VERSION 5.8 ;
BUSBITCHARS "[]" ;
DIVIDERCHAR "/" ;
UNITS
    DATABASE MICRONS 1000 ;
END UNITS

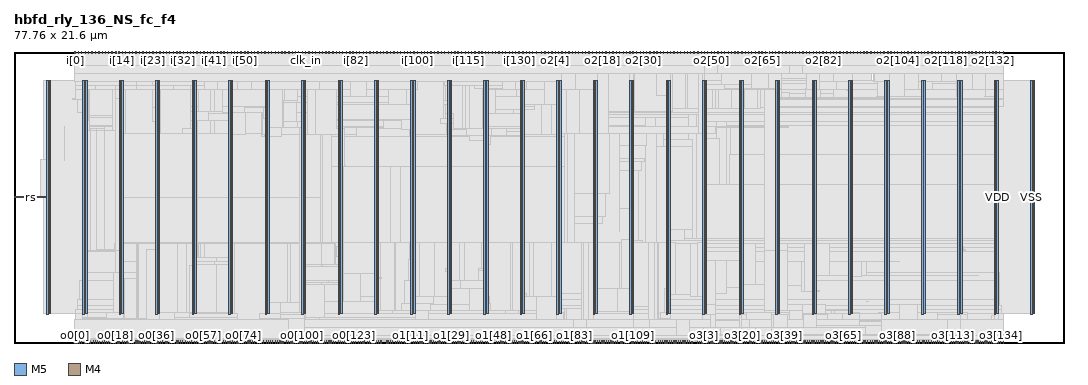
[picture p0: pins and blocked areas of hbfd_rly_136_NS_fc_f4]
MACRO hbfd_rly_136_NS_fc_f4
  FOREIGN hbfd_rly_136_NS_fc_f4 0 0 ;
  CLASS BLOCK ;
  SIZE 77.76 BY 21.6 ;
  PIN clk_in
    DIRECTION INPUT ;
    USE SIGNAL ;
    PORT
      LAYER M5 ;
        RECT  21.6 21.408 21.624 21.6 ;
    END
  END clk_in
  PIN clk_out0
    DIRECTION OUTPUT ;
    USE SIGNAL ;
    PORT
      LAYER M5 ;
        RECT  15.84 0 15.864 0.192 ;
    END
  END clk_out0
  PIN clk_out1
    DIRECTION OUTPUT ;
    USE SIGNAL ;
    PORT
      LAYER M5 ;
        RECT  38.88 0 38.904 0.192 ;
    END
  END clk_out1
  PIN clk_out2
    DIRECTION OUTPUT ;
    USE SIGNAL ;
    PORT
      LAYER M5 ;
        RECT  56.16 21.408 56.184 21.6 ;
    END
  END clk_out2
  PIN clk_out3
    DIRECTION OUTPUT ;
    USE SIGNAL ;
    PORT
      LAYER M5 ;
        RECT  61.92 0 61.944 0.192 ;
    END
  END clk_out3
  PIN i[0]
    DIRECTION INPUT ;
    USE SIGNAL ;
    PORT
      LAYER M5 ;
        RECT  4.512 21.408 4.536 21.6 ;
    END
  END i[0]
  PIN i[100]
    DIRECTION INPUT ;
    USE SIGNAL ;
    PORT
      LAYER M5 ;
        RECT  29.856 21.408 29.88 21.6 ;
    END
  END i[100]
  PIN i[101]
    DIRECTION INPUT ;
    USE SIGNAL ;
    PORT
      LAYER M5 ;
        RECT  30.144 21.408 30.168 21.6 ;
    END
  END i[101]
  PIN i[102]
    DIRECTION INPUT ;
    USE SIGNAL ;
    PORT
      LAYER M5 ;
        RECT  30.384 21.408 30.408 21.6 ;
    END
  END i[102]
  PIN i[103]
    DIRECTION INPUT ;
    USE SIGNAL ;
    PORT
      LAYER M5 ;
        RECT  30.624 21.408 30.648 21.6 ;
    END
  END i[103]
  PIN i[104]
    DIRECTION INPUT ;
    USE SIGNAL ;
    PORT
      LAYER M5 ;
        RECT  30.864 21.408 30.888 21.6 ;
    END
  END i[104]
  PIN i[105]
    DIRECTION INPUT ;
    USE SIGNAL ;
    PORT
      LAYER M5 ;
        RECT  31.152 21.408 31.176 21.6 ;
    END
  END i[105]
  PIN i[106]
    DIRECTION INPUT ;
    USE SIGNAL ;
    PORT
      LAYER M5 ;
        RECT  31.392 21.408 31.416 21.6 ;
    END
  END i[106]
  PIN i[107]
    DIRECTION INPUT ;
    USE SIGNAL ;
    PORT
      LAYER M5 ;
        RECT  31.632 21.408 31.656 21.6 ;
    END
  END i[107]
  PIN i[108]
    DIRECTION INPUT ;
    USE SIGNAL ;
    PORT
      LAYER M5 ;
        RECT  31.872 21.408 31.896 21.6 ;
    END
  END i[108]
  PIN i[109]
    DIRECTION INPUT ;
    USE SIGNAL ;
    PORT
      LAYER M5 ;
        RECT  32.16 21.408 32.184 21.6 ;
    END
  END i[109]
  PIN i[10]
    DIRECTION INPUT ;
    USE SIGNAL ;
    PORT
      LAYER M5 ;
        RECT  7.008 21.408 7.032 21.6 ;
    END
  END i[10]
  PIN i[110]
    DIRECTION INPUT ;
    USE SIGNAL ;
    PORT
      LAYER M5 ;
        RECT  32.4 21.408 32.424 21.6 ;
    END
  END i[110]
  PIN i[111]
    DIRECTION INPUT ;
    USE SIGNAL ;
    PORT
      LAYER M5 ;
        RECT  32.64 21.408 32.664 21.6 ;
    END
  END i[111]
  PIN i[112]
    DIRECTION INPUT ;
    USE SIGNAL ;
    PORT
      LAYER M5 ;
        RECT  32.88 21.408 32.904 21.6 ;
    END
  END i[112]
  PIN i[113]
    DIRECTION INPUT ;
    USE SIGNAL ;
    PORT
      LAYER M5 ;
        RECT  33.12 21.408 33.144 21.6 ;
    END
  END i[113]
  PIN i[114]
    DIRECTION INPUT ;
    USE SIGNAL ;
    PORT
      LAYER M5 ;
        RECT  33.408 21.408 33.432 21.6 ;
    END
  END i[114]
  PIN i[115]
    DIRECTION INPUT ;
    USE SIGNAL ;
    PORT
      LAYER M5 ;
        RECT  33.648 21.408 33.672 21.6 ;
    END
  END i[115]
  PIN i[116]
    DIRECTION INPUT ;
    USE SIGNAL ;
    PORT
      LAYER M5 ;
        RECT  33.888 21.408 33.912 21.6 ;
    END
  END i[116]
  PIN i[117]
    DIRECTION INPUT ;
    USE SIGNAL ;
    PORT
      LAYER M5 ;
        RECT  34.128 21.408 34.152 21.6 ;
    END
  END i[117]
  PIN i[118]
    DIRECTION INPUT ;
    USE SIGNAL ;
    PORT
      LAYER M5 ;
        RECT  34.416 21.408 34.44 21.6 ;
    END
  END i[118]
  PIN i[119]
    DIRECTION INPUT ;
    USE SIGNAL ;
    PORT
      LAYER M5 ;
        RECT  34.656 21.408 34.68 21.6 ;
    END
  END i[119]
  PIN i[11]
    DIRECTION INPUT ;
    USE SIGNAL ;
    PORT
      LAYER M5 ;
        RECT  7.248 21.408 7.272 21.6 ;
    END
  END i[11]
  PIN i[120]
    DIRECTION INPUT ;
    USE SIGNAL ;
    PORT
      LAYER M5 ;
        RECT  34.896 21.408 34.92 21.6 ;
    END
  END i[120]
  PIN i[121]
    DIRECTION INPUT ;
    USE SIGNAL ;
    PORT
      LAYER M5 ;
        RECT  35.136 21.408 35.16 21.6 ;
    END
  END i[121]
  PIN i[122]
    DIRECTION INPUT ;
    USE SIGNAL ;
    PORT
      LAYER M5 ;
        RECT  35.424 21.408 35.448 21.6 ;
    END
  END i[122]
  PIN i[123]
    DIRECTION INPUT ;
    USE SIGNAL ;
    PORT
      LAYER M5 ;
        RECT  35.664 21.408 35.688 21.6 ;
    END
  END i[123]
  PIN i[124]
    DIRECTION INPUT ;
    USE SIGNAL ;
    PORT
      LAYER M5 ;
        RECT  35.904 21.408 35.928 21.6 ;
    END
  END i[124]
  PIN i[125]
    DIRECTION INPUT ;
    USE SIGNAL ;
    PORT
      LAYER M5 ;
        RECT  36.144 21.408 36.168 21.6 ;
    END
  END i[125]
  PIN i[126]
    DIRECTION INPUT ;
    USE SIGNAL ;
    PORT
      LAYER M5 ;
        RECT  36.384 21.408 36.408 21.6 ;
    END
  END i[126]
  PIN i[127]
    DIRECTION INPUT ;
    USE SIGNAL ;
    PORT
      LAYER M5 ;
        RECT  36.672 21.408 36.696 21.6 ;
    END
  END i[127]
  PIN i[128]
    DIRECTION INPUT ;
    USE SIGNAL ;
    PORT
      LAYER M5 ;
        RECT  36.912 21.408 36.936 21.6 ;
    END
  END i[128]
  PIN i[129]
    DIRECTION INPUT ;
    USE SIGNAL ;
    PORT
      LAYER M5 ;
        RECT  37.152 21.408 37.176 21.6 ;
    END
  END i[129]
  PIN i[12]
    DIRECTION INPUT ;
    USE SIGNAL ;
    PORT
      LAYER M5 ;
        RECT  7.536 21.408 7.56 21.6 ;
    END
  END i[12]
  PIN i[130]
    DIRECTION INPUT ;
    USE SIGNAL ;
    PORT
      LAYER M5 ;
        RECT  37.392 21.408 37.416 21.6 ;
    END
  END i[130]
  PIN i[131]
    DIRECTION INPUT ;
    USE SIGNAL ;
    PORT
      LAYER M5 ;
        RECT  37.68 21.408 37.704 21.6 ;
    END
  END i[131]
  PIN i[132]
    DIRECTION INPUT ;
    USE SIGNAL ;
    PORT
      LAYER M5 ;
        RECT  37.92 21.408 37.944 21.6 ;
    END
  END i[132]
  PIN i[133]
    DIRECTION INPUT ;
    USE SIGNAL ;
    PORT
      LAYER M5 ;
        RECT  38.16 21.408 38.184 21.6 ;
    END
  END i[133]
  PIN i[134]
    DIRECTION INPUT ;
    USE SIGNAL ;
    PORT
      LAYER M5 ;
        RECT  38.4 21.408 38.424 21.6 ;
    END
  END i[134]
  PIN i[135]
    DIRECTION INPUT ;
    USE SIGNAL ;
    PORT
      LAYER M5 ;
        RECT  38.688 21.408 38.712 21.6 ;
    END
  END i[135]
  PIN i[13]
    DIRECTION INPUT ;
    USE SIGNAL ;
    PORT
      LAYER M5 ;
        RECT  7.776 21.408 7.8 21.6 ;
    END
  END i[13]
  PIN i[14]
    DIRECTION INPUT ;
    USE SIGNAL ;
    PORT
      LAYER M5 ;
        RECT  8.016 21.408 8.04 21.6 ;
    END
  END i[14]
  PIN i[15]
    DIRECTION INPUT ;
    USE SIGNAL ;
    PORT
      LAYER M5 ;
        RECT  8.256 21.408 8.28 21.6 ;
    END
  END i[15]
  PIN i[16]
    DIRECTION INPUT ;
    USE SIGNAL ;
    PORT
      LAYER M5 ;
        RECT  8.544 21.408 8.568 21.6 ;
    END
  END i[16]
  PIN i[17]
    DIRECTION INPUT ;
    USE SIGNAL ;
    PORT
      LAYER M5 ;
        RECT  8.784 21.408 8.808 21.6 ;
    END
  END i[17]
  PIN i[18]
    DIRECTION INPUT ;
    USE SIGNAL ;
    PORT
      LAYER M5 ;
        RECT  9.024 21.408 9.048 21.6 ;
    END
  END i[18]
  PIN i[19]
    DIRECTION INPUT ;
    USE SIGNAL ;
    PORT
      LAYER M5 ;
        RECT  9.264 21.408 9.288 21.6 ;
    END
  END i[19]
  PIN i[1]
    DIRECTION INPUT ;
    USE SIGNAL ;
    PORT
      LAYER M5 ;
        RECT  4.752 21.408 4.776 21.6 ;
    END
  END i[1]
  PIN i[20]
    DIRECTION INPUT ;
    USE SIGNAL ;
    PORT
      LAYER M5 ;
        RECT  9.552 21.408 9.576 21.6 ;
    END
  END i[20]
  PIN i[21]
    DIRECTION INPUT ;
    USE SIGNAL ;
    PORT
      LAYER M5 ;
        RECT  9.792 21.408 9.816 21.6 ;
    END
  END i[21]
  PIN i[22]
    DIRECTION INPUT ;
    USE SIGNAL ;
    PORT
      LAYER M5 ;
        RECT  10.032 21.408 10.056 21.6 ;
    END
  END i[22]
  PIN i[23]
    DIRECTION INPUT ;
    USE SIGNAL ;
    PORT
      LAYER M5 ;
        RECT  10.272 21.408 10.296 21.6 ;
    END
  END i[23]
  PIN i[24]
    DIRECTION INPUT ;
    USE SIGNAL ;
    PORT
      LAYER M5 ;
        RECT  10.56 21.408 10.584 21.6 ;
    END
  END i[24]
  PIN i[25]
    DIRECTION INPUT ;
    USE SIGNAL ;
    PORT
      LAYER M5 ;
        RECT  10.8 21.408 10.824 21.6 ;
    END
  END i[25]
  PIN i[26]
    DIRECTION INPUT ;
    USE SIGNAL ;
    PORT
      LAYER M5 ;
        RECT  11.04 21.408 11.064 21.6 ;
    END
  END i[26]
  PIN i[27]
    DIRECTION INPUT ;
    USE SIGNAL ;
    PORT
      LAYER M5 ;
        RECT  11.28 21.408 11.304 21.6 ;
    END
  END i[27]
  PIN i[28]
    DIRECTION INPUT ;
    USE SIGNAL ;
    PORT
      LAYER M5 ;
        RECT  11.52 21.408 11.544 21.6 ;
    END
  END i[28]
  PIN i[29]
    DIRECTION INPUT ;
    USE SIGNAL ;
    PORT
      LAYER M5 ;
        RECT  11.808 21.408 11.832 21.6 ;
    END
  END i[29]
  PIN i[2]
    DIRECTION INPUT ;
    USE SIGNAL ;
    PORT
      LAYER M5 ;
        RECT  4.992 21.408 5.016 21.6 ;
    END
  END i[2]
  PIN i[30]
    DIRECTION INPUT ;
    USE SIGNAL ;
    PORT
      LAYER M5 ;
        RECT  12.048 21.408 12.072 21.6 ;
    END
  END i[30]
  PIN i[31]
    DIRECTION INPUT ;
    USE SIGNAL ;
    PORT
      LAYER M5 ;
        RECT  12.288 21.408 12.312 21.6 ;
    END
  END i[31]
  PIN i[32]
    DIRECTION INPUT ;
    USE SIGNAL ;
    PORT
      LAYER M5 ;
        RECT  12.528 21.408 12.552 21.6 ;
    END
  END i[32]
  PIN i[33]
    DIRECTION INPUT ;
    USE SIGNAL ;
    PORT
      LAYER M5 ;
        RECT  12.816 21.408 12.84 21.6 ;
    END
  END i[33]
  PIN i[34]
    DIRECTION INPUT ;
    USE SIGNAL ;
    PORT
      LAYER M5 ;
        RECT  13.056 21.408 13.08 21.6 ;
    END
  END i[34]
  PIN i[35]
    DIRECTION INPUT ;
    USE SIGNAL ;
    PORT
      LAYER M5 ;
        RECT  13.296 21.408 13.32 21.6 ;
    END
  END i[35]
  PIN i[36]
    DIRECTION INPUT ;
    USE SIGNAL ;
    PORT
      LAYER M5 ;
        RECT  13.536 21.408 13.56 21.6 ;
    END
  END i[36]
  PIN i[37]
    DIRECTION INPUT ;
    USE SIGNAL ;
    PORT
      LAYER M5 ;
        RECT  13.824 21.408 13.848 21.6 ;
    END
  END i[37]
  PIN i[38]
    DIRECTION INPUT ;
    USE SIGNAL ;
    PORT
      LAYER M5 ;
        RECT  14.064 21.408 14.088 21.6 ;
    END
  END i[38]
  PIN i[39]
    DIRECTION INPUT ;
    USE SIGNAL ;
    PORT
      LAYER M5 ;
        RECT  14.304 21.408 14.328 21.6 ;
    END
  END i[39]
  PIN i[3]
    DIRECTION INPUT ;
    USE SIGNAL ;
    PORT
      LAYER M5 ;
        RECT  5.28 21.408 5.304 21.6 ;
    END
  END i[3]
  PIN i[40]
    DIRECTION INPUT ;
    USE SIGNAL ;
    PORT
      LAYER M5 ;
        RECT  14.544 21.408 14.568 21.6 ;
    END
  END i[40]
  PIN i[41]
    DIRECTION INPUT ;
    USE SIGNAL ;
    PORT
      LAYER M5 ;
        RECT  14.784 21.408 14.808 21.6 ;
    END
  END i[41]
  PIN i[42]
    DIRECTION INPUT ;
    USE SIGNAL ;
    PORT
      LAYER M5 ;
        RECT  15.072 21.408 15.096 21.6 ;
    END
  END i[42]
  PIN i[43]
    DIRECTION INPUT ;
    USE SIGNAL ;
    PORT
      LAYER M5 ;
        RECT  15.312 21.408 15.336 21.6 ;
    END
  END i[43]
  PIN i[44]
    DIRECTION INPUT ;
    USE SIGNAL ;
    PORT
      LAYER M5 ;
        RECT  15.552 21.408 15.576 21.6 ;
    END
  END i[44]
  PIN i[45]
    DIRECTION INPUT ;
    USE SIGNAL ;
    PORT
      LAYER M5 ;
        RECT  15.792 21.408 15.816 21.6 ;
    END
  END i[45]
  PIN i[46]
    DIRECTION INPUT ;
    USE SIGNAL ;
    PORT
      LAYER M5 ;
        RECT  16.08 21.408 16.104 21.6 ;
    END
  END i[46]
  PIN i[47]
    DIRECTION INPUT ;
    USE SIGNAL ;
    PORT
      LAYER M5 ;
        RECT  16.32 21.408 16.344 21.6 ;
    END
  END i[47]
  PIN i[48]
    DIRECTION INPUT ;
    USE SIGNAL ;
    PORT
      LAYER M5 ;
        RECT  16.56 21.408 16.584 21.6 ;
    END
  END i[48]
  PIN i[49]
    DIRECTION INPUT ;
    USE SIGNAL ;
    PORT
      LAYER M5 ;
        RECT  16.8 21.408 16.824 21.6 ;
    END
  END i[49]
  PIN i[4]
    DIRECTION INPUT ;
    USE SIGNAL ;
    PORT
      LAYER M5 ;
        RECT  5.52 21.408 5.544 21.6 ;
    END
  END i[4]
  PIN i[50]
    DIRECTION INPUT ;
    USE SIGNAL ;
    PORT
      LAYER M5 ;
        RECT  17.088 21.408 17.112 21.6 ;
    END
  END i[50]
  PIN i[51]
    DIRECTION INPUT ;
    USE SIGNAL ;
    PORT
      LAYER M5 ;
        RECT  17.328 21.408 17.352 21.6 ;
    END
  END i[51]
  PIN i[52]
    DIRECTION INPUT ;
    USE SIGNAL ;
    PORT
      LAYER M5 ;
        RECT  17.568 21.408 17.592 21.6 ;
    END
  END i[52]
  PIN i[53]
    DIRECTION INPUT ;
    USE SIGNAL ;
    PORT
      LAYER M5 ;
        RECT  17.808 21.408 17.832 21.6 ;
    END
  END i[53]
  PIN i[54]
    DIRECTION INPUT ;
    USE SIGNAL ;
    PORT
      LAYER M5 ;
        RECT  18.048 21.408 18.072 21.6 ;
    END
  END i[54]
  PIN i[55]
    DIRECTION INPUT ;
    USE SIGNAL ;
    PORT
      LAYER M5 ;
        RECT  18.336 21.408 18.36 21.6 ;
    END
  END i[55]
  PIN i[56]
    DIRECTION INPUT ;
    USE SIGNAL ;
    PORT
      LAYER M5 ;
        RECT  18.576 21.408 18.6 21.6 ;
    END
  END i[56]
  PIN i[57]
    DIRECTION INPUT ;
    USE SIGNAL ;
    PORT
      LAYER M5 ;
        RECT  18.816 21.408 18.84 21.6 ;
    END
  END i[57]
  PIN i[58]
    DIRECTION INPUT ;
    USE SIGNAL ;
    PORT
      LAYER M5 ;
        RECT  19.056 21.408 19.08 21.6 ;
    END
  END i[58]
  PIN i[59]
    DIRECTION INPUT ;
    USE SIGNAL ;
    PORT
      LAYER M5 ;
        RECT  19.344 21.408 19.368 21.6 ;
    END
  END i[59]
  PIN i[5]
    DIRECTION INPUT ;
    USE SIGNAL ;
    PORT
      LAYER M5 ;
        RECT  5.76 21.408 5.784 21.6 ;
    END
  END i[5]
  PIN i[60]
    DIRECTION INPUT ;
    USE SIGNAL ;
    PORT
      LAYER M5 ;
        RECT  19.584 21.408 19.608 21.6 ;
    END
  END i[60]
  PIN i[61]
    DIRECTION INPUT ;
    USE SIGNAL ;
    PORT
      LAYER M5 ;
        RECT  19.824 21.408 19.848 21.6 ;
    END
  END i[61]
  PIN i[62]
    DIRECTION INPUT ;
    USE SIGNAL ;
    PORT
      LAYER M5 ;
        RECT  20.064 21.408 20.088 21.6 ;
    END
  END i[62]
  PIN i[63]
    DIRECTION INPUT ;
    USE SIGNAL ;
    PORT
      LAYER M5 ;
        RECT  20.352 21.408 20.376 21.6 ;
    END
  END i[63]
  PIN i[64]
    DIRECTION INPUT ;
    USE SIGNAL ;
    PORT
      LAYER M5 ;
        RECT  20.592 21.408 20.616 21.6 ;
    END
  END i[64]
  PIN i[65]
    DIRECTION INPUT ;
    USE SIGNAL ;
    PORT
      LAYER M5 ;
        RECT  20.832 21.408 20.856 21.6 ;
    END
  END i[65]
  PIN i[66]
    DIRECTION INPUT ;
    USE SIGNAL ;
    PORT
      LAYER M5 ;
        RECT  21.072 21.408 21.096 21.6 ;
    END
  END i[66]
  PIN i[67]
    DIRECTION INPUT ;
    USE SIGNAL ;
    PORT
      LAYER M5 ;
        RECT  21.36 21.408 21.384 21.6 ;
    END
  END i[67]
  PIN i[68]
    DIRECTION INPUT ;
    USE SIGNAL ;
    PORT
      LAYER M5 ;
        RECT  21.84 21.408 21.864 21.6 ;
    END
  END i[68]
  PIN i[69]
    DIRECTION INPUT ;
    USE SIGNAL ;
    PORT
      LAYER M5 ;
        RECT  22.08 21.408 22.104 21.6 ;
    END
  END i[69]
  PIN i[6]
    DIRECTION INPUT ;
    USE SIGNAL ;
    PORT
      LAYER M5 ;
        RECT  6 21.408 6.024 21.6 ;
    END
  END i[6]
  PIN i[70]
    DIRECTION INPUT ;
    USE SIGNAL ;
    PORT
      LAYER M5 ;
        RECT  22.32 21.408 22.344 21.6 ;
    END
  END i[70]
  PIN i[71]
    DIRECTION INPUT ;
    USE SIGNAL ;
    PORT
      LAYER M5 ;
        RECT  22.608 21.408 22.632 21.6 ;
    END
  END i[71]
  PIN i[72]
    DIRECTION INPUT ;
    USE SIGNAL ;
    PORT
      LAYER M5 ;
        RECT  22.848 21.408 22.872 21.6 ;
    END
  END i[72]
  PIN i[73]
    DIRECTION INPUT ;
    USE SIGNAL ;
    PORT
      LAYER M5 ;
        RECT  23.088 21.408 23.112 21.6 ;
    END
  END i[73]
  PIN i[74]
    DIRECTION INPUT ;
    USE SIGNAL ;
    PORT
      LAYER M5 ;
        RECT  23.328 21.408 23.352 21.6 ;
    END
  END i[74]
  PIN i[75]
    DIRECTION INPUT ;
    USE SIGNAL ;
    PORT
      LAYER M5 ;
        RECT  23.616 21.408 23.64 21.6 ;
    END
  END i[75]
  PIN i[76]
    DIRECTION INPUT ;
    USE SIGNAL ;
    PORT
      LAYER M5 ;
        RECT  23.856 21.408 23.88 21.6 ;
    END
  END i[76]
  PIN i[77]
    DIRECTION INPUT ;
    USE SIGNAL ;
    PORT
      LAYER M5 ;
        RECT  24.096 21.408 24.12 21.6 ;
    END
  END i[77]
  PIN i[78]
    DIRECTION INPUT ;
    USE SIGNAL ;
    PORT
      LAYER M5 ;
        RECT  24.336 21.408 24.36 21.6 ;
    END
  END i[78]
  PIN i[79]
    DIRECTION INPUT ;
    USE SIGNAL ;
    PORT
      LAYER M5 ;
        RECT  24.624 21.408 24.648 21.6 ;
    END
  END i[79]
  PIN i[7]
    DIRECTION INPUT ;
    USE SIGNAL ;
    PORT
      LAYER M5 ;
        RECT  6.288 21.408 6.312 21.6 ;
    END
  END i[7]
  PIN i[80]
    DIRECTION INPUT ;
    USE SIGNAL ;
    PORT
      LAYER M5 ;
        RECT  24.864 21.408 24.888 21.6 ;
    END
  END i[80]
  PIN i[81]
    DIRECTION INPUT ;
    USE SIGNAL ;
    PORT
      LAYER M5 ;
        RECT  25.104 21.408 25.128 21.6 ;
    END
  END i[81]
  PIN i[82]
    DIRECTION INPUT ;
    USE SIGNAL ;
    PORT
      LAYER M5 ;
        RECT  25.344 21.408 25.368 21.6 ;
    END
  END i[82]
  PIN i[83]
    DIRECTION INPUT ;
    USE SIGNAL ;
    PORT
      LAYER M5 ;
        RECT  25.584 21.408 25.608 21.6 ;
    END
  END i[83]
  PIN i[84]
    DIRECTION INPUT ;
    USE SIGNAL ;
    PORT
      LAYER M5 ;
        RECT  25.872 21.408 25.896 21.6 ;
    END
  END i[84]
  PIN i[85]
    DIRECTION INPUT ;
    USE SIGNAL ;
    PORT
      LAYER M5 ;
        RECT  26.112 21.408 26.136 21.6 ;
    END
  END i[85]
  PIN i[86]
    DIRECTION INPUT ;
    USE SIGNAL ;
    PORT
      LAYER M5 ;
        RECT  26.352 21.408 26.376 21.6 ;
    END
  END i[86]
  PIN i[87]
    DIRECTION INPUT ;
    USE SIGNAL ;
    PORT
      LAYER M5 ;
        RECT  26.592 21.408 26.616 21.6 ;
    END
  END i[87]
  PIN i[88]
    DIRECTION INPUT ;
    USE SIGNAL ;
    PORT
      LAYER M5 ;
        RECT  26.88 21.408 26.904 21.6 ;
    END
  END i[88]
  PIN i[89]
    DIRECTION INPUT ;
    USE SIGNAL ;
    PORT
      LAYER M5 ;
        RECT  27.12 21.408 27.144 21.6 ;
    END
  END i[89]
  PIN i[8]
    DIRECTION INPUT ;
    USE SIGNAL ;
    PORT
      LAYER M5 ;
        RECT  6.528 21.408 6.552 21.6 ;
    END
  END i[8]
  PIN i[90]
    DIRECTION INPUT ;
    USE SIGNAL ;
    PORT
      LAYER M5 ;
        RECT  27.36 21.408 27.384 21.6 ;
    END
  END i[90]
  PIN i[91]
    DIRECTION INPUT ;
    USE SIGNAL ;
    PORT
      LAYER M5 ;
        RECT  27.6 21.408 27.624 21.6 ;
    END
  END i[91]
  PIN i[92]
    DIRECTION INPUT ;
    USE SIGNAL ;
    PORT
      LAYER M5 ;
        RECT  27.888 21.408 27.912 21.6 ;
    END
  END i[92]
  PIN i[93]
    DIRECTION INPUT ;
    USE SIGNAL ;
    PORT
      LAYER M5 ;
        RECT  28.128 21.408 28.152 21.6 ;
    END
  END i[93]
  PIN i[94]
    DIRECTION INPUT ;
    USE SIGNAL ;
    PORT
      LAYER M5 ;
        RECT  28.368 21.408 28.392 21.6 ;
    END
  END i[94]
  PIN i[95]
    DIRECTION INPUT ;
    USE SIGNAL ;
    PORT
      LAYER M5 ;
        RECT  28.608 21.408 28.632 21.6 ;
    END
  END i[95]
  PIN i[96]
    DIRECTION INPUT ;
    USE SIGNAL ;
    PORT
      LAYER M5 ;
        RECT  28.896 21.408 28.92 21.6 ;
    END
  END i[96]
  PIN i[97]
    DIRECTION INPUT ;
    USE SIGNAL ;
    PORT
      LAYER M5 ;
        RECT  29.136 21.408 29.16 21.6 ;
    END
  END i[97]
  PIN i[98]
    DIRECTION INPUT ;
    USE SIGNAL ;
    PORT
      LAYER M5 ;
        RECT  29.376 21.408 29.4 21.6 ;
    END
  END i[98]
  PIN i[99]
    DIRECTION INPUT ;
    USE SIGNAL ;
    PORT
      LAYER M5 ;
        RECT  29.616 21.408 29.64 21.6 ;
    END
  END i[99]
  PIN i[9]
    DIRECTION INPUT ;
    USE SIGNAL ;
    PORT
      LAYER M5 ;
        RECT  6.768 21.408 6.792 21.6 ;
    END
  END i[9]
  PIN o0[0]
    DIRECTION OUTPUT ;
    USE SIGNAL ;
    PORT
      LAYER M5 ;
        RECT  4.512 0 4.536 0.192 ;
    END
  END o0[0]
  PIN o0[100]
    DIRECTION OUTPUT ;
    USE SIGNAL ;
    PORT
      LAYER M5 ;
        RECT  21.312 0 21.336 0.192 ;
    END
  END o0[100]
  PIN o0[101]
    DIRECTION OUTPUT ;
    USE SIGNAL ;
    PORT
      LAYER M5 ;
        RECT  21.504 0 21.528 0.192 ;
    END
  END o0[101]
  PIN o0[102]
    DIRECTION OUTPUT ;
    USE SIGNAL ;
    PORT
      LAYER M5 ;
        RECT  21.648 0 21.672 0.192 ;
    END
  END o0[102]
  PIN o0[103]
    DIRECTION OUTPUT ;
    USE SIGNAL ;
    PORT
      LAYER M5 ;
        RECT  21.84 0 21.864 0.192 ;
    END
  END o0[103]
  PIN o0[104]
    DIRECTION OUTPUT ;
    USE SIGNAL ;
    PORT
      LAYER M5 ;
        RECT  21.984 0 22.008 0.192 ;
    END
  END o0[104]
  PIN o0[105]
    DIRECTION OUTPUT ;
    USE SIGNAL ;
    PORT
      LAYER M5 ;
        RECT  22.176 0 22.2 0.192 ;
    END
  END o0[105]
  PIN o0[106]
    DIRECTION OUTPUT ;
    USE SIGNAL ;
    PORT
      LAYER M5 ;
        RECT  22.32 0 22.344 0.192 ;
    END
  END o0[106]
  PIN o0[107]
    DIRECTION OUTPUT ;
    USE SIGNAL ;
    PORT
      LAYER M5 ;
        RECT  22.464 0 22.488 0.192 ;
    END
  END o0[107]
  PIN o0[108]
    DIRECTION OUTPUT ;
    USE SIGNAL ;
    PORT
      LAYER M5 ;
        RECT  22.656 0 22.68 0.192 ;
    END
  END o0[108]
  PIN o0[109]
    DIRECTION OUTPUT ;
    USE SIGNAL ;
    PORT
      LAYER M5 ;
        RECT  22.8 0 22.824 0.192 ;
    END
  END o0[109]
  PIN o0[10]
    DIRECTION OUTPUT ;
    USE SIGNAL ;
    PORT
      LAYER M5 ;
        RECT  6.192 0 6.216 0.192 ;
    END
  END o0[10]
  PIN o0[110]
    DIRECTION OUTPUT ;
    USE SIGNAL ;
    PORT
      LAYER M5 ;
        RECT  22.992 0 23.016 0.192 ;
    END
  END o0[110]
  PIN o0[111]
    DIRECTION OUTPUT ;
    USE SIGNAL ;
    PORT
      LAYER M5 ;
        RECT  23.136 0 23.16 0.192 ;
    END
  END o0[111]
  PIN o0[112]
    DIRECTION OUTPUT ;
    USE SIGNAL ;
    PORT
      LAYER M5 ;
        RECT  23.328 0 23.352 0.192 ;
    END
  END o0[112]
  PIN o0[113]
    DIRECTION OUTPUT ;
    USE SIGNAL ;
    PORT
      LAYER M5 ;
        RECT  23.472 0 23.496 0.192 ;
    END
  END o0[113]
  PIN o0[114]
    DIRECTION OUTPUT ;
    USE SIGNAL ;
    PORT
      LAYER M5 ;
        RECT  23.664 0 23.688 0.192 ;
    END
  END o0[114]
  PIN o0[115]
    DIRECTION OUTPUT ;
    USE SIGNAL ;
    PORT
      LAYER M5 ;
        RECT  23.808 0 23.832 0.192 ;
    END
  END o0[115]
  PIN o0[116]
    DIRECTION OUTPUT ;
    USE SIGNAL ;
    PORT
      LAYER M5 ;
        RECT  24 0 24.024 0.192 ;
    END
  END o0[116]
  PIN o0[117]
    DIRECTION OUTPUT ;
    USE SIGNAL ;
    PORT
      LAYER M5 ;
        RECT  24.144 0 24.168 0.192 ;
    END
  END o0[117]
  PIN o0[118]
    DIRECTION OUTPUT ;
    USE SIGNAL ;
    PORT
      LAYER M5 ;
        RECT  24.336 0 24.36 0.192 ;
    END
  END o0[118]
  PIN o0[119]
    DIRECTION OUTPUT ;
    USE SIGNAL ;
    PORT
      LAYER M5 ;
        RECT  24.48 0 24.504 0.192 ;
    END
  END o0[119]
  PIN o0[11]
    DIRECTION OUTPUT ;
    USE SIGNAL ;
    PORT
      LAYER M5 ;
        RECT  6.336 0 6.36 0.192 ;
    END
  END o0[11]
  PIN o0[120]
    DIRECTION OUTPUT ;
    USE SIGNAL ;
    PORT
      LAYER M5 ;
        RECT  24.672 0 24.696 0.192 ;
    END
  END o0[120]
  PIN o0[121]
    DIRECTION OUTPUT ;
    USE SIGNAL ;
    PORT
      LAYER M5 ;
        RECT  24.816 0 24.84 0.192 ;
    END
  END o0[121]
  PIN o0[122]
    DIRECTION OUTPUT ;
    USE SIGNAL ;
    PORT
      LAYER M5 ;
        RECT  24.96 0 24.984 0.192 ;
    END
  END o0[122]
  PIN o0[123]
    DIRECTION OUTPUT ;
    USE SIGNAL ;
    PORT
      LAYER M5 ;
        RECT  25.152 0 25.176 0.192 ;
    END
  END o0[123]
  PIN o0[124]
    DIRECTION OUTPUT ;
    USE SIGNAL ;
    PORT
      LAYER M5 ;
        RECT  25.296 0 25.32 0.192 ;
    END
  END o0[124]
  PIN o0[125]
    DIRECTION OUTPUT ;
    USE SIGNAL ;
    PORT
      LAYER M5 ;
        RECT  25.488 0 25.512 0.192 ;
    END
  END o0[125]
  PIN o0[126]
    DIRECTION OUTPUT ;
    USE SIGNAL ;
    PORT
      LAYER M5 ;
        RECT  25.632 0 25.656 0.192 ;
    END
  END o0[126]
  PIN o0[127]
    DIRECTION OUTPUT ;
    USE SIGNAL ;
    PORT
      LAYER M5 ;
        RECT  25.824 0 25.848 0.192 ;
    END
  END o0[127]
  PIN o0[128]
    DIRECTION OUTPUT ;
    USE SIGNAL ;
    PORT
      LAYER M5 ;
        RECT  25.968 0 25.992 0.192 ;
    END
  END o0[128]
  PIN o0[129]
    DIRECTION OUTPUT ;
    USE SIGNAL ;
    PORT
      LAYER M5 ;
        RECT  26.16 0 26.184 0.192 ;
    END
  END o0[129]
  PIN o0[12]
    DIRECTION OUTPUT ;
    USE SIGNAL ;
    PORT
      LAYER M5 ;
        RECT  6.528 0 6.552 0.192 ;
    END
  END o0[12]
  PIN o0[130]
    DIRECTION OUTPUT ;
    USE SIGNAL ;
    PORT
      LAYER M5 ;
        RECT  26.304 0 26.328 0.192 ;
    END
  END o0[130]
  PIN o0[131]
    DIRECTION OUTPUT ;
    USE SIGNAL ;
    PORT
      LAYER M5 ;
        RECT  26.496 0 26.52 0.192 ;
    END
  END o0[131]
  PIN o0[132]
    DIRECTION OUTPUT ;
    USE SIGNAL ;
    PORT
      LAYER M5 ;
        RECT  26.64 0 26.664 0.192 ;
    END
  END o0[132]
  PIN o0[133]
    DIRECTION OUTPUT ;
    USE SIGNAL ;
    PORT
      LAYER M5 ;
        RECT  26.832 0 26.856 0.192 ;
    END
  END o0[133]
  PIN o0[134]
    DIRECTION OUTPUT ;
    USE SIGNAL ;
    PORT
      LAYER M5 ;
        RECT  26.976 0 27 0.192 ;
    END
  END o0[134]
  PIN o0[135]
    DIRECTION OUTPUT ;
    USE SIGNAL ;
    PORT
      LAYER M5 ;
        RECT  27.168 0 27.192 0.192 ;
    END
  END o0[135]
  PIN o0[13]
    DIRECTION OUTPUT ;
    USE SIGNAL ;
    PORT
      LAYER M5 ;
        RECT  6.672 0 6.696 0.192 ;
    END
  END o0[13]
  PIN o0[14]
    DIRECTION OUTPUT ;
    USE SIGNAL ;
    PORT
      LAYER M5 ;
        RECT  6.816 0 6.84 0.192 ;
    END
  END o0[14]
  PIN o0[15]
    DIRECTION OUTPUT ;
    USE SIGNAL ;
    PORT
      LAYER M5 ;
        RECT  7.008 0 7.032 0.192 ;
    END
  END o0[15]
  PIN o0[16]
    DIRECTION OUTPUT ;
    USE SIGNAL ;
    PORT
      LAYER M5 ;
        RECT  7.152 0 7.176 0.192 ;
    END
  END o0[16]
  PIN o0[17]
    DIRECTION OUTPUT ;
    USE SIGNAL ;
    PORT
      LAYER M5 ;
        RECT  7.344 0 7.368 0.192 ;
    END
  END o0[17]
  PIN o0[18]
    DIRECTION OUTPUT ;
    USE SIGNAL ;
    PORT
      LAYER M5 ;
        RECT  7.488 0 7.512 0.192 ;
    END
  END o0[18]
  PIN o0[19]
    DIRECTION OUTPUT ;
    USE SIGNAL ;
    PORT
      LAYER M5 ;
        RECT  7.68 0 7.704 0.192 ;
    END
  END o0[19]
  PIN o0[1]
    DIRECTION OUTPUT ;
    USE SIGNAL ;
    PORT
      LAYER M5 ;
        RECT  4.656 0 4.68 0.192 ;
    END
  END o0[1]
  PIN o0[20]
    DIRECTION OUTPUT ;
    USE SIGNAL ;
    PORT
      LAYER M5 ;
        RECT  7.824 0 7.848 0.192 ;
    END
  END o0[20]
  PIN o0[21]
    DIRECTION OUTPUT ;
    USE SIGNAL ;
    PORT
      LAYER M5 ;
        RECT  8.016 0 8.04 0.192 ;
    END
  END o0[21]
  PIN o0[22]
    DIRECTION OUTPUT ;
    USE SIGNAL ;
    PORT
      LAYER M5 ;
        RECT  8.16 0 8.184 0.192 ;
    END
  END o0[22]
  PIN o0[23]
    DIRECTION OUTPUT ;
    USE SIGNAL ;
    PORT
      LAYER M5 ;
        RECT  8.352 0 8.376 0.192 ;
    END
  END o0[23]
  PIN o0[24]
    DIRECTION OUTPUT ;
    USE SIGNAL ;
    PORT
      LAYER M5 ;
        RECT  8.496 0 8.52 0.192 ;
    END
  END o0[24]
  PIN o0[25]
    DIRECTION OUTPUT ;
    USE SIGNAL ;
    PORT
      LAYER M5 ;
        RECT  8.688 0 8.712 0.192 ;
    END
  END o0[25]
  PIN o0[26]
    DIRECTION OUTPUT ;
    USE SIGNAL ;
    PORT
      LAYER M5 ;
        RECT  8.832 0 8.856 0.192 ;
    END
  END o0[26]
  PIN o0[27]
    DIRECTION OUTPUT ;
    USE SIGNAL ;
    PORT
      LAYER M5 ;
        RECT  9.024 0 9.048 0.192 ;
    END
  END o0[27]
  PIN o0[28]
    DIRECTION OUTPUT ;
    USE SIGNAL ;
    PORT
      LAYER M5 ;
        RECT  9.168 0 9.192 0.192 ;
    END
  END o0[28]
  PIN o0[29]
    DIRECTION OUTPUT ;
    USE SIGNAL ;
    PORT
      LAYER M5 ;
        RECT  9.312 0 9.336 0.192 ;
    END
  END o0[29]
  PIN o0[2]
    DIRECTION OUTPUT ;
    USE SIGNAL ;
    PORT
      LAYER M5 ;
        RECT  4.848 0 4.872 0.192 ;
    END
  END o0[2]
  PIN o0[30]
    DIRECTION OUTPUT ;
    USE SIGNAL ;
    PORT
      LAYER M5 ;
        RECT  9.504 0 9.528 0.192 ;
    END
  END o0[30]
  PIN o0[31]
    DIRECTION OUTPUT ;
    USE SIGNAL ;
    PORT
      LAYER M5 ;
        RECT  9.648 0 9.672 0.192 ;
    END
  END o0[31]
  PIN o0[32]
    DIRECTION OUTPUT ;
    USE SIGNAL ;
    PORT
      LAYER M5 ;
        RECT  9.84 0 9.864 0.192 ;
    END
  END o0[32]
  PIN o0[33]
    DIRECTION OUTPUT ;
    USE SIGNAL ;
    PORT
      LAYER M5 ;
        RECT  9.984 0 10.008 0.192 ;
    END
  END o0[33]
  PIN o0[34]
    DIRECTION OUTPUT ;
    USE SIGNAL ;
    PORT
      LAYER M5 ;
        RECT  10.176 0 10.2 0.192 ;
    END
  END o0[34]
  PIN o0[35]
    DIRECTION OUTPUT ;
    USE SIGNAL ;
    PORT
      LAYER M5 ;
        RECT  10.32 0 10.344 0.192 ;
    END
  END o0[35]
  PIN o0[36]
    DIRECTION OUTPUT ;
    USE SIGNAL ;
    PORT
      LAYER M5 ;
        RECT  10.512 0 10.536 0.192 ;
    END
  END o0[36]
  PIN o0[37]
    DIRECTION OUTPUT ;
    USE SIGNAL ;
    PORT
      LAYER M5 ;
        RECT  10.656 0 10.68 0.192 ;
    END
  END o0[37]
  PIN o0[38]
    DIRECTION OUTPUT ;
    USE SIGNAL ;
    PORT
      LAYER M5 ;
        RECT  10.848 0 10.872 0.192 ;
    END
  END o0[38]
  PIN o0[39]
    DIRECTION OUTPUT ;
    USE SIGNAL ;
    PORT
      LAYER M5 ;
        RECT  10.992 0 11.016 0.192 ;
    END
  END o0[39]
  PIN o0[3]
    DIRECTION OUTPUT ;
    USE SIGNAL ;
    PORT
      LAYER M5 ;
        RECT  4.992 0 5.016 0.192 ;
    END
  END o0[3]
  PIN o0[40]
    DIRECTION OUTPUT ;
    USE SIGNAL ;
    PORT
      LAYER M5 ;
        RECT  11.184 0 11.208 0.192 ;
    END
  END o0[40]
  PIN o0[41]
    DIRECTION OUTPUT ;
    USE SIGNAL ;
    PORT
      LAYER M5 ;
        RECT  11.328 0 11.352 0.192 ;
    END
  END o0[41]
  PIN o0[42]
    DIRECTION OUTPUT ;
    USE SIGNAL ;
    PORT
      LAYER M5 ;
        RECT  11.52 0 11.544 0.192 ;
    END
  END o0[42]
  PIN o0[43]
    DIRECTION OUTPUT ;
    USE SIGNAL ;
    PORT
      LAYER M5 ;
        RECT  11.664 0 11.688 0.192 ;
    END
  END o0[43]
  PIN o0[44]
    DIRECTION OUTPUT ;
    USE SIGNAL ;
    PORT
      LAYER M5 ;
        RECT  11.856 0 11.88 0.192 ;
    END
  END o0[44]
  PIN o0[45]
    DIRECTION OUTPUT ;
    USE SIGNAL ;
    PORT
      LAYER M5 ;
        RECT  12 0 12.024 0.192 ;
    END
  END o0[45]
  PIN o0[46]
    DIRECTION OUTPUT ;
    USE SIGNAL ;
    PORT
      LAYER M5 ;
        RECT  12.144 0 12.168 0.192 ;
    END
  END o0[46]
  PIN o0[47]
    DIRECTION OUTPUT ;
    USE SIGNAL ;
    PORT
      LAYER M5 ;
        RECT  12.336 0 12.36 0.192 ;
    END
  END o0[47]
  PIN o0[48]
    DIRECTION OUTPUT ;
    USE SIGNAL ;
    PORT
      LAYER M5 ;
        RECT  12.48 0 12.504 0.192 ;
    END
  END o0[48]
  PIN o0[49]
    DIRECTION OUTPUT ;
    USE SIGNAL ;
    PORT
      LAYER M5 ;
        RECT  12.672 0 12.696 0.192 ;
    END
  END o0[49]
  PIN o0[4]
    DIRECTION OUTPUT ;
    USE SIGNAL ;
    PORT
      LAYER M5 ;
        RECT  5.184 0 5.208 0.192 ;
    END
  END o0[4]
  PIN o0[50]
    DIRECTION OUTPUT ;
    USE SIGNAL ;
    PORT
      LAYER M5 ;
        RECT  12.816 0 12.84 0.192 ;
    END
  END o0[50]
  PIN o0[51]
    DIRECTION OUTPUT ;
    USE SIGNAL ;
    PORT
      LAYER M5 ;
        RECT  13.008 0 13.032 0.192 ;
    END
  END o0[51]
  PIN o0[52]
    DIRECTION OUTPUT ;
    USE SIGNAL ;
    PORT
      LAYER M5 ;
        RECT  13.152 0 13.176 0.192 ;
    END
  END o0[52]
  PIN o0[53]
    DIRECTION OUTPUT ;
    USE SIGNAL ;
    PORT
      LAYER M5 ;
        RECT  13.344 0 13.368 0.192 ;
    END
  END o0[53]
  PIN o0[54]
    DIRECTION OUTPUT ;
    USE SIGNAL ;
    PORT
      LAYER M5 ;
        RECT  13.488 0 13.512 0.192 ;
    END
  END o0[54]
  PIN o0[55]
    DIRECTION OUTPUT ;
    USE SIGNAL ;
    PORT
      LAYER M5 ;
        RECT  13.68 0 13.704 0.192 ;
    END
  END o0[55]
  PIN o0[56]
    DIRECTION OUTPUT ;
    USE SIGNAL ;
    PORT
      LAYER M5 ;
        RECT  13.824 0 13.848 0.192 ;
    END
  END o0[56]
  PIN o0[57]
    DIRECTION OUTPUT ;
    USE SIGNAL ;
    PORT
      LAYER M5 ;
        RECT  14.016 0 14.04 0.192 ;
    END
  END o0[57]
  PIN o0[58]
    DIRECTION OUTPUT ;
    USE SIGNAL ;
    PORT
      LAYER M5 ;
        RECT  14.16 0 14.184 0.192 ;
    END
  END o0[58]
  PIN o0[59]
    DIRECTION OUTPUT ;
    USE SIGNAL ;
    PORT
      LAYER M5 ;
        RECT  14.352 0 14.376 0.192 ;
    END
  END o0[59]
  PIN o0[5]
    DIRECTION OUTPUT ;
    USE SIGNAL ;
    PORT
      LAYER M5 ;
        RECT  5.328 0 5.352 0.192 ;
    END
  END o0[5]
  PIN o0[60]
    DIRECTION OUTPUT ;
    USE SIGNAL ;
    PORT
      LAYER M5 ;
        RECT  14.496 0 14.52 0.192 ;
    END
  END o0[60]
  PIN o0[61]
    DIRECTION OUTPUT ;
    USE SIGNAL ;
    PORT
      LAYER M5 ;
        RECT  14.64 0 14.664 0.192 ;
    END
  END o0[61]
  PIN o0[62]
    DIRECTION OUTPUT ;
    USE SIGNAL ;
    PORT
      LAYER M5 ;
        RECT  14.832 0 14.856 0.192 ;
    END
  END o0[62]
  PIN o0[63]
    DIRECTION OUTPUT ;
    USE SIGNAL ;
    PORT
      LAYER M5 ;
        RECT  14.976 0 15 0.192 ;
    END
  END o0[63]
  PIN o0[64]
    DIRECTION OUTPUT ;
    USE SIGNAL ;
    PORT
      LAYER M5 ;
        RECT  15.168 0 15.192 0.192 ;
    END
  END o0[64]
  PIN o0[65]
    DIRECTION OUTPUT ;
    USE SIGNAL ;
    PORT
      LAYER M5 ;
        RECT  15.312 0 15.336 0.192 ;
    END
  END o0[65]
  PIN o0[66]
    DIRECTION OUTPUT ;
    USE SIGNAL ;
    PORT
      LAYER M5 ;
        RECT  15.504 0 15.528 0.192 ;
    END
  END o0[66]
  PIN o0[67]
    DIRECTION OUTPUT ;
    USE SIGNAL ;
    PORT
      LAYER M5 ;
        RECT  15.648 0 15.672 0.192 ;
    END
  END o0[67]
  PIN o0[68]
    DIRECTION OUTPUT ;
    USE SIGNAL ;
    PORT
      LAYER M5 ;
        RECT  15.984 0 16.008 0.192 ;
    END
  END o0[68]
  PIN o0[69]
    DIRECTION OUTPUT ;
    USE SIGNAL ;
    PORT
      LAYER M5 ;
        RECT  16.176 0 16.2 0.192 ;
    END
  END o0[69]
  PIN o0[6]
    DIRECTION OUTPUT ;
    USE SIGNAL ;
    PORT
      LAYER M5 ;
        RECT  5.52 0 5.544 0.192 ;
    END
  END o0[6]
  PIN o0[70]
    DIRECTION OUTPUT ;
    USE SIGNAL ;
    PORT
      LAYER M5 ;
        RECT  16.32 0 16.344 0.192 ;
    END
  END o0[70]
  PIN o0[71]
    DIRECTION OUTPUT ;
    USE SIGNAL ;
    PORT
      LAYER M5 ;
        RECT  16.512 0 16.536 0.192 ;
    END
  END o0[71]
  PIN o0[72]
    DIRECTION OUTPUT ;
    USE SIGNAL ;
    PORT
      LAYER M5 ;
        RECT  16.656 0 16.68 0.192 ;
    END
  END o0[72]
  PIN o0[73]
    DIRECTION OUTPUT ;
    USE SIGNAL ;
    PORT
      LAYER M5 ;
        RECT  16.848 0 16.872 0.192 ;
    END
  END o0[73]
  PIN o0[74]
    DIRECTION OUTPUT ;
    USE SIGNAL ;
    PORT
      LAYER M5 ;
        RECT  16.992 0 17.016 0.192 ;
    END
  END o0[74]
  PIN o0[75]
    DIRECTION OUTPUT ;
    USE SIGNAL ;
    PORT
      LAYER M5 ;
        RECT  17.136 0 17.16 0.192 ;
    END
  END o0[75]
  PIN o0[76]
    DIRECTION OUTPUT ;
    USE SIGNAL ;
    PORT
      LAYER M5 ;
        RECT  17.328 0 17.352 0.192 ;
    END
  END o0[76]
  PIN o0[77]
    DIRECTION OUTPUT ;
    USE SIGNAL ;
    PORT
      LAYER M5 ;
        RECT  17.472 0 17.496 0.192 ;
    END
  END o0[77]
  PIN o0[78]
    DIRECTION OUTPUT ;
    USE SIGNAL ;
    PORT
      LAYER M5 ;
        RECT  17.664 0 17.688 0.192 ;
    END
  END o0[78]
  PIN o0[79]
    DIRECTION OUTPUT ;
    USE SIGNAL ;
    PORT
      LAYER M5 ;
        RECT  17.808 0 17.832 0.192 ;
    END
  END o0[79]
  PIN o0[7]
    DIRECTION OUTPUT ;
    USE SIGNAL ;
    PORT
      LAYER M5 ;
        RECT  5.664 0 5.688 0.192 ;
    END
  END o0[7]
  PIN o0[80]
    DIRECTION OUTPUT ;
    USE SIGNAL ;
    PORT
      LAYER M5 ;
        RECT  18 0 18.024 0.192 ;
    END
  END o0[80]
  PIN o0[81]
    DIRECTION OUTPUT ;
    USE SIGNAL ;
    PORT
      LAYER M5 ;
        RECT  18.144 0 18.168 0.192 ;
    END
  END o0[81]
  PIN o0[82]
    DIRECTION OUTPUT ;
    USE SIGNAL ;
    PORT
      LAYER M5 ;
        RECT  18.336 0 18.36 0.192 ;
    END
  END o0[82]
  PIN o0[83]
    DIRECTION OUTPUT ;
    USE SIGNAL ;
    PORT
      LAYER M5 ;
        RECT  18.48 0 18.504 0.192 ;
    END
  END o0[83]
  PIN o0[84]
    DIRECTION OUTPUT ;
    USE SIGNAL ;
    PORT
      LAYER M5 ;
        RECT  18.672 0 18.696 0.192 ;
    END
  END o0[84]
  PIN o0[85]
    DIRECTION OUTPUT ;
    USE SIGNAL ;
    PORT
      LAYER M5 ;
        RECT  18.816 0 18.84 0.192 ;
    END
  END o0[85]
  PIN o0[86]
    DIRECTION OUTPUT ;
    USE SIGNAL ;
    PORT
      LAYER M5 ;
        RECT  19.008 0 19.032 0.192 ;
    END
  END o0[86]
  PIN o0[87]
    DIRECTION OUTPUT ;
    USE SIGNAL ;
    PORT
      LAYER M5 ;
        RECT  19.152 0 19.176 0.192 ;
    END
  END o0[87]
  PIN o0[88]
    DIRECTION OUTPUT ;
    USE SIGNAL ;
    PORT
      LAYER M5 ;
        RECT  19.344 0 19.368 0.192 ;
    END
  END o0[88]
  PIN o0[89]
    DIRECTION OUTPUT ;
    USE SIGNAL ;
    PORT
      LAYER M5 ;
        RECT  19.488 0 19.512 0.192 ;
    END
  END o0[89]
  PIN o0[8]
    DIRECTION OUTPUT ;
    USE SIGNAL ;
    PORT
      LAYER M5 ;
        RECT  5.856 0 5.88 0.192 ;
    END
  END o0[8]
  PIN o0[90]
    DIRECTION OUTPUT ;
    USE SIGNAL ;
    PORT
      LAYER M5 ;
        RECT  19.68 0 19.704 0.192 ;
    END
  END o0[90]
  PIN o0[91]
    DIRECTION OUTPUT ;
    USE SIGNAL ;
    PORT
      LAYER M5 ;
        RECT  19.824 0 19.848 0.192 ;
    END
  END o0[91]
  PIN o0[92]
    DIRECTION OUTPUT ;
    USE SIGNAL ;
    PORT
      LAYER M5 ;
        RECT  19.968 0 19.992 0.192 ;
    END
  END o0[92]
  PIN o0[93]
    DIRECTION OUTPUT ;
    USE SIGNAL ;
    PORT
      LAYER M5 ;
        RECT  20.16 0 20.184 0.192 ;
    END
  END o0[93]
  PIN o0[94]
    DIRECTION OUTPUT ;
    USE SIGNAL ;
    PORT
      LAYER M5 ;
        RECT  20.304 0 20.328 0.192 ;
    END
  END o0[94]
  PIN o0[95]
    DIRECTION OUTPUT ;
    USE SIGNAL ;
    PORT
      LAYER M5 ;
        RECT  20.496 0 20.52 0.192 ;
    END
  END o0[95]
  PIN o0[96]
    DIRECTION OUTPUT ;
    USE SIGNAL ;
    PORT
      LAYER M5 ;
        RECT  20.64 0 20.664 0.192 ;
    END
  END o0[96]
  PIN o0[97]
    DIRECTION OUTPUT ;
    USE SIGNAL ;
    PORT
      LAYER M5 ;
        RECT  20.832 0 20.856 0.192 ;
    END
  END o0[97]
  PIN o0[98]
    DIRECTION OUTPUT ;
    USE SIGNAL ;
    PORT
      LAYER M5 ;
        RECT  20.976 0 21 0.192 ;
    END
  END o0[98]
  PIN o0[99]
    DIRECTION OUTPUT ;
    USE SIGNAL ;
    PORT
      LAYER M5 ;
        RECT  21.168 0 21.192 0.192 ;
    END
  END o0[99]
  PIN o0[9]
    DIRECTION OUTPUT ;
    USE SIGNAL ;
    PORT
      LAYER M5 ;
        RECT  6 0 6.024 0.192 ;
    END
  END o0[9]
  PIN o1[0]
    DIRECTION OUTPUT ;
    USE SIGNAL ;
    PORT
      LAYER M5 ;
        RECT  27.552 0 27.576 0.192 ;
    END
  END o1[0]
  PIN o1[100]
    DIRECTION OUTPUT ;
    USE SIGNAL ;
    PORT
      LAYER M5 ;
        RECT  44.352 0 44.376 0.192 ;
    END
  END o1[100]
  PIN o1[101]
    DIRECTION OUTPUT ;
    USE SIGNAL ;
    PORT
      LAYER M5 ;
        RECT  44.544 0 44.568 0.192 ;
    END
  END o1[101]
  PIN o1[102]
    DIRECTION OUTPUT ;
    USE SIGNAL ;
    PORT
      LAYER M5 ;
        RECT  44.688 0 44.712 0.192 ;
    END
  END o1[102]
  PIN o1[103]
    DIRECTION OUTPUT ;
    USE SIGNAL ;
    PORT
      LAYER M5 ;
        RECT  44.88 0 44.904 0.192 ;
    END
  END o1[103]
  PIN o1[104]
    DIRECTION OUTPUT ;
    USE SIGNAL ;
    PORT
      LAYER M5 ;
        RECT  45.024 0 45.048 0.192 ;
    END
  END o1[104]
  PIN o1[105]
    DIRECTION OUTPUT ;
    USE SIGNAL ;
    PORT
      LAYER M5 ;
        RECT  45.216 0 45.24 0.192 ;
    END
  END o1[105]
  PIN o1[106]
    DIRECTION OUTPUT ;
    USE SIGNAL ;
    PORT
      LAYER M5 ;
        RECT  45.36 0 45.384 0.192 ;
    END
  END o1[106]
  PIN o1[107]
    DIRECTION OUTPUT ;
    USE SIGNAL ;
    PORT
      LAYER M5 ;
        RECT  45.504 0 45.528 0.192 ;
    END
  END o1[107]
  PIN o1[108]
    DIRECTION OUTPUT ;
    USE SIGNAL ;
    PORT
      LAYER M5 ;
        RECT  45.696 0 45.72 0.192 ;
    END
  END o1[108]
  PIN o1[109]
    DIRECTION OUTPUT ;
    USE SIGNAL ;
    PORT
      LAYER M5 ;
        RECT  45.84 0 45.864 0.192 ;
    END
  END o1[109]
  PIN o1[10]
    DIRECTION OUTPUT ;
    USE SIGNAL ;
    PORT
      LAYER M5 ;
        RECT  29.232 0 29.256 0.192 ;
    END
  END o1[10]
  PIN o1[110]
    DIRECTION OUTPUT ;
    USE SIGNAL ;
    PORT
      LAYER M5 ;
        RECT  46.032 0 46.056 0.192 ;
    END
  END o1[110]
  PIN o1[111]
    DIRECTION OUTPUT ;
    USE SIGNAL ;
    PORT
      LAYER M5 ;
        RECT  46.176 0 46.2 0.192 ;
    END
  END o1[111]
  PIN o1[112]
    DIRECTION OUTPUT ;
    USE SIGNAL ;
    PORT
      LAYER M5 ;
        RECT  46.368 0 46.392 0.192 ;
    END
  END o1[112]
  PIN o1[113]
    DIRECTION OUTPUT ;
    USE SIGNAL ;
    PORT
      LAYER M5 ;
        RECT  46.512 0 46.536 0.192 ;
    END
  END o1[113]
  PIN o1[114]
    DIRECTION OUTPUT ;
    USE SIGNAL ;
    PORT
      LAYER M5 ;
        RECT  46.704 0 46.728 0.192 ;
    END
  END o1[114]
  PIN o1[115]
    DIRECTION OUTPUT ;
    USE SIGNAL ;
    PORT
      LAYER M5 ;
        RECT  46.848 0 46.872 0.192 ;
    END
  END o1[115]
  PIN o1[116]
    DIRECTION OUTPUT ;
    USE SIGNAL ;
    PORT
      LAYER M5 ;
        RECT  47.04 0 47.064 0.192 ;
    END
  END o1[116]
  PIN o1[117]
    DIRECTION OUTPUT ;
    USE SIGNAL ;
    PORT
      LAYER M5 ;
        RECT  47.184 0 47.208 0.192 ;
    END
  END o1[117]
  PIN o1[118]
    DIRECTION OUTPUT ;
    USE SIGNAL ;
    PORT
      LAYER M5 ;
        RECT  47.376 0 47.4 0.192 ;
    END
  END o1[118]
  PIN o1[119]
    DIRECTION OUTPUT ;
    USE SIGNAL ;
    PORT
      LAYER M5 ;
        RECT  47.52 0 47.544 0.192 ;
    END
  END o1[119]
  PIN o1[11]
    DIRECTION OUTPUT ;
    USE SIGNAL ;
    PORT
      LAYER M5 ;
        RECT  29.376 0 29.4 0.192 ;
    END
  END o1[11]
  PIN o1[120]
    DIRECTION OUTPUT ;
    USE SIGNAL ;
    PORT
      LAYER M5 ;
        RECT  47.712 0 47.736 0.192 ;
    END
  END o1[120]
  PIN o1[121]
    DIRECTION OUTPUT ;
    USE SIGNAL ;
    PORT
      LAYER M5 ;
        RECT  47.856 0 47.88 0.192 ;
    END
  END o1[121]
  PIN o1[122]
    DIRECTION OUTPUT ;
    USE SIGNAL ;
    PORT
      LAYER M5 ;
        RECT  48 0 48.024 0.192 ;
    END
  END o1[122]
  PIN o1[123]
    DIRECTION OUTPUT ;
    USE SIGNAL ;
    PORT
      LAYER M5 ;
        RECT  48.192 0 48.216 0.192 ;
    END
  END o1[123]
  PIN o1[124]
    DIRECTION OUTPUT ;
    USE SIGNAL ;
    PORT
      LAYER M5 ;
        RECT  48.336 0 48.36 0.192 ;
    END
  END o1[124]
  PIN o1[125]
    DIRECTION OUTPUT ;
    USE SIGNAL ;
    PORT
      LAYER M5 ;
        RECT  48.528 0 48.552 0.192 ;
    END
  END o1[125]
  PIN o1[126]
    DIRECTION OUTPUT ;
    USE SIGNAL ;
    PORT
      LAYER M5 ;
        RECT  48.672 0 48.696 0.192 ;
    END
  END o1[126]
  PIN o1[127]
    DIRECTION OUTPUT ;
    USE SIGNAL ;
    PORT
      LAYER M5 ;
        RECT  48.864 0 48.888 0.192 ;
    END
  END o1[127]
  PIN o1[128]
    DIRECTION OUTPUT ;
    USE SIGNAL ;
    PORT
      LAYER M5 ;
        RECT  49.008 0 49.032 0.192 ;
    END
  END o1[128]
  PIN o1[129]
    DIRECTION OUTPUT ;
    USE SIGNAL ;
    PORT
      LAYER M5 ;
        RECT  49.2 0 49.224 0.192 ;
    END
  END o1[129]
  PIN o1[12]
    DIRECTION OUTPUT ;
    USE SIGNAL ;
    PORT
      LAYER M5 ;
        RECT  29.568 0 29.592 0.192 ;
    END
  END o1[12]
  PIN o1[130]
    DIRECTION OUTPUT ;
    USE SIGNAL ;
    PORT
      LAYER M5 ;
        RECT  49.344 0 49.368 0.192 ;
    END
  END o1[130]
  PIN o1[131]
    DIRECTION OUTPUT ;
    USE SIGNAL ;
    PORT
      LAYER M5 ;
        RECT  49.536 0 49.56 0.192 ;
    END
  END o1[131]
  PIN o1[132]
    DIRECTION OUTPUT ;
    USE SIGNAL ;
    PORT
      LAYER M5 ;
        RECT  49.68 0 49.704 0.192 ;
    END
  END o1[132]
  PIN o1[133]
    DIRECTION OUTPUT ;
    USE SIGNAL ;
    PORT
      LAYER M5 ;
        RECT  49.872 0 49.896 0.192 ;
    END
  END o1[133]
  PIN o1[134]
    DIRECTION OUTPUT ;
    USE SIGNAL ;
    PORT
      LAYER M5 ;
        RECT  50.016 0 50.04 0.192 ;
    END
  END o1[134]
  PIN o1[135]
    DIRECTION OUTPUT ;
    USE SIGNAL ;
    PORT
      LAYER M5 ;
        RECT  50.208 0 50.232 0.192 ;
    END
  END o1[135]
  PIN o1[13]
    DIRECTION OUTPUT ;
    USE SIGNAL ;
    PORT
      LAYER M5 ;
        RECT  29.712 0 29.736 0.192 ;
    END
  END o1[13]
  PIN o1[14]
    DIRECTION OUTPUT ;
    USE SIGNAL ;
    PORT
      LAYER M5 ;
        RECT  29.856 0 29.88 0.192 ;
    END
  END o1[14]
  PIN o1[15]
    DIRECTION OUTPUT ;
    USE SIGNAL ;
    PORT
      LAYER M5 ;
        RECT  30.048 0 30.072 0.192 ;
    END
  END o1[15]
  PIN o1[16]
    DIRECTION OUTPUT ;
    USE SIGNAL ;
    PORT
      LAYER M5 ;
        RECT  30.192 0 30.216 0.192 ;
    END
  END o1[16]
  PIN o1[17]
    DIRECTION OUTPUT ;
    USE SIGNAL ;
    PORT
      LAYER M5 ;
        RECT  30.384 0 30.408 0.192 ;
    END
  END o1[17]
  PIN o1[18]
    DIRECTION OUTPUT ;
    USE SIGNAL ;
    PORT
      LAYER M5 ;
        RECT  30.528 0 30.552 0.192 ;
    END
  END o1[18]
  PIN o1[19]
    DIRECTION OUTPUT ;
    USE SIGNAL ;
    PORT
      LAYER M5 ;
        RECT  30.72 0 30.744 0.192 ;
    END
  END o1[19]
  PIN o1[1]
    DIRECTION OUTPUT ;
    USE SIGNAL ;
    PORT
      LAYER M5 ;
        RECT  27.696 0 27.72 0.192 ;
    END
  END o1[1]
  PIN o1[20]
    DIRECTION OUTPUT ;
    USE SIGNAL ;
    PORT
      LAYER M5 ;
        RECT  30.864 0 30.888 0.192 ;
    END
  END o1[20]
  PIN o1[21]
    DIRECTION OUTPUT ;
    USE SIGNAL ;
    PORT
      LAYER M5 ;
        RECT  31.056 0 31.08 0.192 ;
    END
  END o1[21]
  PIN o1[22]
    DIRECTION OUTPUT ;
    USE SIGNAL ;
    PORT
      LAYER M5 ;
        RECT  31.2 0 31.224 0.192 ;
    END
  END o1[22]
  PIN o1[23]
    DIRECTION OUTPUT ;
    USE SIGNAL ;
    PORT
      LAYER M5 ;
        RECT  31.392 0 31.416 0.192 ;
    END
  END o1[23]
  PIN o1[24]
    DIRECTION OUTPUT ;
    USE SIGNAL ;
    PORT
      LAYER M5 ;
        RECT  31.536 0 31.56 0.192 ;
    END
  END o1[24]
  PIN o1[25]
    DIRECTION OUTPUT ;
    USE SIGNAL ;
    PORT
      LAYER M5 ;
        RECT  31.728 0 31.752 0.192 ;
    END
  END o1[25]
  PIN o1[26]
    DIRECTION OUTPUT ;
    USE SIGNAL ;
    PORT
      LAYER M5 ;
        RECT  31.872 0 31.896 0.192 ;
    END
  END o1[26]
  PIN o1[27]
    DIRECTION OUTPUT ;
    USE SIGNAL ;
    PORT
      LAYER M5 ;
        RECT  32.064 0 32.088 0.192 ;
    END
  END o1[27]
  PIN o1[28]
    DIRECTION OUTPUT ;
    USE SIGNAL ;
    PORT
      LAYER M5 ;
        RECT  32.208 0 32.232 0.192 ;
    END
  END o1[28]
  PIN o1[29]
    DIRECTION OUTPUT ;
    USE SIGNAL ;
    PORT
      LAYER M5 ;
        RECT  32.352 0 32.376 0.192 ;
    END
  END o1[29]
  PIN o1[2]
    DIRECTION OUTPUT ;
    USE SIGNAL ;
    PORT
      LAYER M5 ;
        RECT  27.888 0 27.912 0.192 ;
    END
  END o1[2]
  PIN o1[30]
    DIRECTION OUTPUT ;
    USE SIGNAL ;
    PORT
      LAYER M5 ;
        RECT  32.544 0 32.568 0.192 ;
    END
  END o1[30]
  PIN o1[31]
    DIRECTION OUTPUT ;
    USE SIGNAL ;
    PORT
      LAYER M5 ;
        RECT  32.688 0 32.712 0.192 ;
    END
  END o1[31]
  PIN o1[32]
    DIRECTION OUTPUT ;
    USE SIGNAL ;
    PORT
      LAYER M5 ;
        RECT  32.88 0 32.904 0.192 ;
    END
  END o1[32]
  PIN o1[33]
    DIRECTION OUTPUT ;
    USE SIGNAL ;
    PORT
      LAYER M5 ;
        RECT  33.024 0 33.048 0.192 ;
    END
  END o1[33]
  PIN o1[34]
    DIRECTION OUTPUT ;
    USE SIGNAL ;
    PORT
      LAYER M5 ;
        RECT  33.216 0 33.24 0.192 ;
    END
  END o1[34]
  PIN o1[35]
    DIRECTION OUTPUT ;
    USE SIGNAL ;
    PORT
      LAYER M5 ;
        RECT  33.36 0 33.384 0.192 ;
    END
  END o1[35]
  PIN o1[36]
    DIRECTION OUTPUT ;
    USE SIGNAL ;
    PORT
      LAYER M5 ;
        RECT  33.552 0 33.576 0.192 ;
    END
  END o1[36]
  PIN o1[37]
    DIRECTION OUTPUT ;
    USE SIGNAL ;
    PORT
      LAYER M5 ;
        RECT  33.696 0 33.72 0.192 ;
    END
  END o1[37]
  PIN o1[38]
    DIRECTION OUTPUT ;
    USE SIGNAL ;
    PORT
      LAYER M5 ;
        RECT  33.888 0 33.912 0.192 ;
    END
  END o1[38]
  PIN o1[39]
    DIRECTION OUTPUT ;
    USE SIGNAL ;
    PORT
      LAYER M5 ;
        RECT  34.032 0 34.056 0.192 ;
    END
  END o1[39]
  PIN o1[3]
    DIRECTION OUTPUT ;
    USE SIGNAL ;
    PORT
      LAYER M5 ;
        RECT  28.032 0 28.056 0.192 ;
    END
  END o1[3]
  PIN o1[40]
    DIRECTION OUTPUT ;
    USE SIGNAL ;
    PORT
      LAYER M5 ;
        RECT  34.224 0 34.248 0.192 ;
    END
  END o1[40]
  PIN o1[41]
    DIRECTION OUTPUT ;
    USE SIGNAL ;
    PORT
      LAYER M5 ;
        RECT  34.368 0 34.392 0.192 ;
    END
  END o1[41]
  PIN o1[42]
    DIRECTION OUTPUT ;
    USE SIGNAL ;
    PORT
      LAYER M5 ;
        RECT  34.56 0 34.584 0.192 ;
    END
  END o1[42]
  PIN o1[43]
    DIRECTION OUTPUT ;
    USE SIGNAL ;
    PORT
      LAYER M5 ;
        RECT  34.704 0 34.728 0.192 ;
    END
  END o1[43]
  PIN o1[44]
    DIRECTION OUTPUT ;
    USE SIGNAL ;
    PORT
      LAYER M5 ;
        RECT  34.896 0 34.92 0.192 ;
    END
  END o1[44]
  PIN o1[45]
    DIRECTION OUTPUT ;
    USE SIGNAL ;
    PORT
      LAYER M5 ;
        RECT  35.04 0 35.064 0.192 ;
    END
  END o1[45]
  PIN o1[46]
    DIRECTION OUTPUT ;
    USE SIGNAL ;
    PORT
      LAYER M5 ;
        RECT  35.184 0 35.208 0.192 ;
    END
  END o1[46]
  PIN o1[47]
    DIRECTION OUTPUT ;
    USE SIGNAL ;
    PORT
      LAYER M5 ;
        RECT  35.376 0 35.4 0.192 ;
    END
  END o1[47]
  PIN o1[48]
    DIRECTION OUTPUT ;
    USE SIGNAL ;
    PORT
      LAYER M5 ;
        RECT  35.52 0 35.544 0.192 ;
    END
  END o1[48]
  PIN o1[49]
    DIRECTION OUTPUT ;
    USE SIGNAL ;
    PORT
      LAYER M5 ;
        RECT  35.712 0 35.736 0.192 ;
    END
  END o1[49]
  PIN o1[4]
    DIRECTION OUTPUT ;
    USE SIGNAL ;
    PORT
      LAYER M5 ;
        RECT  28.224 0 28.248 0.192 ;
    END
  END o1[4]
  PIN o1[50]
    DIRECTION OUTPUT ;
    USE SIGNAL ;
    PORT
      LAYER M5 ;
        RECT  35.856 0 35.88 0.192 ;
    END
  END o1[50]
  PIN o1[51]
    DIRECTION OUTPUT ;
    USE SIGNAL ;
    PORT
      LAYER M5 ;
        RECT  36.048 0 36.072 0.192 ;
    END
  END o1[51]
  PIN o1[52]
    DIRECTION OUTPUT ;
    USE SIGNAL ;
    PORT
      LAYER M5 ;
        RECT  36.192 0 36.216 0.192 ;
    END
  END o1[52]
  PIN o1[53]
    DIRECTION OUTPUT ;
    USE SIGNAL ;
    PORT
      LAYER M5 ;
        RECT  36.384 0 36.408 0.192 ;
    END
  END o1[53]
  PIN o1[54]
    DIRECTION OUTPUT ;
    USE SIGNAL ;
    PORT
      LAYER M5 ;
        RECT  36.528 0 36.552 0.192 ;
    END
  END o1[54]
  PIN o1[55]
    DIRECTION OUTPUT ;
    USE SIGNAL ;
    PORT
      LAYER M5 ;
        RECT  36.72 0 36.744 0.192 ;
    END
  END o1[55]
  PIN o1[56]
    DIRECTION OUTPUT ;
    USE SIGNAL ;
    PORT
      LAYER M5 ;
        RECT  36.864 0 36.888 0.192 ;
    END
  END o1[56]
  PIN o1[57]
    DIRECTION OUTPUT ;
    USE SIGNAL ;
    PORT
      LAYER M5 ;
        RECT  37.056 0 37.08 0.192 ;
    END
  END o1[57]
  PIN o1[58]
    DIRECTION OUTPUT ;
    USE SIGNAL ;
    PORT
      LAYER M5 ;
        RECT  37.2 0 37.224 0.192 ;
    END
  END o1[58]
  PIN o1[59]
    DIRECTION OUTPUT ;
    USE SIGNAL ;
    PORT
      LAYER M5 ;
        RECT  37.392 0 37.416 0.192 ;
    END
  END o1[59]
  PIN o1[5]
    DIRECTION OUTPUT ;
    USE SIGNAL ;
    PORT
      LAYER M5 ;
        RECT  28.368 0 28.392 0.192 ;
    END
  END o1[5]
  PIN o1[60]
    DIRECTION OUTPUT ;
    USE SIGNAL ;
    PORT
      LAYER M5 ;
        RECT  37.536 0 37.56 0.192 ;
    END
  END o1[60]
  PIN o1[61]
    DIRECTION OUTPUT ;
    USE SIGNAL ;
    PORT
      LAYER M5 ;
        RECT  37.68 0 37.704 0.192 ;
    END
  END o1[61]
  PIN o1[62]
    DIRECTION OUTPUT ;
    USE SIGNAL ;
    PORT
      LAYER M5 ;
        RECT  37.872 0 37.896 0.192 ;
    END
  END o1[62]
  PIN o1[63]
    DIRECTION OUTPUT ;
    USE SIGNAL ;
    PORT
      LAYER M5 ;
        RECT  38.016 0 38.04 0.192 ;
    END
  END o1[63]
  PIN o1[64]
    DIRECTION OUTPUT ;
    USE SIGNAL ;
    PORT
      LAYER M5 ;
        RECT  38.208 0 38.232 0.192 ;
    END
  END o1[64]
  PIN o1[65]
    DIRECTION OUTPUT ;
    USE SIGNAL ;
    PORT
      LAYER M5 ;
        RECT  38.352 0 38.376 0.192 ;
    END
  END o1[65]
  PIN o1[66]
    DIRECTION OUTPUT ;
    USE SIGNAL ;
    PORT
      LAYER M5 ;
        RECT  38.544 0 38.568 0.192 ;
    END
  END o1[66]
  PIN o1[67]
    DIRECTION OUTPUT ;
    USE SIGNAL ;
    PORT
      LAYER M5 ;
        RECT  38.688 0 38.712 0.192 ;
    END
  END o1[67]
  PIN o1[68]
    DIRECTION OUTPUT ;
    USE SIGNAL ;
    PORT
      LAYER M5 ;
        RECT  39.024 0 39.048 0.192 ;
    END
  END o1[68]
  PIN o1[69]
    DIRECTION OUTPUT ;
    USE SIGNAL ;
    PORT
      LAYER M5 ;
        RECT  39.216 0 39.24 0.192 ;
    END
  END o1[69]
  PIN o1[6]
    DIRECTION OUTPUT ;
    USE SIGNAL ;
    PORT
      LAYER M5 ;
        RECT  28.56 0 28.584 0.192 ;
    END
  END o1[6]
  PIN o1[70]
    DIRECTION OUTPUT ;
    USE SIGNAL ;
    PORT
      LAYER M5 ;
        RECT  39.36 0 39.384 0.192 ;
    END
  END o1[70]
  PIN o1[71]
    DIRECTION OUTPUT ;
    USE SIGNAL ;
    PORT
      LAYER M5 ;
        RECT  39.552 0 39.576 0.192 ;
    END
  END o1[71]
  PIN o1[72]
    DIRECTION OUTPUT ;
    USE SIGNAL ;
    PORT
      LAYER M5 ;
        RECT  39.696 0 39.72 0.192 ;
    END
  END o1[72]
  PIN o1[73]
    DIRECTION OUTPUT ;
    USE SIGNAL ;
    PORT
      LAYER M5 ;
        RECT  39.888 0 39.912 0.192 ;
    END
  END o1[73]
  PIN o1[74]
    DIRECTION OUTPUT ;
    USE SIGNAL ;
    PORT
      LAYER M5 ;
        RECT  40.032 0 40.056 0.192 ;
    END
  END o1[74]
  PIN o1[75]
    DIRECTION OUTPUT ;
    USE SIGNAL ;
    PORT
      LAYER M5 ;
        RECT  40.176 0 40.2 0.192 ;
    END
  END o1[75]
  PIN o1[76]
    DIRECTION OUTPUT ;
    USE SIGNAL ;
    PORT
      LAYER M5 ;
        RECT  40.368 0 40.392 0.192 ;
    END
  END o1[76]
  PIN o1[77]
    DIRECTION OUTPUT ;
    USE SIGNAL ;
    PORT
      LAYER M5 ;
        RECT  40.512 0 40.536 0.192 ;
    END
  END o1[77]
  PIN o1[78]
    DIRECTION OUTPUT ;
    USE SIGNAL ;
    PORT
      LAYER M5 ;
        RECT  40.704 0 40.728 0.192 ;
    END
  END o1[78]
  PIN o1[79]
    DIRECTION OUTPUT ;
    USE SIGNAL ;
    PORT
      LAYER M5 ;
        RECT  40.848 0 40.872 0.192 ;
    END
  END o1[79]
  PIN o1[7]
    DIRECTION OUTPUT ;
    USE SIGNAL ;
    PORT
      LAYER M5 ;
        RECT  28.704 0 28.728 0.192 ;
    END
  END o1[7]
  PIN o1[80]
    DIRECTION OUTPUT ;
    USE SIGNAL ;
    PORT
      LAYER M5 ;
        RECT  41.04 0 41.064 0.192 ;
    END
  END o1[80]
  PIN o1[81]
    DIRECTION OUTPUT ;
    USE SIGNAL ;
    PORT
      LAYER M5 ;
        RECT  41.184 0 41.208 0.192 ;
    END
  END o1[81]
  PIN o1[82]
    DIRECTION OUTPUT ;
    USE SIGNAL ;
    PORT
      LAYER M5 ;
        RECT  41.376 0 41.4 0.192 ;
    END
  END o1[82]
  PIN o1[83]
    DIRECTION OUTPUT ;
    USE SIGNAL ;
    PORT
      LAYER M5 ;
        RECT  41.52 0 41.544 0.192 ;
    END
  END o1[83]
  PIN o1[84]
    DIRECTION OUTPUT ;
    USE SIGNAL ;
    PORT
      LAYER M5 ;
        RECT  41.712 0 41.736 0.192 ;
    END
  END o1[84]
  PIN o1[85]
    DIRECTION OUTPUT ;
    USE SIGNAL ;
    PORT
      LAYER M5 ;
        RECT  41.856 0 41.88 0.192 ;
    END
  END o1[85]
  PIN o1[86]
    DIRECTION OUTPUT ;
    USE SIGNAL ;
    PORT
      LAYER M5 ;
        RECT  42.048 0 42.072 0.192 ;
    END
  END o1[86]
  PIN o1[87]
    DIRECTION OUTPUT ;
    USE SIGNAL ;
    PORT
      LAYER M5 ;
        RECT  42.192 0 42.216 0.192 ;
    END
  END o1[87]
  PIN o1[88]
    DIRECTION OUTPUT ;
    USE SIGNAL ;
    PORT
      LAYER M5 ;
        RECT  42.384 0 42.408 0.192 ;
    END
  END o1[88]
  PIN o1[89]
    DIRECTION OUTPUT ;
    USE SIGNAL ;
    PORT
      LAYER M5 ;
        RECT  42.528 0 42.552 0.192 ;
    END
  END o1[89]
  PIN o1[8]
    DIRECTION OUTPUT ;
    USE SIGNAL ;
    PORT
      LAYER M5 ;
        RECT  28.896 0 28.92 0.192 ;
    END
  END o1[8]
  PIN o1[90]
    DIRECTION OUTPUT ;
    USE SIGNAL ;
    PORT
      LAYER M5 ;
        RECT  42.72 0 42.744 0.192 ;
    END
  END o1[90]
  PIN o1[91]
    DIRECTION OUTPUT ;
    USE SIGNAL ;
    PORT
      LAYER M5 ;
        RECT  42.864 0 42.888 0.192 ;
    END
  END o1[91]
  PIN o1[92]
    DIRECTION OUTPUT ;
    USE SIGNAL ;
    PORT
      LAYER M5 ;
        RECT  43.008 0 43.032 0.192 ;
    END
  END o1[92]
  PIN o1[93]
    DIRECTION OUTPUT ;
    USE SIGNAL ;
    PORT
      LAYER M5 ;
        RECT  43.2 0 43.224 0.192 ;
    END
  END o1[93]
  PIN o1[94]
    DIRECTION OUTPUT ;
    USE SIGNAL ;
    PORT
      LAYER M5 ;
        RECT  43.344 0 43.368 0.192 ;
    END
  END o1[94]
  PIN o1[95]
    DIRECTION OUTPUT ;
    USE SIGNAL ;
    PORT
      LAYER M5 ;
        RECT  43.536 0 43.56 0.192 ;
    END
  END o1[95]
  PIN o1[96]
    DIRECTION OUTPUT ;
    USE SIGNAL ;
    PORT
      LAYER M5 ;
        RECT  43.68 0 43.704 0.192 ;
    END
  END o1[96]
  PIN o1[97]
    DIRECTION OUTPUT ;
    USE SIGNAL ;
    PORT
      LAYER M5 ;
        RECT  43.872 0 43.896 0.192 ;
    END
  END o1[97]
  PIN o1[98]
    DIRECTION OUTPUT ;
    USE SIGNAL ;
    PORT
      LAYER M5 ;
        RECT  44.016 0 44.04 0.192 ;
    END
  END o1[98]
  PIN o1[99]
    DIRECTION OUTPUT ;
    USE SIGNAL ;
    PORT
      LAYER M5 ;
        RECT  44.208 0 44.232 0.192 ;
    END
  END o1[99]
  PIN o1[9]
    DIRECTION OUTPUT ;
    USE SIGNAL ;
    PORT
      LAYER M5 ;
        RECT  29.04 0 29.064 0.192 ;
    END
  END o1[9]
  PIN o2[0]
    DIRECTION OUTPUT ;
    USE SIGNAL ;
    PORT
      LAYER M5 ;
        RECT  39.072 21.408 39.096 21.6 ;
    END
  END o2[0]
  PIN o2[100]
    DIRECTION OUTPUT ;
    USE SIGNAL ;
    PORT
      LAYER M5 ;
        RECT  64.416 21.408 64.44 21.6 ;
    END
  END o2[100]
  PIN o2[101]
    DIRECTION OUTPUT ;
    USE SIGNAL ;
    PORT
      LAYER M5 ;
        RECT  64.704 21.408 64.728 21.6 ;
    END
  END o2[101]
  PIN o2[102]
    DIRECTION OUTPUT ;
    USE SIGNAL ;
    PORT
      LAYER M5 ;
        RECT  64.944 21.408 64.968 21.6 ;
    END
  END o2[102]
  PIN o2[103]
    DIRECTION OUTPUT ;
    USE SIGNAL ;
    PORT
      LAYER M5 ;
        RECT  65.184 21.408 65.208 21.6 ;
    END
  END o2[103]
  PIN o2[104]
    DIRECTION OUTPUT ;
    USE SIGNAL ;
    PORT
      LAYER M5 ;
        RECT  65.424 21.408 65.448 21.6 ;
    END
  END o2[104]
  PIN o2[105]
    DIRECTION OUTPUT ;
    USE SIGNAL ;
    PORT
      LAYER M5 ;
        RECT  65.712 21.408 65.736 21.6 ;
    END
  END o2[105]
  PIN o2[106]
    DIRECTION OUTPUT ;
    USE SIGNAL ;
    PORT
      LAYER M5 ;
        RECT  65.952 21.408 65.976 21.6 ;
    END
  END o2[106]
  PIN o2[107]
    DIRECTION OUTPUT ;
    USE SIGNAL ;
    PORT
      LAYER M5 ;
        RECT  66.192 21.408 66.216 21.6 ;
    END
  END o2[107]
  PIN o2[108]
    DIRECTION OUTPUT ;
    USE SIGNAL ;
    PORT
      LAYER M5 ;
        RECT  66.432 21.408 66.456 21.6 ;
    END
  END o2[108]
  PIN o2[109]
    DIRECTION OUTPUT ;
    USE SIGNAL ;
    PORT
      LAYER M5 ;
        RECT  66.72 21.408 66.744 21.6 ;
    END
  END o2[109]
  PIN o2[10]
    DIRECTION OUTPUT ;
    USE SIGNAL ;
    PORT
      LAYER M5 ;
        RECT  41.568 21.408 41.592 21.6 ;
    END
  END o2[10]
  PIN o2[110]
    DIRECTION OUTPUT ;
    USE SIGNAL ;
    PORT
      LAYER M5 ;
        RECT  66.96 21.408 66.984 21.6 ;
    END
  END o2[110]
  PIN o2[111]
    DIRECTION OUTPUT ;
    USE SIGNAL ;
    PORT
      LAYER M5 ;
        RECT  67.2 21.408 67.224 21.6 ;
    END
  END o2[111]
  PIN o2[112]
    DIRECTION OUTPUT ;
    USE SIGNAL ;
    PORT
      LAYER M5 ;
        RECT  67.44 21.408 67.464 21.6 ;
    END
  END o2[112]
  PIN o2[113]
    DIRECTION OUTPUT ;
    USE SIGNAL ;
    PORT
      LAYER M5 ;
        RECT  67.68 21.408 67.704 21.6 ;
    END
  END o2[113]
  PIN o2[114]
    DIRECTION OUTPUT ;
    USE SIGNAL ;
    PORT
      LAYER M5 ;
        RECT  67.968 21.408 67.992 21.6 ;
    END
  END o2[114]
  PIN o2[115]
    DIRECTION OUTPUT ;
    USE SIGNAL ;
    PORT
      LAYER M5 ;
        RECT  68.208 21.408 68.232 21.6 ;
    END
  END o2[115]
  PIN o2[116]
    DIRECTION OUTPUT ;
    USE SIGNAL ;
    PORT
      LAYER M5 ;
        RECT  68.448 21.408 68.472 21.6 ;
    END
  END o2[116]
  PIN o2[117]
    DIRECTION OUTPUT ;
    USE SIGNAL ;
    PORT
      LAYER M5 ;
        RECT  68.688 21.408 68.712 21.6 ;
    END
  END o2[117]
  PIN o2[118]
    DIRECTION OUTPUT ;
    USE SIGNAL ;
    PORT
      LAYER M5 ;
        RECT  68.976 21.408 69 21.6 ;
    END
  END o2[118]
  PIN o2[119]
    DIRECTION OUTPUT ;
    USE SIGNAL ;
    PORT
      LAYER M5 ;
        RECT  69.216 21.408 69.24 21.6 ;
    END
  END o2[119]
  PIN o2[11]
    DIRECTION OUTPUT ;
    USE SIGNAL ;
    PORT
      LAYER M5 ;
        RECT  41.808 21.408 41.832 21.6 ;
    END
  END o2[11]
  PIN o2[120]
    DIRECTION OUTPUT ;
    USE SIGNAL ;
    PORT
      LAYER M5 ;
        RECT  69.456 21.408 69.48 21.6 ;
    END
  END o2[120]
  PIN o2[121]
    DIRECTION OUTPUT ;
    USE SIGNAL ;
    PORT
      LAYER M5 ;
        RECT  69.696 21.408 69.72 21.6 ;
    END
  END o2[121]
  PIN o2[122]
    DIRECTION OUTPUT ;
    USE SIGNAL ;
    PORT
      LAYER M5 ;
        RECT  69.984 21.408 70.008 21.6 ;
    END
  END o2[122]
  PIN o2[123]
    DIRECTION OUTPUT ;
    USE SIGNAL ;
    PORT
      LAYER M5 ;
        RECT  70.224 21.408 70.248 21.6 ;
    END
  END o2[123]
  PIN o2[124]
    DIRECTION OUTPUT ;
    USE SIGNAL ;
    PORT
      LAYER M5 ;
        RECT  70.464 21.408 70.488 21.6 ;
    END
  END o2[124]
  PIN o2[125]
    DIRECTION OUTPUT ;
    USE SIGNAL ;
    PORT
      LAYER M5 ;
        RECT  70.704 21.408 70.728 21.6 ;
    END
  END o2[125]
  PIN o2[126]
    DIRECTION OUTPUT ;
    USE SIGNAL ;
    PORT
      LAYER M5 ;
        RECT  70.944 21.408 70.968 21.6 ;
    END
  END o2[126]
  PIN o2[127]
    DIRECTION OUTPUT ;
    USE SIGNAL ;
    PORT
      LAYER M5 ;
        RECT  71.232 21.408 71.256 21.6 ;
    END
  END o2[127]
  PIN o2[128]
    DIRECTION OUTPUT ;
    USE SIGNAL ;
    PORT
      LAYER M5 ;
        RECT  71.472 21.408 71.496 21.6 ;
    END
  END o2[128]
  PIN o2[129]
    DIRECTION OUTPUT ;
    USE SIGNAL ;
    PORT
      LAYER M5 ;
        RECT  71.712 21.408 71.736 21.6 ;
    END
  END o2[129]
  PIN o2[12]
    DIRECTION OUTPUT ;
    USE SIGNAL ;
    PORT
      LAYER M5 ;
        RECT  42.096 21.408 42.12 21.6 ;
    END
  END o2[12]
  PIN o2[130]
    DIRECTION OUTPUT ;
    USE SIGNAL ;
    PORT
      LAYER M5 ;
        RECT  71.952 21.408 71.976 21.6 ;
    END
  END o2[130]
  PIN o2[131]
    DIRECTION OUTPUT ;
    USE SIGNAL ;
    PORT
      LAYER M5 ;
        RECT  72.24 21.408 72.264 21.6 ;
    END
  END o2[131]
  PIN o2[132]
    DIRECTION OUTPUT ;
    USE SIGNAL ;
    PORT
      LAYER M5 ;
        RECT  72.48 21.408 72.504 21.6 ;
    END
  END o2[132]
  PIN o2[133]
    DIRECTION OUTPUT ;
    USE SIGNAL ;
    PORT
      LAYER M5 ;
        RECT  72.72 21.408 72.744 21.6 ;
    END
  END o2[133]
  PIN o2[134]
    DIRECTION OUTPUT ;
    USE SIGNAL ;
    PORT
      LAYER M5 ;
        RECT  72.96 21.408 72.984 21.6 ;
    END
  END o2[134]
  PIN o2[135]
    DIRECTION OUTPUT ;
    USE SIGNAL ;
    PORT
      LAYER M5 ;
        RECT  73.248 21.408 73.272 21.6 ;
    END
  END o2[135]
  PIN o2[13]
    DIRECTION OUTPUT ;
    USE SIGNAL ;
    PORT
      LAYER M5 ;
        RECT  42.336 21.408 42.36 21.6 ;
    END
  END o2[13]
  PIN o2[14]
    DIRECTION OUTPUT ;
    USE SIGNAL ;
    PORT
      LAYER M5 ;
        RECT  42.576 21.408 42.6 21.6 ;
    END
  END o2[14]
  PIN o2[15]
    DIRECTION OUTPUT ;
    USE SIGNAL ;
    PORT
      LAYER M5 ;
        RECT  42.816 21.408 42.84 21.6 ;
    END
  END o2[15]
  PIN o2[16]
    DIRECTION OUTPUT ;
    USE SIGNAL ;
    PORT
      LAYER M5 ;
        RECT  43.104 21.408 43.128 21.6 ;
    END
  END o2[16]
  PIN o2[17]
    DIRECTION OUTPUT ;
    USE SIGNAL ;
    PORT
      LAYER M5 ;
        RECT  43.344 21.408 43.368 21.6 ;
    END
  END o2[17]
  PIN o2[18]
    DIRECTION OUTPUT ;
    USE SIGNAL ;
    PORT
      LAYER M5 ;
        RECT  43.584 21.408 43.608 21.6 ;
    END
  END o2[18]
  PIN o2[19]
    DIRECTION OUTPUT ;
    USE SIGNAL ;
    PORT
      LAYER M5 ;
        RECT  43.824 21.408 43.848 21.6 ;
    END
  END o2[19]
  PIN o2[1]
    DIRECTION OUTPUT ;
    USE SIGNAL ;
    PORT
      LAYER M5 ;
        RECT  39.312 21.408 39.336 21.6 ;
    END
  END o2[1]
  PIN o2[20]
    DIRECTION OUTPUT ;
    USE SIGNAL ;
    PORT
      LAYER M5 ;
        RECT  44.112 21.408 44.136 21.6 ;
    END
  END o2[20]
  PIN o2[21]
    DIRECTION OUTPUT ;
    USE SIGNAL ;
    PORT
      LAYER M5 ;
        RECT  44.352 21.408 44.376 21.6 ;
    END
  END o2[21]
  PIN o2[22]
    DIRECTION OUTPUT ;
    USE SIGNAL ;
    PORT
      LAYER M5 ;
        RECT  44.592 21.408 44.616 21.6 ;
    END
  END o2[22]
  PIN o2[23]
    DIRECTION OUTPUT ;
    USE SIGNAL ;
    PORT
      LAYER M5 ;
        RECT  44.832 21.408 44.856 21.6 ;
    END
  END o2[23]
  PIN o2[24]
    DIRECTION OUTPUT ;
    USE SIGNAL ;
    PORT
      LAYER M5 ;
        RECT  45.12 21.408 45.144 21.6 ;
    END
  END o2[24]
  PIN o2[25]
    DIRECTION OUTPUT ;
    USE SIGNAL ;
    PORT
      LAYER M5 ;
        RECT  45.36 21.408 45.384 21.6 ;
    END
  END o2[25]
  PIN o2[26]
    DIRECTION OUTPUT ;
    USE SIGNAL ;
    PORT
      LAYER M5 ;
        RECT  45.6 21.408 45.624 21.6 ;
    END
  END o2[26]
  PIN o2[27]
    DIRECTION OUTPUT ;
    USE SIGNAL ;
    PORT
      LAYER M5 ;
        RECT  45.84 21.408 45.864 21.6 ;
    END
  END o2[27]
  PIN o2[28]
    DIRECTION OUTPUT ;
    USE SIGNAL ;
    PORT
      LAYER M5 ;
        RECT  46.08 21.408 46.104 21.6 ;
    END
  END o2[28]
  PIN o2[29]
    DIRECTION OUTPUT ;
    USE SIGNAL ;
    PORT
      LAYER M5 ;
        RECT  46.368 21.408 46.392 21.6 ;
    END
  END o2[29]
  PIN o2[2]
    DIRECTION OUTPUT ;
    USE SIGNAL ;
    PORT
      LAYER M5 ;
        RECT  39.552 21.408 39.576 21.6 ;
    END
  END o2[2]
  PIN o2[30]
    DIRECTION OUTPUT ;
    USE SIGNAL ;
    PORT
      LAYER M5 ;
        RECT  46.608 21.408 46.632 21.6 ;
    END
  END o2[30]
  PIN o2[31]
    DIRECTION OUTPUT ;
    USE SIGNAL ;
    PORT
      LAYER M5 ;
        RECT  46.848 21.408 46.872 21.6 ;
    END
  END o2[31]
  PIN o2[32]
    DIRECTION OUTPUT ;
    USE SIGNAL ;
    PORT
      LAYER M5 ;
        RECT  47.088 21.408 47.112 21.6 ;
    END
  END o2[32]
  PIN o2[33]
    DIRECTION OUTPUT ;
    USE SIGNAL ;
    PORT
      LAYER M5 ;
        RECT  47.376 21.408 47.4 21.6 ;
    END
  END o2[33]
  PIN o2[34]
    DIRECTION OUTPUT ;
    USE SIGNAL ;
    PORT
      LAYER M5 ;
        RECT  47.616 21.408 47.64 21.6 ;
    END
  END o2[34]
  PIN o2[35]
    DIRECTION OUTPUT ;
    USE SIGNAL ;
    PORT
      LAYER M5 ;
        RECT  47.856 21.408 47.88 21.6 ;
    END
  END o2[35]
  PIN o2[36]
    DIRECTION OUTPUT ;
    USE SIGNAL ;
    PORT
      LAYER M5 ;
        RECT  48.096 21.408 48.12 21.6 ;
    END
  END o2[36]
  PIN o2[37]
    DIRECTION OUTPUT ;
    USE SIGNAL ;
    PORT
      LAYER M5 ;
        RECT  48.384 21.408 48.408 21.6 ;
    END
  END o2[37]
  PIN o2[38]
    DIRECTION OUTPUT ;
    USE SIGNAL ;
    PORT
      LAYER M5 ;
        RECT  48.624 21.408 48.648 21.6 ;
    END
  END o2[38]
  PIN o2[39]
    DIRECTION OUTPUT ;
    USE SIGNAL ;
    PORT
      LAYER M5 ;
        RECT  48.864 21.408 48.888 21.6 ;
    END
  END o2[39]
  PIN o2[3]
    DIRECTION OUTPUT ;
    USE SIGNAL ;
    PORT
      LAYER M5 ;
        RECT  39.84 21.408 39.864 21.6 ;
    END
  END o2[3]
  PIN o2[40]
    DIRECTION OUTPUT ;
    USE SIGNAL ;
    PORT
      LAYER M5 ;
        RECT  49.104 21.408 49.128 21.6 ;
    END
  END o2[40]
  PIN o2[41]
    DIRECTION OUTPUT ;
    USE SIGNAL ;
    PORT
      LAYER M5 ;
        RECT  49.344 21.408 49.368 21.6 ;
    END
  END o2[41]
  PIN o2[42]
    DIRECTION OUTPUT ;
    USE SIGNAL ;
    PORT
      LAYER M5 ;
        RECT  49.632 21.408 49.656 21.6 ;
    END
  END o2[42]
  PIN o2[43]
    DIRECTION OUTPUT ;
    USE SIGNAL ;
    PORT
      LAYER M5 ;
        RECT  49.872 21.408 49.896 21.6 ;
    END
  END o2[43]
  PIN o2[44]
    DIRECTION OUTPUT ;
    USE SIGNAL ;
    PORT
      LAYER M5 ;
        RECT  50.112 21.408 50.136 21.6 ;
    END
  END o2[44]
  PIN o2[45]
    DIRECTION OUTPUT ;
    USE SIGNAL ;
    PORT
      LAYER M5 ;
        RECT  50.352 21.408 50.376 21.6 ;
    END
  END o2[45]
  PIN o2[46]
    DIRECTION OUTPUT ;
    USE SIGNAL ;
    PORT
      LAYER M5 ;
        RECT  50.64 21.408 50.664 21.6 ;
    END
  END o2[46]
  PIN o2[47]
    DIRECTION OUTPUT ;
    USE SIGNAL ;
    PORT
      LAYER M5 ;
        RECT  50.88 21.408 50.904 21.6 ;
    END
  END o2[47]
  PIN o2[48]
    DIRECTION OUTPUT ;
    USE SIGNAL ;
    PORT
      LAYER M5 ;
        RECT  51.12 21.408 51.144 21.6 ;
    END
  END o2[48]
  PIN o2[49]
    DIRECTION OUTPUT ;
    USE SIGNAL ;
    PORT
      LAYER M5 ;
        RECT  51.36 21.408 51.384 21.6 ;
    END
  END o2[49]
  PIN o2[4]
    DIRECTION OUTPUT ;
    USE SIGNAL ;
    PORT
      LAYER M5 ;
        RECT  40.08 21.408 40.104 21.6 ;
    END
  END o2[4]
  PIN o2[50]
    DIRECTION OUTPUT ;
    USE SIGNAL ;
    PORT
      LAYER M5 ;
        RECT  51.648 21.408 51.672 21.6 ;
    END
  END o2[50]
  PIN o2[51]
    DIRECTION OUTPUT ;
    USE SIGNAL ;
    PORT
      LAYER M5 ;
        RECT  51.888 21.408 51.912 21.6 ;
    END
  END o2[51]
  PIN o2[52]
    DIRECTION OUTPUT ;
    USE SIGNAL ;
    PORT
      LAYER M5 ;
        RECT  52.128 21.408 52.152 21.6 ;
    END
  END o2[52]
  PIN o2[53]
    DIRECTION OUTPUT ;
    USE SIGNAL ;
    PORT
      LAYER M5 ;
        RECT  52.368 21.408 52.392 21.6 ;
    END
  END o2[53]
  PIN o2[54]
    DIRECTION OUTPUT ;
    USE SIGNAL ;
    PORT
      LAYER M5 ;
        RECT  52.608 21.408 52.632 21.6 ;
    END
  END o2[54]
  PIN o2[55]
    DIRECTION OUTPUT ;
    USE SIGNAL ;
    PORT
      LAYER M5 ;
        RECT  52.896 21.408 52.92 21.6 ;
    END
  END o2[55]
  PIN o2[56]
    DIRECTION OUTPUT ;
    USE SIGNAL ;
    PORT
      LAYER M5 ;
        RECT  53.136 21.408 53.16 21.6 ;
    END
  END o2[56]
  PIN o2[57]
    DIRECTION OUTPUT ;
    USE SIGNAL ;
    PORT
      LAYER M5 ;
        RECT  53.376 21.408 53.4 21.6 ;
    END
  END o2[57]
  PIN o2[58]
    DIRECTION OUTPUT ;
    USE SIGNAL ;
    PORT
      LAYER M5 ;
        RECT  53.616 21.408 53.64 21.6 ;
    END
  END o2[58]
  PIN o2[59]
    DIRECTION OUTPUT ;
    USE SIGNAL ;
    PORT
      LAYER M5 ;
        RECT  53.904 21.408 53.928 21.6 ;
    END
  END o2[59]
  PIN o2[5]
    DIRECTION OUTPUT ;
    USE SIGNAL ;
    PORT
      LAYER M5 ;
        RECT  40.32 21.408 40.344 21.6 ;
    END
  END o2[5]
  PIN o2[60]
    DIRECTION OUTPUT ;
    USE SIGNAL ;
    PORT
      LAYER M5 ;
        RECT  54.144 21.408 54.168 21.6 ;
    END
  END o2[60]
  PIN o2[61]
    DIRECTION OUTPUT ;
    USE SIGNAL ;
    PORT
      LAYER M5 ;
        RECT  54.384 21.408 54.408 21.6 ;
    END
  END o2[61]
  PIN o2[62]
    DIRECTION OUTPUT ;
    USE SIGNAL ;
    PORT
      LAYER M5 ;
        RECT  54.624 21.408 54.648 21.6 ;
    END
  END o2[62]
  PIN o2[63]
    DIRECTION OUTPUT ;
    USE SIGNAL ;
    PORT
      LAYER M5 ;
        RECT  54.912 21.408 54.936 21.6 ;
    END
  END o2[63]
  PIN o2[64]
    DIRECTION OUTPUT ;
    USE SIGNAL ;
    PORT
      LAYER M5 ;
        RECT  55.152 21.408 55.176 21.6 ;
    END
  END o2[64]
  PIN o2[65]
    DIRECTION OUTPUT ;
    USE SIGNAL ;
    PORT
      LAYER M5 ;
        RECT  55.392 21.408 55.416 21.6 ;
    END
  END o2[65]
  PIN o2[66]
    DIRECTION OUTPUT ;
    USE SIGNAL ;
    PORT
      LAYER M5 ;
        RECT  55.632 21.408 55.656 21.6 ;
    END
  END o2[66]
  PIN o2[67]
    DIRECTION OUTPUT ;
    USE SIGNAL ;
    PORT
      LAYER M5 ;
        RECT  55.92 21.408 55.944 21.6 ;
    END
  END o2[67]
  PIN o2[68]
    DIRECTION OUTPUT ;
    USE SIGNAL ;
    PORT
      LAYER M5 ;
        RECT  56.4 21.408 56.424 21.6 ;
    END
  END o2[68]
  PIN o2[69]
    DIRECTION OUTPUT ;
    USE SIGNAL ;
    PORT
      LAYER M5 ;
        RECT  56.64 21.408 56.664 21.6 ;
    END
  END o2[69]
  PIN o2[6]
    DIRECTION OUTPUT ;
    USE SIGNAL ;
    PORT
      LAYER M5 ;
        RECT  40.56 21.408 40.584 21.6 ;
    END
  END o2[6]
  PIN o2[70]
    DIRECTION OUTPUT ;
    USE SIGNAL ;
    PORT
      LAYER M5 ;
        RECT  56.88 21.408 56.904 21.6 ;
    END
  END o2[70]
  PIN o2[71]
    DIRECTION OUTPUT ;
    USE SIGNAL ;
    PORT
      LAYER M5 ;
        RECT  57.168 21.408 57.192 21.6 ;
    END
  END o2[71]
  PIN o2[72]
    DIRECTION OUTPUT ;
    USE SIGNAL ;
    PORT
      LAYER M5 ;
        RECT  57.408 21.408 57.432 21.6 ;
    END
  END o2[72]
  PIN o2[73]
    DIRECTION OUTPUT ;
    USE SIGNAL ;
    PORT
      LAYER M5 ;
        RECT  57.648 21.408 57.672 21.6 ;
    END
  END o2[73]
  PIN o2[74]
    DIRECTION OUTPUT ;
    USE SIGNAL ;
    PORT
      LAYER M5 ;
        RECT  57.888 21.408 57.912 21.6 ;
    END
  END o2[74]
  PIN o2[75]
    DIRECTION OUTPUT ;
    USE SIGNAL ;
    PORT
      LAYER M5 ;
        RECT  58.176 21.408 58.2 21.6 ;
    END
  END o2[75]
  PIN o2[76]
    DIRECTION OUTPUT ;
    USE SIGNAL ;
    PORT
      LAYER M5 ;
        RECT  58.416 21.408 58.44 21.6 ;
    END
  END o2[76]
  PIN o2[77]
    DIRECTION OUTPUT ;
    USE SIGNAL ;
    PORT
      LAYER M5 ;
        RECT  58.656 21.408 58.68 21.6 ;
    END
  END o2[77]
  PIN o2[78]
    DIRECTION OUTPUT ;
    USE SIGNAL ;
    PORT
      LAYER M5 ;
        RECT  58.896 21.408 58.92 21.6 ;
    END
  END o2[78]
  PIN o2[79]
    DIRECTION OUTPUT ;
    USE SIGNAL ;
    PORT
      LAYER M5 ;
        RECT  59.184 21.408 59.208 21.6 ;
    END
  END o2[79]
  PIN o2[7]
    DIRECTION OUTPUT ;
    USE SIGNAL ;
    PORT
      LAYER M5 ;
        RECT  40.848 21.408 40.872 21.6 ;
    END
  END o2[7]
  PIN o2[80]
    DIRECTION OUTPUT ;
    USE SIGNAL ;
    PORT
      LAYER M5 ;
        RECT  59.424 21.408 59.448 21.6 ;
    END
  END o2[80]
  PIN o2[81]
    DIRECTION OUTPUT ;
    USE SIGNAL ;
    PORT
      LAYER M5 ;
        RECT  59.664 21.408 59.688 21.6 ;
    END
  END o2[81]
  PIN o2[82]
    DIRECTION OUTPUT ;
    USE SIGNAL ;
    PORT
      LAYER M5 ;
        RECT  59.904 21.408 59.928 21.6 ;
    END
  END o2[82]
  PIN o2[83]
    DIRECTION OUTPUT ;
    USE SIGNAL ;
    PORT
      LAYER M5 ;
        RECT  60.144 21.408 60.168 21.6 ;
    END
  END o2[83]
  PIN o2[84]
    DIRECTION OUTPUT ;
    USE SIGNAL ;
    PORT
      LAYER M5 ;
        RECT  60.432 21.408 60.456 21.6 ;
    END
  END o2[84]
  PIN o2[85]
    DIRECTION OUTPUT ;
    USE SIGNAL ;
    PORT
      LAYER M5 ;
        RECT  60.672 21.408 60.696 21.6 ;
    END
  END o2[85]
  PIN o2[86]
    DIRECTION OUTPUT ;
    USE SIGNAL ;
    PORT
      LAYER M5 ;
        RECT  60.912 21.408 60.936 21.6 ;
    END
  END o2[86]
  PIN o2[87]
    DIRECTION OUTPUT ;
    USE SIGNAL ;
    PORT
      LAYER M5 ;
        RECT  61.152 21.408 61.176 21.6 ;
    END
  END o2[87]
  PIN o2[88]
    DIRECTION OUTPUT ;
    USE SIGNAL ;
    PORT
      LAYER M5 ;
        RECT  61.44 21.408 61.464 21.6 ;
    END
  END o2[88]
  PIN o2[89]
    DIRECTION OUTPUT ;
    USE SIGNAL ;
    PORT
      LAYER M5 ;
        RECT  61.68 21.408 61.704 21.6 ;
    END
  END o2[89]
  PIN o2[8]
    DIRECTION OUTPUT ;
    USE SIGNAL ;
    PORT
      LAYER M5 ;
        RECT  41.088 21.408 41.112 21.6 ;
    END
  END o2[8]
  PIN o2[90]
    DIRECTION OUTPUT ;
    USE SIGNAL ;
    PORT
      LAYER M5 ;
        RECT  61.92 21.408 61.944 21.6 ;
    END
  END o2[90]
  PIN o2[91]
    DIRECTION OUTPUT ;
    USE SIGNAL ;
    PORT
      LAYER M5 ;
        RECT  62.16 21.408 62.184 21.6 ;
    END
  END o2[91]
  PIN o2[92]
    DIRECTION OUTPUT ;
    USE SIGNAL ;
    PORT
      LAYER M5 ;
        RECT  62.448 21.408 62.472 21.6 ;
    END
  END o2[92]
  PIN o2[93]
    DIRECTION OUTPUT ;
    USE SIGNAL ;
    PORT
      LAYER M5 ;
        RECT  62.688 21.408 62.712 21.6 ;
    END
  END o2[93]
  PIN o2[94]
    DIRECTION OUTPUT ;
    USE SIGNAL ;
    PORT
      LAYER M5 ;
        RECT  62.928 21.408 62.952 21.6 ;
    END
  END o2[94]
  PIN o2[95]
    DIRECTION OUTPUT ;
    USE SIGNAL ;
    PORT
      LAYER M5 ;
        RECT  63.168 21.408 63.192 21.6 ;
    END
  END o2[95]
  PIN o2[96]
    DIRECTION OUTPUT ;
    USE SIGNAL ;
    PORT
      LAYER M5 ;
        RECT  63.456 21.408 63.48 21.6 ;
    END
  END o2[96]
  PIN o2[97]
    DIRECTION OUTPUT ;
    USE SIGNAL ;
    PORT
      LAYER M5 ;
        RECT  63.696 21.408 63.72 21.6 ;
    END
  END o2[97]
  PIN o2[98]
    DIRECTION OUTPUT ;
    USE SIGNAL ;
    PORT
      LAYER M5 ;
        RECT  63.936 21.408 63.96 21.6 ;
    END
  END o2[98]
  PIN o2[99]
    DIRECTION OUTPUT ;
    USE SIGNAL ;
    PORT
      LAYER M5 ;
        RECT  64.176 21.408 64.2 21.6 ;
    END
  END o2[99]
  PIN o2[9]
    DIRECTION OUTPUT ;
    USE SIGNAL ;
    PORT
      LAYER M5 ;
        RECT  41.328 21.408 41.352 21.6 ;
    END
  END o2[9]
  PIN o3[0]
    DIRECTION OUTPUT ;
    USE SIGNAL ;
    PORT
      LAYER M5 ;
        RECT  50.592 0 50.616 0.192 ;
    END
  END o3[0]
  PIN o3[100]
    DIRECTION OUTPUT ;
    USE SIGNAL ;
    PORT
      LAYER M5 ;
        RECT  67.392 0 67.416 0.192 ;
    END
  END o3[100]
  PIN o3[101]
    DIRECTION OUTPUT ;
    USE SIGNAL ;
    PORT
      LAYER M5 ;
        RECT  67.584 0 67.608 0.192 ;
    END
  END o3[101]
  PIN o3[102]
    DIRECTION OUTPUT ;
    USE SIGNAL ;
    PORT
      LAYER M5 ;
        RECT  67.728 0 67.752 0.192 ;
    END
  END o3[102]
  PIN o3[103]
    DIRECTION OUTPUT ;
    USE SIGNAL ;
    PORT
      LAYER M5 ;
        RECT  67.92 0 67.944 0.192 ;
    END
  END o3[103]
  PIN o3[104]
    DIRECTION OUTPUT ;
    USE SIGNAL ;
    PORT
      LAYER M5 ;
        RECT  68.064 0 68.088 0.192 ;
    END
  END o3[104]
  PIN o3[105]
    DIRECTION OUTPUT ;
    USE SIGNAL ;
    PORT
      LAYER M5 ;
        RECT  68.256 0 68.28 0.192 ;
    END
  END o3[105]
  PIN o3[106]
    DIRECTION OUTPUT ;
    USE SIGNAL ;
    PORT
      LAYER M5 ;
        RECT  68.4 0 68.424 0.192 ;
    END
  END o3[106]
  PIN o3[107]
    DIRECTION OUTPUT ;
    USE SIGNAL ;
    PORT
      LAYER M5 ;
        RECT  68.544 0 68.568 0.192 ;
    END
  END o3[107]
  PIN o3[108]
    DIRECTION OUTPUT ;
    USE SIGNAL ;
    PORT
      LAYER M5 ;
        RECT  68.736 0 68.76 0.192 ;
    END
  END o3[108]
  PIN o3[109]
    DIRECTION OUTPUT ;
    USE SIGNAL ;
    PORT
      LAYER M5 ;
        RECT  68.88 0 68.904 0.192 ;
    END
  END o3[109]
  PIN o3[10]
    DIRECTION OUTPUT ;
    USE SIGNAL ;
    PORT
      LAYER M5 ;
        RECT  52.272 0 52.296 0.192 ;
    END
  END o3[10]
  PIN o3[110]
    DIRECTION OUTPUT ;
    USE SIGNAL ;
    PORT
      LAYER M5 ;
        RECT  69.072 0 69.096 0.192 ;
    END
  END o3[110]
  PIN o3[111]
    DIRECTION OUTPUT ;
    USE SIGNAL ;
    PORT
      LAYER M5 ;
        RECT  69.216 0 69.24 0.192 ;
    END
  END o3[111]
  PIN o3[112]
    DIRECTION OUTPUT ;
    USE SIGNAL ;
    PORT
      LAYER M5 ;
        RECT  69.408 0 69.432 0.192 ;
    END
  END o3[112]
  PIN o3[113]
    DIRECTION OUTPUT ;
    USE SIGNAL ;
    PORT
      LAYER M5 ;
        RECT  69.552 0 69.576 0.192 ;
    END
  END o3[113]
  PIN o3[114]
    DIRECTION OUTPUT ;
    USE SIGNAL ;
    PORT
      LAYER M5 ;
        RECT  69.744 0 69.768 0.192 ;
    END
  END o3[114]
  PIN o3[115]
    DIRECTION OUTPUT ;
    USE SIGNAL ;
    PORT
      LAYER M5 ;
        RECT  69.888 0 69.912 0.192 ;
    END
  END o3[115]
  PIN o3[116]
    DIRECTION OUTPUT ;
    USE SIGNAL ;
    PORT
      LAYER M5 ;
        RECT  70.08 0 70.104 0.192 ;
    END
  END o3[116]
  PIN o3[117]
    DIRECTION OUTPUT ;
    USE SIGNAL ;
    PORT
      LAYER M5 ;
        RECT  70.224 0 70.248 0.192 ;
    END
  END o3[117]
  PIN o3[118]
    DIRECTION OUTPUT ;
    USE SIGNAL ;
    PORT
      LAYER M5 ;
        RECT  70.416 0 70.44 0.192 ;
    END
  END o3[118]
  PIN o3[119]
    DIRECTION OUTPUT ;
    USE SIGNAL ;
    PORT
      LAYER M5 ;
        RECT  70.56 0 70.584 0.192 ;
    END
  END o3[119]
  PIN o3[11]
    DIRECTION OUTPUT ;
    USE SIGNAL ;
    PORT
      LAYER M5 ;
        RECT  52.416 0 52.44 0.192 ;
    END
  END o3[11]
  PIN o3[120]
    DIRECTION OUTPUT ;
    USE SIGNAL ;
    PORT
      LAYER M5 ;
        RECT  70.752 0 70.776 0.192 ;
    END
  END o3[120]
  PIN o3[121]
    DIRECTION OUTPUT ;
    USE SIGNAL ;
    PORT
      LAYER M5 ;
        RECT  70.896 0 70.92 0.192 ;
    END
  END o3[121]
  PIN o3[122]
    DIRECTION OUTPUT ;
    USE SIGNAL ;
    PORT
      LAYER M5 ;
        RECT  71.04 0 71.064 0.192 ;
    END
  END o3[122]
  PIN o3[123]
    DIRECTION OUTPUT ;
    USE SIGNAL ;
    PORT
      LAYER M5 ;
        RECT  71.232 0 71.256 0.192 ;
    END
  END o3[123]
  PIN o3[124]
    DIRECTION OUTPUT ;
    USE SIGNAL ;
    PORT
      LAYER M5 ;
        RECT  71.376 0 71.4 0.192 ;
    END
  END o3[124]
  PIN o3[125]
    DIRECTION OUTPUT ;
    USE SIGNAL ;
    PORT
      LAYER M5 ;
        RECT  71.568 0 71.592 0.192 ;
    END
  END o3[125]
  PIN o3[126]
    DIRECTION OUTPUT ;
    USE SIGNAL ;
    PORT
      LAYER M5 ;
        RECT  71.712 0 71.736 0.192 ;
    END
  END o3[126]
  PIN o3[127]
    DIRECTION OUTPUT ;
    USE SIGNAL ;
    PORT
      LAYER M5 ;
        RECT  71.904 0 71.928 0.192 ;
    END
  END o3[127]
  PIN o3[128]
    DIRECTION OUTPUT ;
    USE SIGNAL ;
    PORT
      LAYER M5 ;
        RECT  72.048 0 72.072 0.192 ;
    END
  END o3[128]
  PIN o3[129]
    DIRECTION OUTPUT ;
    USE SIGNAL ;
    PORT
      LAYER M5 ;
        RECT  72.24 0 72.264 0.192 ;
    END
  END o3[129]
  PIN o3[12]
    DIRECTION OUTPUT ;
    USE SIGNAL ;
    PORT
      LAYER M5 ;
        RECT  52.608 0 52.632 0.192 ;
    END
  END o3[12]
  PIN o3[130]
    DIRECTION OUTPUT ;
    USE SIGNAL ;
    PORT
      LAYER M5 ;
        RECT  72.384 0 72.408 0.192 ;
    END
  END o3[130]
  PIN o3[131]
    DIRECTION OUTPUT ;
    USE SIGNAL ;
    PORT
      LAYER M5 ;
        RECT  72.576 0 72.6 0.192 ;
    END
  END o3[131]
  PIN o3[132]
    DIRECTION OUTPUT ;
    USE SIGNAL ;
    PORT
      LAYER M5 ;
        RECT  72.72 0 72.744 0.192 ;
    END
  END o3[132]
  PIN o3[133]
    DIRECTION OUTPUT ;
    USE SIGNAL ;
    PORT
      LAYER M5 ;
        RECT  72.912 0 72.936 0.192 ;
    END
  END o3[133]
  PIN o3[134]
    DIRECTION OUTPUT ;
    USE SIGNAL ;
    PORT
      LAYER M5 ;
        RECT  73.056 0 73.08 0.192 ;
    END
  END o3[134]
  PIN o3[135]
    DIRECTION OUTPUT ;
    USE SIGNAL ;
    PORT
      LAYER M5 ;
        RECT  73.248 0 73.272 0.192 ;
    END
  END o3[135]
  PIN o3[13]
    DIRECTION OUTPUT ;
    USE SIGNAL ;
    PORT
      LAYER M5 ;
        RECT  52.752 0 52.776 0.192 ;
    END
  END o3[13]
  PIN o3[14]
    DIRECTION OUTPUT ;
    USE SIGNAL ;
    PORT
      LAYER M5 ;
        RECT  52.896 0 52.92 0.192 ;
    END
  END o3[14]
  PIN o3[15]
    DIRECTION OUTPUT ;
    USE SIGNAL ;
    PORT
      LAYER M5 ;
        RECT  53.088 0 53.112 0.192 ;
    END
  END o3[15]
  PIN o3[16]
    DIRECTION OUTPUT ;
    USE SIGNAL ;
    PORT
      LAYER M5 ;
        RECT  53.232 0 53.256 0.192 ;
    END
  END o3[16]
  PIN o3[17]
    DIRECTION OUTPUT ;
    USE SIGNAL ;
    PORT
      LAYER M5 ;
        RECT  53.424 0 53.448 0.192 ;
    END
  END o3[17]
  PIN o3[18]
    DIRECTION OUTPUT ;
    USE SIGNAL ;
    PORT
      LAYER M5 ;
        RECT  53.568 0 53.592 0.192 ;
    END
  END o3[18]
  PIN o3[19]
    DIRECTION OUTPUT ;
    USE SIGNAL ;
    PORT
      LAYER M5 ;
        RECT  53.76 0 53.784 0.192 ;
    END
  END o3[19]
  PIN o3[1]
    DIRECTION OUTPUT ;
    USE SIGNAL ;
    PORT
      LAYER M5 ;
        RECT  50.736 0 50.76 0.192 ;
    END
  END o3[1]
  PIN o3[20]
    DIRECTION OUTPUT ;
    USE SIGNAL ;
    PORT
      LAYER M5 ;
        RECT  53.904 0 53.928 0.192 ;
    END
  END o3[20]
  PIN o3[21]
    DIRECTION OUTPUT ;
    USE SIGNAL ;
    PORT
      LAYER M5 ;
        RECT  54.096 0 54.12 0.192 ;
    END
  END o3[21]
  PIN o3[22]
    DIRECTION OUTPUT ;
    USE SIGNAL ;
    PORT
      LAYER M5 ;
        RECT  54.24 0 54.264 0.192 ;
    END
  END o3[22]
  PIN o3[23]
    DIRECTION OUTPUT ;
    USE SIGNAL ;
    PORT
      LAYER M5 ;
        RECT  54.432 0 54.456 0.192 ;
    END
  END o3[23]
  PIN o3[24]
    DIRECTION OUTPUT ;
    USE SIGNAL ;
    PORT
      LAYER M5 ;
        RECT  54.576 0 54.6 0.192 ;
    END
  END o3[24]
  PIN o3[25]
    DIRECTION OUTPUT ;
    USE SIGNAL ;
    PORT
      LAYER M5 ;
        RECT  54.768 0 54.792 0.192 ;
    END
  END o3[25]
  PIN o3[26]
    DIRECTION OUTPUT ;
    USE SIGNAL ;
    PORT
      LAYER M5 ;
        RECT  54.912 0 54.936 0.192 ;
    END
  END o3[26]
  PIN o3[27]
    DIRECTION OUTPUT ;
    USE SIGNAL ;
    PORT
      LAYER M5 ;
        RECT  55.104 0 55.128 0.192 ;
    END
  END o3[27]
  PIN o3[28]
    DIRECTION OUTPUT ;
    USE SIGNAL ;
    PORT
      LAYER M5 ;
        RECT  55.248 0 55.272 0.192 ;
    END
  END o3[28]
  PIN o3[29]
    DIRECTION OUTPUT ;
    USE SIGNAL ;
    PORT
      LAYER M5 ;
        RECT  55.392 0 55.416 0.192 ;
    END
  END o3[29]
  PIN o3[2]
    DIRECTION OUTPUT ;
    USE SIGNAL ;
    PORT
      LAYER M5 ;
        RECT  50.928 0 50.952 0.192 ;
    END
  END o3[2]
  PIN o3[30]
    DIRECTION OUTPUT ;
    USE SIGNAL ;
    PORT
      LAYER M5 ;
        RECT  55.584 0 55.608 0.192 ;
    END
  END o3[30]
  PIN o3[31]
    DIRECTION OUTPUT ;
    USE SIGNAL ;
    PORT
      LAYER M5 ;
        RECT  55.728 0 55.752 0.192 ;
    END
  END o3[31]
  PIN o3[32]
    DIRECTION OUTPUT ;
    USE SIGNAL ;
    PORT
      LAYER M5 ;
        RECT  55.92 0 55.944 0.192 ;
    END
  END o3[32]
  PIN o3[33]
    DIRECTION OUTPUT ;
    USE SIGNAL ;
    PORT
      LAYER M5 ;
        RECT  56.064 0 56.088 0.192 ;
    END
  END o3[33]
  PIN o3[34]
    DIRECTION OUTPUT ;
    USE SIGNAL ;
    PORT
      LAYER M5 ;
        RECT  56.256 0 56.28 0.192 ;
    END
  END o3[34]
  PIN o3[35]
    DIRECTION OUTPUT ;
    USE SIGNAL ;
    PORT
      LAYER M5 ;
        RECT  56.4 0 56.424 0.192 ;
    END
  END o3[35]
  PIN o3[36]
    DIRECTION OUTPUT ;
    USE SIGNAL ;
    PORT
      LAYER M5 ;
        RECT  56.592 0 56.616 0.192 ;
    END
  END o3[36]
  PIN o3[37]
    DIRECTION OUTPUT ;
    USE SIGNAL ;
    PORT
      LAYER M5 ;
        RECT  56.736 0 56.76 0.192 ;
    END
  END o3[37]
  PIN o3[38]
    DIRECTION OUTPUT ;
    USE SIGNAL ;
    PORT
      LAYER M5 ;
        RECT  56.928 0 56.952 0.192 ;
    END
  END o3[38]
  PIN o3[39]
    DIRECTION OUTPUT ;
    USE SIGNAL ;
    PORT
      LAYER M5 ;
        RECT  57.072 0 57.096 0.192 ;
    END
  END o3[39]
  PIN o3[3]
    DIRECTION OUTPUT ;
    USE SIGNAL ;
    PORT
      LAYER M5 ;
        RECT  51.072 0 51.096 0.192 ;
    END
  END o3[3]
  PIN o3[40]
    DIRECTION OUTPUT ;
    USE SIGNAL ;
    PORT
      LAYER M5 ;
        RECT  57.264 0 57.288 0.192 ;
    END
  END o3[40]
  PIN o3[41]
    DIRECTION OUTPUT ;
    USE SIGNAL ;
    PORT
      LAYER M5 ;
        RECT  57.408 0 57.432 0.192 ;
    END
  END o3[41]
  PIN o3[42]
    DIRECTION OUTPUT ;
    USE SIGNAL ;
    PORT
      LAYER M5 ;
        RECT  57.6 0 57.624 0.192 ;
    END
  END o3[42]
  PIN o3[43]
    DIRECTION OUTPUT ;
    USE SIGNAL ;
    PORT
      LAYER M5 ;
        RECT  57.744 0 57.768 0.192 ;
    END
  END o3[43]
  PIN o3[44]
    DIRECTION OUTPUT ;
    USE SIGNAL ;
    PORT
      LAYER M5 ;
        RECT  57.936 0 57.96 0.192 ;
    END
  END o3[44]
  PIN o3[45]
    DIRECTION OUTPUT ;
    USE SIGNAL ;
    PORT
      LAYER M5 ;
        RECT  58.08 0 58.104 0.192 ;
    END
  END o3[45]
  PIN o3[46]
    DIRECTION OUTPUT ;
    USE SIGNAL ;
    PORT
      LAYER M5 ;
        RECT  58.224 0 58.248 0.192 ;
    END
  END o3[46]
  PIN o3[47]
    DIRECTION OUTPUT ;
    USE SIGNAL ;
    PORT
      LAYER M5 ;
        RECT  58.416 0 58.44 0.192 ;
    END
  END o3[47]
  PIN o3[48]
    DIRECTION OUTPUT ;
    USE SIGNAL ;
    PORT
      LAYER M5 ;
        RECT  58.56 0 58.584 0.192 ;
    END
  END o3[48]
  PIN o3[49]
    DIRECTION OUTPUT ;
    USE SIGNAL ;
    PORT
      LAYER M5 ;
        RECT  58.752 0 58.776 0.192 ;
    END
  END o3[49]
  PIN o3[4]
    DIRECTION OUTPUT ;
    USE SIGNAL ;
    PORT
      LAYER M5 ;
        RECT  51.264 0 51.288 0.192 ;
    END
  END o3[4]
  PIN o3[50]
    DIRECTION OUTPUT ;
    USE SIGNAL ;
    PORT
      LAYER M5 ;
        RECT  58.896 0 58.92 0.192 ;
    END
  END o3[50]
  PIN o3[51]
    DIRECTION OUTPUT ;
    USE SIGNAL ;
    PORT
      LAYER M5 ;
        RECT  59.088 0 59.112 0.192 ;
    END
  END o3[51]
  PIN o3[52]
    DIRECTION OUTPUT ;
    USE SIGNAL ;
    PORT
      LAYER M5 ;
        RECT  59.232 0 59.256 0.192 ;
    END
  END o3[52]
  PIN o3[53]
    DIRECTION OUTPUT ;
    USE SIGNAL ;
    PORT
      LAYER M5 ;
        RECT  59.424 0 59.448 0.192 ;
    END
  END o3[53]
  PIN o3[54]
    DIRECTION OUTPUT ;
    USE SIGNAL ;
    PORT
      LAYER M5 ;
        RECT  59.568 0 59.592 0.192 ;
    END
  END o3[54]
  PIN o3[55]
    DIRECTION OUTPUT ;
    USE SIGNAL ;
    PORT
      LAYER M5 ;
        RECT  59.76 0 59.784 0.192 ;
    END
  END o3[55]
  PIN o3[56]
    DIRECTION OUTPUT ;
    USE SIGNAL ;
    PORT
      LAYER M5 ;
        RECT  59.904 0 59.928 0.192 ;
    END
  END o3[56]
  PIN o3[57]
    DIRECTION OUTPUT ;
    USE SIGNAL ;
    PORT
      LAYER M5 ;
        RECT  60.096 0 60.12 0.192 ;
    END
  END o3[57]
  PIN o3[58]
    DIRECTION OUTPUT ;
    USE SIGNAL ;
    PORT
      LAYER M5 ;
        RECT  60.24 0 60.264 0.192 ;
    END
  END o3[58]
  PIN o3[59]
    DIRECTION OUTPUT ;
    USE SIGNAL ;
    PORT
      LAYER M5 ;
        RECT  60.432 0 60.456 0.192 ;
    END
  END o3[59]
  PIN o3[5]
    DIRECTION OUTPUT ;
    USE SIGNAL ;
    PORT
      LAYER M5 ;
        RECT  51.408 0 51.432 0.192 ;
    END
  END o3[5]
  PIN o3[60]
    DIRECTION OUTPUT ;
    USE SIGNAL ;
    PORT
      LAYER M5 ;
        RECT  60.576 0 60.6 0.192 ;
    END
  END o3[60]
  PIN o3[61]
    DIRECTION OUTPUT ;
    USE SIGNAL ;
    PORT
      LAYER M5 ;
        RECT  60.72 0 60.744 0.192 ;
    END
  END o3[61]
  PIN o3[62]
    DIRECTION OUTPUT ;
    USE SIGNAL ;
    PORT
      LAYER M5 ;
        RECT  60.912 0 60.936 0.192 ;
    END
  END o3[62]
  PIN o3[63]
    DIRECTION OUTPUT ;
    USE SIGNAL ;
    PORT
      LAYER M5 ;
        RECT  61.056 0 61.08 0.192 ;
    END
  END o3[63]
  PIN o3[64]
    DIRECTION OUTPUT ;
    USE SIGNAL ;
    PORT
      LAYER M5 ;
        RECT  61.248 0 61.272 0.192 ;
    END
  END o3[64]
  PIN o3[65]
    DIRECTION OUTPUT ;
    USE SIGNAL ;
    PORT
      LAYER M5 ;
        RECT  61.392 0 61.416 0.192 ;
    END
  END o3[65]
  PIN o3[66]
    DIRECTION OUTPUT ;
    USE SIGNAL ;
    PORT
      LAYER M5 ;
        RECT  61.584 0 61.608 0.192 ;
    END
  END o3[66]
  PIN o3[67]
    DIRECTION OUTPUT ;
    USE SIGNAL ;
    PORT
      LAYER M5 ;
        RECT  61.728 0 61.752 0.192 ;
    END
  END o3[67]
  PIN o3[68]
    DIRECTION OUTPUT ;
    USE SIGNAL ;
    PORT
      LAYER M5 ;
        RECT  62.064 0 62.088 0.192 ;
    END
  END o3[68]
  PIN o3[69]
    DIRECTION OUTPUT ;
    USE SIGNAL ;
    PORT
      LAYER M5 ;
        RECT  62.256 0 62.28 0.192 ;
    END
  END o3[69]
  PIN o3[6]
    DIRECTION OUTPUT ;
    USE SIGNAL ;
    PORT
      LAYER M5 ;
        RECT  51.6 0 51.624 0.192 ;
    END
  END o3[6]
  PIN o3[70]
    DIRECTION OUTPUT ;
    USE SIGNAL ;
    PORT
      LAYER M5 ;
        RECT  62.4 0 62.424 0.192 ;
    END
  END o3[70]
  PIN o3[71]
    DIRECTION OUTPUT ;
    USE SIGNAL ;
    PORT
      LAYER M5 ;
        RECT  62.592 0 62.616 0.192 ;
    END
  END o3[71]
  PIN o3[72]
    DIRECTION OUTPUT ;
    USE SIGNAL ;
    PORT
      LAYER M5 ;
        RECT  62.736 0 62.76 0.192 ;
    END
  END o3[72]
  PIN o3[73]
    DIRECTION OUTPUT ;
    USE SIGNAL ;
    PORT
      LAYER M5 ;
        RECT  62.928 0 62.952 0.192 ;
    END
  END o3[73]
  PIN o3[74]
    DIRECTION OUTPUT ;
    USE SIGNAL ;
    PORT
      LAYER M5 ;
        RECT  63.072 0 63.096 0.192 ;
    END
  END o3[74]
  PIN o3[75]
    DIRECTION OUTPUT ;
    USE SIGNAL ;
    PORT
      LAYER M5 ;
        RECT  63.216 0 63.24 0.192 ;
    END
  END o3[75]
  PIN o3[76]
    DIRECTION OUTPUT ;
    USE SIGNAL ;
    PORT
      LAYER M5 ;
        RECT  63.408 0 63.432 0.192 ;
    END
  END o3[76]
  PIN o3[77]
    DIRECTION OUTPUT ;
    USE SIGNAL ;
    PORT
      LAYER M5 ;
        RECT  63.552 0 63.576 0.192 ;
    END
  END o3[77]
  PIN o3[78]
    DIRECTION OUTPUT ;
    USE SIGNAL ;
    PORT
      LAYER M5 ;
        RECT  63.744 0 63.768 0.192 ;
    END
  END o3[78]
  PIN o3[79]
    DIRECTION OUTPUT ;
    USE SIGNAL ;
    PORT
      LAYER M5 ;
        RECT  63.888 0 63.912 0.192 ;
    END
  END o3[79]
  PIN o3[7]
    DIRECTION OUTPUT ;
    USE SIGNAL ;
    PORT
      LAYER M5 ;
        RECT  51.744 0 51.768 0.192 ;
    END
  END o3[7]
  PIN o3[80]
    DIRECTION OUTPUT ;
    USE SIGNAL ;
    PORT
      LAYER M5 ;
        RECT  64.08 0 64.104 0.192 ;
    END
  END o3[80]
  PIN o3[81]
    DIRECTION OUTPUT ;
    USE SIGNAL ;
    PORT
      LAYER M5 ;
        RECT  64.224 0 64.248 0.192 ;
    END
  END o3[81]
  PIN o3[82]
    DIRECTION OUTPUT ;
    USE SIGNAL ;
    PORT
      LAYER M5 ;
        RECT  64.416 0 64.44 0.192 ;
    END
  END o3[82]
  PIN o3[83]
    DIRECTION OUTPUT ;
    USE SIGNAL ;
    PORT
      LAYER M5 ;
        RECT  64.56 0 64.584 0.192 ;
    END
  END o3[83]
  PIN o3[84]
    DIRECTION OUTPUT ;
    USE SIGNAL ;
    PORT
      LAYER M5 ;
        RECT  64.752 0 64.776 0.192 ;
    END
  END o3[84]
  PIN o3[85]
    DIRECTION OUTPUT ;
    USE SIGNAL ;
    PORT
      LAYER M5 ;
        RECT  64.896 0 64.92 0.192 ;
    END
  END o3[85]
  PIN o3[86]
    DIRECTION OUTPUT ;
    USE SIGNAL ;
    PORT
      LAYER M5 ;
        RECT  65.088 0 65.112 0.192 ;
    END
  END o3[86]
  PIN o3[87]
    DIRECTION OUTPUT ;
    USE SIGNAL ;
    PORT
      LAYER M5 ;
        RECT  65.232 0 65.256 0.192 ;
    END
  END o3[87]
  PIN o3[88]
    DIRECTION OUTPUT ;
    USE SIGNAL ;
    PORT
      LAYER M5 ;
        RECT  65.424 0 65.448 0.192 ;
    END
  END o3[88]
  PIN o3[89]
    DIRECTION OUTPUT ;
    USE SIGNAL ;
    PORT
      LAYER M5 ;
        RECT  65.568 0 65.592 0.192 ;
    END
  END o3[89]
  PIN o3[8]
    DIRECTION OUTPUT ;
    USE SIGNAL ;
    PORT
      LAYER M5 ;
        RECT  51.936 0 51.96 0.192 ;
    END
  END o3[8]
  PIN o3[90]
    DIRECTION OUTPUT ;
    USE SIGNAL ;
    PORT
      LAYER M5 ;
        RECT  65.76 0 65.784 0.192 ;
    END
  END o3[90]
  PIN o3[91]
    DIRECTION OUTPUT ;
    USE SIGNAL ;
    PORT
      LAYER M5 ;
        RECT  65.904 0 65.928 0.192 ;
    END
  END o3[91]
  PIN o3[92]
    DIRECTION OUTPUT ;
    USE SIGNAL ;
    PORT
      LAYER M5 ;
        RECT  66.048 0 66.072 0.192 ;
    END
  END o3[92]
  PIN o3[93]
    DIRECTION OUTPUT ;
    USE SIGNAL ;
    PORT
      LAYER M5 ;
        RECT  66.24 0 66.264 0.192 ;
    END
  END o3[93]
  PIN o3[94]
    DIRECTION OUTPUT ;
    USE SIGNAL ;
    PORT
      LAYER M5 ;
        RECT  66.384 0 66.408 0.192 ;
    END
  END o3[94]
  PIN o3[95]
    DIRECTION OUTPUT ;
    USE SIGNAL ;
    PORT
      LAYER M5 ;
        RECT  66.576 0 66.6 0.192 ;
    END
  END o3[95]
  PIN o3[96]
    DIRECTION OUTPUT ;
    USE SIGNAL ;
    PORT
      LAYER M5 ;
        RECT  66.72 0 66.744 0.192 ;
    END
  END o3[96]
  PIN o3[97]
    DIRECTION OUTPUT ;
    USE SIGNAL ;
    PORT
      LAYER M5 ;
        RECT  66.912 0 66.936 0.192 ;
    END
  END o3[97]
  PIN o3[98]
    DIRECTION OUTPUT ;
    USE SIGNAL ;
    PORT
      LAYER M5 ;
        RECT  67.056 0 67.08 0.192 ;
    END
  END o3[98]
  PIN o3[99]
    DIRECTION OUTPUT ;
    USE SIGNAL ;
    PORT
      LAYER M5 ;
        RECT  67.248 0 67.272 0.192 ;
    END
  END o3[99]
  PIN o3[9]
    DIRECTION OUTPUT ;
    USE SIGNAL ;
    PORT
      LAYER M5 ;
        RECT  52.08 0 52.104 0.192 ;
    END
  END o3[9]
  PIN rs
    DIRECTION INPUT ;
    USE SIGNAL ;
    PORT
      LAYER M4 ;
        RECT  0 10.8 0.192 10.824 ;
    END
    PORT
      LAYER M4 ;
        RECT  0.156 10.8 2.408 10.824 ;
    END
  END rs
  PIN VDD
    DIRECTION INOUT ;
    USE POWER ;
    PORT
      LAYER M5 ;
        RECT  75.492 2.151 75.612 19.449 ;
        RECT  72.792 2.151 72.912 19.449 ;
        RECT  70.092 2.151 70.212 19.449 ;
        RECT  67.392 2.151 67.512 19.449 ;
        RECT  64.692 2.151 64.812 19.449 ;
        RECT  61.992 2.151 62.112 19.449 ;
        RECT  59.292 2.151 59.412 19.449 ;
        RECT  56.592 2.151 56.712 19.449 ;
        RECT  53.892 2.151 54.012 19.449 ;
        RECT  51.192 2.151 51.312 19.449 ;
        RECT  48.492 2.151 48.612 19.449 ;
        RECT  45.792 2.151 45.912 19.449 ;
        RECT  43.092 2.151 43.212 19.449 ;
        RECT  40.392 2.151 40.512 19.449 ;
        RECT  37.692 2.151 37.812 19.449 ;
        RECT  34.992 2.151 35.112 19.449 ;
        RECT  32.292 2.151 32.412 19.449 ;
        RECT  29.592 2.151 29.712 19.449 ;
        RECT  26.892 2.151 27.012 19.449 ;
        RECT  24.192 2.151 24.312 19.449 ;
        RECT  21.492 2.151 21.612 19.449 ;
        RECT  18.792 2.151 18.912 19.449 ;
        RECT  16.092 2.151 16.212 19.449 ;
        RECT  13.392 2.151 13.512 19.449 ;
        RECT  10.692 2.151 10.812 19.449 ;
        RECT  7.992 2.151 8.112 19.449 ;
        RECT  5.292 2.151 5.412 19.449 ;
        RECT  2.592 2.151 2.712 19.449 ;
    END
  END VDD
  PIN VSS
    DIRECTION INOUT ;
    USE GROUND ;
    PORT
      LAYER M5 ;
        RECT  75.3 2.137 75.42 19.463 ;
        RECT  72.6 2.137 72.72 19.463 ;
        RECT  69.9 2.137 70.02 19.463 ;
        RECT  67.2 2.137 67.32 19.463 ;
        RECT  64.5 2.137 64.62 19.463 ;
        RECT  61.8 2.137 61.92 19.463 ;
        RECT  59.1 2.137 59.22 19.463 ;
        RECT  56.4 2.137 56.52 19.463 ;
        RECT  53.7 2.137 53.82 19.463 ;
        RECT  51 2.137 51.12 19.463 ;
        RECT  48.3 2.137 48.42 19.463 ;
        RECT  45.6 2.137 45.72 19.463 ;
        RECT  42.9 2.137 43.02 19.463 ;
        RECT  40.2 2.137 40.32 19.463 ;
        RECT  37.5 2.137 37.62 19.463 ;
        RECT  34.8 2.137 34.92 19.463 ;
        RECT  32.1 2.137 32.22 19.463 ;
        RECT  29.4 2.137 29.52 19.463 ;
        RECT  26.7 2.137 26.82 19.463 ;
        RECT  24 2.137 24.12 19.463 ;
        RECT  21.3 2.137 21.42 19.463 ;
        RECT  18.6 2.137 18.72 19.463 ;
        RECT  15.9 2.137 16.02 19.463 ;
        RECT  13.2 2.137 13.32 19.463 ;
        RECT  10.5 2.137 10.62 19.463 ;
        RECT  7.8 2.137 7.92 19.463 ;
        RECT  5.1 2.137 5.22 19.463 ;
        RECT  2.4 2.137 2.52 19.463 ;
    END
  END VSS
  # OT_OBS_CLOSED layer=M5 d_um=1.536 added=129
  OBS
    LAYER RVTN ;
     RECT  2.16 2.16 75.6 2.295 ;
     RECT  2.16 2.565 75.6 2.835 ;
     RECT  2.16 3.105 75.6 3.375 ;
     RECT  2.16 3.645 75.6 3.915 ;
     RECT  2.16 4.185 75.6 4.455 ;
     RECT  2.16 4.725 75.6 4.995 ;
     RECT  2.16 5.265 75.6 5.535 ;
     RECT  2.16 5.805 75.6 6.075 ;
     RECT  2.16 6.345 75.6 6.615 ;
     RECT  2.16 6.885 75.6 7.155 ;
     RECT  2.16 7.425 75.6 7.695 ;
     RECT  2.16 7.965 75.6 8.235 ;
     RECT  2.16 8.505 75.6 8.775 ;
     RECT  2.16 9.045 75.6 9.315 ;
     RECT  2.16 9.585 75.6 9.855 ;
     RECT  2.16 10.125 75.6 10.395 ;
     RECT  2.16 10.665 75.6 10.935 ;
     RECT  2.16 11.205 75.6 11.475 ;
     RECT  2.16 11.745 75.6 12.015 ;
     RECT  2.16 12.285 75.6 12.555 ;
     RECT  2.16 12.825 75.6 13.095 ;
     RECT  2.16 13.365 75.6 13.635 ;
     RECT  2.16 13.905 75.6 14.175 ;
     RECT  2.16 14.445 75.6 14.715 ;
     RECT  2.16 14.985 75.6 15.255 ;
     RECT  2.16 15.525 75.6 15.795 ;
     RECT  2.16 16.065 75.6 16.335 ;
     RECT  2.16 16.605 75.6 16.875 ;
     RECT  2.16 17.145 75.6 17.415 ;
     RECT  2.16 17.685 75.6 17.955 ;
     RECT  2.16 18.225 75.6 18.495 ;
     RECT  2.16 18.765 75.6 19.035 ;
     RECT  2.16 19.305 75.6 19.44 ;
    LAYER RVTP ;
     RECT  2.16 2.295 75.6 2.565 ;
     RECT  2.16 2.835 75.6 3.105 ;
     RECT  2.16 3.375 75.6 3.645 ;
     RECT  2.16 3.915 75.6 4.185 ;
     RECT  2.16 4.455 75.6 4.725 ;
     RECT  2.16 4.995 75.6 5.265 ;
     RECT  2.16 5.535 75.6 5.805 ;
     RECT  2.16 6.075 75.6 6.345 ;
     RECT  2.16 6.615 75.6 6.885 ;
     RECT  2.16 7.155 75.6 7.425 ;
     RECT  2.16 7.695 75.6 7.965 ;
     RECT  2.16 8.235 75.6 8.505 ;
     RECT  2.16 8.775 75.6 9.045 ;
     RECT  2.16 9.315 75.6 9.585 ;
     RECT  2.16 9.855 75.6 10.125 ;
     RECT  2.16 10.395 75.6 10.665 ;
     RECT  2.16 10.935 75.6 11.205 ;
     RECT  2.16 11.475 75.6 11.745 ;
     RECT  2.16 12.015 75.6 12.285 ;
     RECT  2.16 12.555 75.6 12.825 ;
     RECT  2.16 13.095 75.6 13.365 ;
     RECT  2.16 13.635 75.6 13.905 ;
     RECT  2.16 14.175 75.6 14.445 ;
     RECT  2.16 14.715 75.6 14.985 ;
     RECT  2.16 15.255 75.6 15.525 ;
     RECT  2.16 15.795 75.6 16.065 ;
     RECT  2.16 16.335 75.6 16.605 ;
     RECT  2.16 16.875 75.6 17.145 ;
     RECT  2.16 17.415 75.6 17.685 ;
     RECT  2.16 17.955 75.6 18.225 ;
     RECT  2.16 18.495 75.6 18.765 ;
     RECT  2.16 19.035 75.6 19.305 ;
    LAYER M1 ;
     RECT  2.16 2.151 75.6 19.449 ;
    LAYER M2 ;
     RECT  1.975 13.572 2.16 13.59 ;
     RECT  2.16 2.151 5.647 19.449 ;
     RECT  5.647 2.106 6.215 19.449 ;
     RECT  6.215 2.151 11.731 19.449 ;
     RECT  11.731 2.034 13.783 19.449 ;
     RECT  13.783 2.034 16.591 19.494 ;
     RECT  16.591 1.998 19.399 19.494 ;
     RECT  19.399 1.998 19.615 19.53 ;
     RECT  19.615 1.998 20.371 19.674 ;
     RECT  20.371 1.962 21.119 19.674 ;
     RECT  21.119 1.962 22.819 19.638 ;
     RECT  22.819 1.836 25.087 19.638 ;
     RECT  25.087 1.764 32.783 19.719 ;
     RECT  32.783 1.962 39.623 19.719 ;
     RECT  39.623 2.07 41.027 19.719 ;
     RECT  41.027 2.07 46.247 19.638 ;
     RECT  46.247 2.07 46.795 19.53 ;
     RECT  46.795 1.998 47.551 19.53 ;
     RECT  47.551 1.962 50.531 19.53 ;
     RECT  50.531 1.962 52.763 19.449 ;
     RECT  52.763 1.998 54.563 19.449 ;
     RECT  54.563 2.106 65.075 19.449 ;
     RECT  65.075 2.151 75.6 19.449 ;
     RECT  75.6 2.421 75.612 19.179 ;
    LAYER M3 ;
     RECT  4.788 0.187 4.806 0.235 ;
     RECT  7.092 0.187 7.11 0.235 ;
     RECT  11.412 0.187 12.042 0.235 ;
     RECT  20.196 0.187 21.87 0.235 ;
     RECT  29.988 0.187 30.006 0.235 ;
     RECT  61.596 0.187 61.614 0.235 ;
     RECT  66.06 0.187 66.078 0.235 ;
     RECT  19.512 0.235 21.87 0.283 ;
     RECT  24.552 0.187 25.038 0.379 ;
     RECT  49.356 0.187 49.914 0.475 ;
     RECT  51.696 0.187 51.714 0.475 ;
     RECT  52.776 0.187 57.114 0.475 ;
     RECT  59.58 0.187 60.462 0.475 ;
     RECT  65.988 0.235 66.078 0.475 ;
     RECT  17.928 0.187 18.522 0.523 ;
     RECT  24.372 0.379 25.038 0.523 ;
     RECT  25.848 0.187 26.334 0.523 ;
     RECT  29.916 0.235 30.006 0.523 ;
     RECT  31.212 0.187 32.994 0.523 ;
     RECT  34.38 0.187 34.398 0.523 ;
     RECT  38.556 0.187 39.762 0.523 ;
     RECT  40.86 0.187 40.878 0.523 ;
     RECT  42.228 0.187 42.57 0.523 ;
     RECT  44.244 0.187 44.262 0.523 ;
     RECT  45.54 0.187 47.214 0.523 ;
     RECT  48.024 0.187 48.042 0.523 ;
     RECT  49.356 0.475 50.382 0.523 ;
     RECT  51.696 0.475 57.114 0.523 ;
     RECT  58.392 0.187 58.806 0.523 ;
     RECT  59.58 0.475 60.642 0.523 ;
     RECT  61.596 0.235 61.686 0.523 ;
     RECT  62.424 0.187 62.442 0.523 ;
     RECT  63.252 0.187 64.926 0.523 ;
     RECT  65.988 0.475 66.438 0.523 ;
     RECT  67.932 0.187 67.95 0.523 ;
     RECT  69.228 0.187 69.462 0.523 ;
     RECT  70.236 0.187 72.414 0.523 ;
     RECT  8.568 0.187 8.586 0.571 ;
     RECT  10.008 0.187 10.026 0.571 ;
     RECT  11.34 0.235 12.042 0.571 ;
     RECT  16.38 0.187 16.902 0.571 ;
     RECT  17.784 0.523 18.522 0.571 ;
     RECT  19.512 0.283 21.978 0.571 ;
     RECT  23.148 0.187 23.166 0.571 ;
     RECT  28.26 0.187 28.278 0.571 ;
     RECT  29.376 0.523 30.186 0.571 ;
     RECT  31.212 0.523 34.398 0.571 ;
     RECT  40.86 0.523 47.214 0.571 ;
     RECT  67.932 0.523 68.31 0.571 ;
     RECT  69.228 0.523 72.414 0.571 ;
     RECT  67.932 0.571 72.954 0.619 ;
     RECT  36.072 0.187 36.774 0.811 ;
     RECT  48.024 0.523 57.114 1.051 ;
     RECT  58.068 0.523 61.686 1.051 ;
     RECT  19.512 0.571 23.166 1.099 ;
     RECT  24.372 0.523 26.334 1.099 ;
     RECT  28.26 0.571 28.53 1.099 ;
     RECT  29.376 0.571 34.398 1.099 ;
     RECT  62.424 0.523 67.014 1.099 ;
     RECT  8.568 0.571 10.026 1.147 ;
     RECT  11.088 0.571 12.042 1.147 ;
     RECT  14.148 0.571 18.522 1.147 ;
     RECT  28.224 1.099 34.398 1.147 ;
     RECT  37.98 0.523 39.834 1.147 ;
     RECT  40.644 0.571 47.214 1.147 ;
     RECT  62.424 1.099 67.158 1.627 ;
     RECT  67.932 0.619 73.026 1.627 ;
     RECT  5.868 0.187 5.886 1.675 ;
     RECT  7.092 0.235 7.182 1.675 ;
     RECT  8.136 1.147 12.042 1.675 ;
     RECT  27.648 1.147 34.398 1.675 ;
     RECT  35.244 0.187 35.262 1.675 ;
     RECT  36.072 0.811 36.882 1.675 ;
     RECT  37.98 1.147 47.214 1.675 ;
     RECT  48.024 1.051 61.686 1.675 ;
     RECT  62.424 1.627 73.026 1.675 ;
     RECT  4.788 0.235 4.878 1.723 ;
     RECT  5.868 1.675 7.182 1.723 ;
     RECT  8.136 1.675 12.15 1.723 ;
     RECT  12.96 1.147 18.774 1.723 ;
     RECT  19.512 1.099 26.334 1.723 ;
     RECT  27.648 1.675 37.062 1.723 ;
     RECT  37.836 1.675 73.026 1.723 ;
     RECT  4.536 1.723 5.022 1.771 ;
     RECT  5.868 1.723 73.278 1.771 ;
     RECT  4.536 1.771 73.278 2.219 ;
     RECT  2.415 2.143 2.505 2.413 ;
     RECT  75.315 2.143 75.405 2.413 ;
     RECT  4.572 2.219 73.098 2.489 ;
     RECT  4.68 2.489 73.098 2.759 ;
     RECT  4.68 2.759 72.954 3.209 ;
     RECT  4.86 3.209 72.954 4.649 ;
     RECT  5.115 4.649 72.954 5.189 ;
     RECT  5.115 5.189 72.897 6.809 ;
     RECT  5.115 6.809 43.197 6.845 ;
     RECT  6.12 6.845 43.197 6.893 ;
     RECT  43.92 6.809 72.897 7.079 ;
     RECT  44.064 7.079 72.897 7.349 ;
     RECT  7.56 6.893 43.197 7.421 ;
     RECT  44.82 7.349 47.574 7.421 ;
     RECT  45.036 7.421 46.53 7.619 ;
     RECT  48.315 7.349 72.897 7.619 ;
     RECT  45.036 7.619 45.897 7.691 ;
     RECT  49.644 7.619 72.897 7.763 ;
     RECT  48.315 7.619 48.654 8.401 ;
     RECT  49.644 7.763 50.238 8.401 ;
     RECT  41.544 7.421 43.197 8.815 ;
     RECT  41.544 8.815 43.614 9.391 ;
     RECT  44.856 8.239 44.874 9.931 ;
     RECT  45.615 7.691 45.897 9.931 ;
     RECT  7.56 7.421 22.698 10.769 ;
     RECT  2.415 2.413 2.697 10.795 ;
     RECT  41.544 9.391 43.794 11.101 ;
     RECT  50.976 7.763 72.897 11.705 ;
     RECT  44.856 9.931 45.897 12.793 ;
     RECT  23.544 7.421 27.882 13.099 ;
     RECT  28.62 7.421 40.734 13.099 ;
     RECT  44.856 12.793 46.458 13.405 ;
     RECT  1.98 10.795 2.697 13.595 ;
     RECT  44.856 13.405 46.674 13.639 ;
     RECT  52.992 11.705 72.897 13.973 ;
     RECT  47.556 7.421 47.574 14.521 ;
     RECT  48.315 8.401 50.238 14.521 ;
     RECT  47.556 14.521 50.238 14.549 ;
     RECT  44.856 13.639 46.746 14.611 ;
     RECT  48.096 14.549 50.238 15.089 ;
     RECT  50.976 11.705 52.218 15.179 ;
     RECT  23.544 13.099 40.734 15.295 ;
     RECT  48.096 15.089 49.95 15.493 ;
     RECT  44.856 14.611 46.854 15.499 ;
     RECT  7.56 10.769 22.662 15.565 ;
     RECT  23.544 15.295 40.77 15.565 ;
     RECT  44.856 15.499 46.89 15.719 ;
     RECT  7.524 15.565 22.662 15.799 ;
     RECT  23.508 15.565 40.77 15.799 ;
     RECT  7.524 15.799 40.77 15.835 ;
     RECT  5.115 6.845 5.397 15.871 ;
     RECT  6.12 6.893 6.714 15.871 ;
     RECT  41.544 11.101 44.118 15.871 ;
     RECT  47.844 15.493 49.95 15.871 ;
     RECT  50.976 15.179 52.002 15.871 ;
     RECT  3.708 13.531 3.726 16.025 ;
     RECT  47.484 15.871 52.002 16.061 ;
     RECT  5.115 15.871 6.714 16.069 ;
     RECT  7.488 15.835 40.77 16.069 ;
     RECT  53.064 13.973 72.897 16.105 ;
     RECT  5.115 16.069 40.77 16.141 ;
     RECT  41.508 15.871 44.118 16.141 ;
     RECT  44.856 15.719 46.746 16.141 ;
     RECT  50.724 16.061 52.002 16.411 ;
     RECT  52.776 16.105 72.897 16.411 ;
     RECT  5.115 16.141 46.746 16.681 ;
     RECT  47.484 16.061 49.95 16.681 ;
     RECT  5.115 16.681 49.95 16.951 ;
     RECT  50.724 16.411 72.897 16.951 ;
     RECT  5.115 16.951 72.897 17.041 ;
     RECT  4.932 17.041 72.897 17.077 ;
     RECT  4.716 17.077 72.897 17.455 ;
     RECT  4.68 17.455 72.897 17.491 ;
     RECT  4.68 17.491 73.278 18.031 ;
     RECT  4.32 18.031 73.278 18.077 ;
     RECT  4.572 18.077 73.278 18.797 ;
     RECT  4.572 18.797 72.954 19.181 ;
     RECT  2.415 13.595 2.697 19.187 ;
     RECT  75.315 2.413 75.597 19.187 ;
     RECT  4.572 19.181 52.038 19.339 ;
     RECT  4.536 19.339 52.038 19.373 ;
     RECT  4.536 19.373 22.122 19.379 ;
     RECT  23.328 19.373 52.038 19.379 ;
     RECT  52.884 19.181 72.954 19.421 ;
     RECT  2.415 19.187 2.505 19.457 ;
     RECT  5.115 19.379 5.706 19.457 ;
     RECT  15.915 19.379 16.074 19.457 ;
     RECT  24.015 19.379 24.354 19.457 ;
     RECT  26.715 19.379 27.666 19.457 ;
     RECT  37.515 19.379 37.71 19.457 ;
     RECT  75.315 19.187 75.405 19.457 ;
     RECT  12.492 19.379 13.806 19.499 ;
     RECT  38.628 19.379 41.85 19.499 ;
     RECT  18.576 19.379 20.214 19.535 ;
     RECT  5.292 19.457 5.706 19.565 ;
     RECT  10.476 19.379 10.818 19.565 ;
     RECT  12.492 19.499 13.554 19.565 ;
     RECT  16.056 19.457 16.074 19.565 ;
     RECT  18.576 19.535 18.846 19.565 ;
     RECT  24.156 19.457 24.354 19.565 ;
     RECT  26.856 19.457 27.666 19.565 ;
     RECT  29.088 19.379 29.646 19.565 ;
     RECT  34.776 19.379 35.154 19.565 ;
     RECT  37.692 19.457 37.71 19.565 ;
     RECT  38.664 19.499 41.85 19.571 ;
     RECT  27.324 19.565 27.666 19.607 ;
     RECT  7.776 19.379 8.334 19.613 ;
     RECT  10.476 19.565 10.494 19.613 ;
     RECT  18.576 19.565 18.594 19.613 ;
     RECT  24.156 19.565 24.174 19.613 ;
     RECT  29.088 19.565 29.394 19.613 ;
     RECT  32.076 19.379 33.246 19.613 ;
     RECT  34.776 19.565 34.794 19.613 ;
     RECT  52.884 19.421 60.534 19.613 ;
     RECT  27.648 19.607 27.666 19.643 ;
     RECT  29.088 19.613 29.106 19.643 ;
     RECT  19.62 19.535 20.214 19.679 ;
     RECT  21.096 19.379 21.798 19.679 ;
     RECT  25.092 19.379 25.146 19.679 ;
     RECT  32.616 19.613 33.246 19.679 ;
     RECT  39.132 19.571 41.85 19.679 ;
     RECT  25.092 19.679 25.11 19.724 ;
     RECT  33.084 19.679 33.246 19.724 ;
     RECT  21.78 19.679 21.798 19.997 ;
     RECT  39.132 19.679 39.15 19.997 ;
     RECT  39.888 19.679 41.85 19.997 ;
     RECT  42.696 19.379 52.038 19.997 ;
     RECT  52.884 19.613 55.71 19.997 ;
     RECT  56.844 19.613 60.534 19.997 ;
     RECT  61.308 19.421 63.486 19.997 ;
     RECT  64.224 19.421 68.346 19.997 ;
     RECT  69.084 19.421 72.954 19.997 ;
     RECT  5.688 19.565 5.706 20.573 ;
     RECT  8.316 19.613 8.334 20.573 ;
     RECT  12.492 19.565 13.014 20.573 ;
     RECT  20.196 19.679 20.214 20.573 ;
     RECT  31.176 19.379 31.194 20.573 ;
     RECT  39.888 19.997 40.842 20.573 ;
     RECT  42.696 19.997 42.75 20.573 ;
     RECT  43.56 19.997 44.658 20.573 ;
     RECT  45.54 19.997 47.358 20.573 ;
     RECT  48.276 19.997 48.654 20.573 ;
     RECT  49.716 19.997 50.598 20.573 ;
     RECT  51.372 19.997 51.786 20.573 ;
     RECT  52.884 19.997 54.954 20.573 ;
     RECT  55.692 19.997 55.71 20.573 ;
     RECT  56.844 19.997 56.862 20.573 ;
     RECT  57.636 19.997 58.158 20.573 ;
     RECT  60.084 19.997 60.102 20.573 ;
     RECT  62.676 19.997 62.91 20.573 ;
     RECT  64.26 19.997 65.754 20.573 ;
     RECT  67.176 19.997 67.374 20.573 ;
     RECT  68.184 19.997 68.346 20.573 ;
     RECT  69.084 19.997 69.102 20.573 ;
     RECT  70.236 19.997 72.162 20.573 ;
     RECT  72.936 19.997 72.954 20.573 ;
     RECT  45.936 20.573 45.954 20.621 ;
     RECT  49.716 20.573 49.734 20.621 ;
     RECT  51.768 20.573 51.786 20.621 ;
     RECT  42.696 20.573 42.714 20.669 ;
     RECT  17.064 19.379 17.082 21.389 ;
     RECT  7.56 21.355 7.578 21.485 ;
     RECT  55.908 21.355 55.926 21.485 ;
    LAYER M4 ;
     RECT  2.408 2.148 2.512 19.452 ;
     RECT  2.512 2.418 2.704 19.182 ;
     RECT  4.309 18.048 4.549 18.072 ;
     RECT  4.501 19.344 4.549 19.368 ;
     RECT  4.549 18.048 4.705 19.368 ;
     RECT  4.645 0.192 4.805 0.216 ;
     RECT  4.805 0.192 4.889 0.264 ;
     RECT  4.481 1.728 5.108 1.752 ;
     RECT  4.705 17.088 5.108 19.368 ;
     RECT  5.108 1.728 5.269 19.452 ;
     RECT  5.269 1.728 5.356 19.56 ;
     RECT  5.356 1.728 5.404 19.368 ;
     RECT  5.404 15.744 5.555 19.368 ;
     RECT  5.404 1.728 5.725 1.896 ;
     RECT  5.677 20.544 5.795 20.568 ;
     RECT  5.725 1.728 6.476 1.8 ;
     RECT  6.476 1.68 6.563 1.8 ;
     RECT  6.563 1.728 6.764 1.8 ;
     RECT  4.889 0.192 7.109 0.216 ;
     RECT  7.109 0.192 7.121 0.264 ;
     RECT  7.121 0.24 7.193 0.264 ;
     RECT  5.555 15.744 7.297 15.768 ;
     RECT  5.555 16.848 7.297 19.368 ;
     RECT  6.764 1.728 7.405 2.28 ;
     RECT  7.333 5.184 7.441 5.208 ;
     RECT  7.405 6.864 7.477 6.888 ;
     RECT  7.525 21.36 7.549 21.384 ;
     RECT  7.477 6.864 7.621 7.368 ;
     RECT  7.549 21.36 7.633 21.48 ;
     RECT  7.297 15.744 7.669 19.368 ;
     RECT  7.669 15.552 7.724 19.368 ;
     RECT  7.405 1.728 7.808 3.096 ;
     RECT  7.441 4.752 7.808 5.208 ;
     RECT  7.621 6.624 7.808 7.368 ;
     RECT  7.724 15.552 7.808 19.608 ;
     RECT  7.808 1.728 7.811 19.608 ;
     RECT  7.811 1.728 8.005 19.56 ;
     RECT  8.005 1.152 8.104 19.56 ;
     RECT  8.104 1.152 8.165 4.776 ;
     RECT  8.104 15.504 8.243 19.56 ;
     RECT  8.485 0.192 8.597 0.6 ;
     RECT  8.305 20.544 8.819 20.568 ;
     RECT  8.165 1.728 9.097 4.776 ;
     RECT  8.104 6 9.097 7.368 ;
     RECT  8.597 0.576 9.157 0.6 ;
     RECT  9.097 1.728 9.157 7.368 ;
     RECT  9.157 0.576 9.245 7.368 ;
     RECT  9.245 0.576 9.953 0.6 ;
     RECT  9.953 0.192 10.037 0.6 ;
     RECT  8.243 15.504 10.465 19.368 ;
     RECT  10.037 0.576 10.501 0.6 ;
     RECT  9.245 1.68 10.501 7.368 ;
     RECT  10.501 0.576 10.508 7.368 ;
     RECT  10.465 15.504 10.508 19.608 ;
     RECT  10.508 0.576 10.595 19.608 ;
     RECT  10.595 0.576 10.685 19.56 ;
     RECT  10.685 1.728 10.804 19.56 ;
     RECT  10.804 15.504 10.835 19.56 ;
     RECT  10.685 0.576 11.117 0.6 ;
     RECT  11.173 0.192 11.369 0.264 ;
     RECT  11.369 0.192 12.053 0.216 ;
     RECT  10.804 1.728 12.092 7.368 ;
     RECT  12.092 1.68 12.805 7.368 ;
     RECT  12.805 1.152 13.208 7.368 ;
     RECT  10.835 15.504 13.208 19.368 ;
     RECT  12.476 20.544 13.331 20.568 ;
     RECT  13.208 1.152 13.484 19.452 ;
     RECT  13.484 1.152 13.504 19.56 ;
     RECT  13.504 15.552 13.571 19.56 ;
     RECT  13.504 1.152 13.673 7.416 ;
     RECT  13.673 1.152 13.813 7.368 ;
     RECT  13.813 0.576 14.141 7.368 ;
     RECT  13.571 15.552 14.569 19.368 ;
     RECT  14.569 15.504 14.861 19.368 ;
     RECT  14.141 1.728 15.908 7.368 ;
     RECT  14.861 15.552 15.908 19.368 ;
     RECT  15.908 1.728 16.028 19.452 ;
     RECT  16.028 1.728 16.115 19.56 ;
     RECT  14.141 0.576 16.165 0.6 ;
     RECT  16.115 1.728 16.165 19.368 ;
     RECT  16.165 0.576 16.204 19.368 ;
     RECT  16.204 0.576 16.309 7.368 ;
     RECT  16.309 0.192 16.337 7.368 ;
     RECT  16.204 15.408 17.129 19.368 ;
     RECT  17.036 21.36 17.157 21.384 ;
     RECT  17.129 15.552 18.349 19.368 ;
     RECT  18.349 15.312 18.524 19.368 ;
     RECT  16.337 1.728 18.608 7.368 ;
     RECT  18.524 15.312 18.608 19.608 ;
     RECT  18.608 1.728 18.611 19.608 ;
     RECT  16.337 0.192 18.661 0.6 ;
     RECT  18.611 1.728 18.661 19.56 ;
     RECT  18.661 0.192 18.785 19.56 ;
     RECT  18.785 1.728 18.892 19.56 ;
     RECT  18.892 1.728 18.904 19.368 ;
     RECT  18.785 0.192 19.043 0.312 ;
     RECT  18.904 15.312 19.793 19.368 ;
     RECT  18.904 1.728 20.261 7.368 ;
     RECT  20.261 1.776 20.477 7.368 ;
     RECT  20.185 20.544 20.627 20.568 ;
     RECT  19.043 0.192 21.157 0.264 ;
     RECT  20.477 2.148 21.308 7.368 ;
     RECT  19.793 15.408 21.308 19.368 ;
     RECT  21.308 2.148 21.349 19.452 ;
     RECT  21.349 2.148 21.481 19.608 ;
     RECT  21.481 1.728 21.604 19.608 ;
     RECT  21.157 21.36 21.635 21.384 ;
     RECT  21.604 15.456 21.769 19.608 ;
     RECT  21.157 0.192 21.881 0.312 ;
     RECT  21.881 0.288 21.989 0.312 ;
     RECT  21.769 15.456 22.355 19.992 ;
     RECT  22.453 0.576 22.637 0.6 ;
     RECT  21.604 1.728 22.781 7.368 ;
     RECT  23.093 0.192 23.756 0.216 ;
     RECT  22.781 1.776 23.756 7.368 ;
     RECT  23.756 0.192 23.797 7.368 ;
     RECT  23.797 0.192 23.843 7.416 ;
     RECT  23.843 1.728 24.008 7.416 ;
     RECT  22.355 15.456 24.008 19.368 ;
     RECT  24.008 1.728 24.085 19.452 ;
     RECT  24.085 1.728 24.185 19.608 ;
     RECT  24.185 1.728 24.304 19.56 ;
     RECT  24.304 15.456 24.371 19.56 ;
     RECT  24.304 13.104 24.515 13.128 ;
     RECT  23.843 0.192 25.244 0.408 ;
     RECT  25.244 0.192 25.331 0.552 ;
     RECT  24.371 15.456 25.369 19.368 ;
     RECT  25.331 0.192 26.345 0.216 ;
     RECT  24.304 1.728 26.708 7.416 ;
     RECT  25.369 15.312 26.708 19.368 ;
     RECT  26.708 1.728 26.821 19.452 ;
     RECT  26.821 1.392 26.828 19.452 ;
     RECT  26.828 1.392 26.915 19.56 ;
     RECT  26.915 1.392 27.004 19.368 ;
     RECT  27.004 1.392 27.157 7.416 ;
     RECT  27.157 0.816 28.205 7.416 ;
     RECT  28.205 0.192 28.289 7.416 ;
     RECT  28.289 0.576 29.324 7.416 ;
     RECT  27.004 15.312 29.324 19.368 ;
     RECT  29.324 0.528 29.408 7.416 ;
     RECT  29.324 15.312 29.408 19.608 ;
     RECT  29.408 0.528 29.411 19.608 ;
     RECT  29.411 0.528 29.692 19.56 ;
     RECT  29.692 0.528 29.701 19.368 ;
     RECT  29.701 0.192 29.704 19.368 ;
     RECT  29.704 0.192 30.017 7.416 ;
     RECT  30.017 0.528 31.157 7.416 ;
     RECT  31.165 20.544 31.427 20.568 ;
     RECT  29.704 15.456 32.065 19.368 ;
     RECT  31.157 0.192 32.108 7.416 ;
     RECT  32.065 15.456 32.108 19.608 ;
     RECT  32.108 0.192 32.195 19.608 ;
     RECT  32.195 0.192 32.404 19.56 ;
     RECT  32.404 0.192 33.005 7.416 ;
     RECT  32.404 15.408 33.221 19.56 ;
     RECT  33.005 0.528 33.395 7.416 ;
     RECT  33.221 15.408 33.461 19.368 ;
     RECT  33.461 15.36 33.721 19.368 ;
     RECT  33.395 0.528 34.325 1.128 ;
     RECT  34.325 0.192 34.585 1.128 ;
     RECT  33.395 2.256 34.585 7.416 ;
     RECT  33.721 14.976 34.765 19.368 ;
     RECT  34.585 0.192 34.808 7.416 ;
     RECT  34.765 14.976 34.808 19.608 ;
     RECT  34.808 0.192 34.931 19.608 ;
     RECT  34.931 0.192 35.104 19.56 ;
     RECT  35.104 14.736 35.171 19.56 ;
     RECT  35.171 14.736 35.315 19.368 ;
     RECT  35.315 15.36 36.533 19.368 ;
     RECT  35.104 0.192 36.785 7.416 ;
     RECT  36.785 0.288 36.893 7.416 ;
     RECT  36.893 1.68 37.508 7.416 ;
     RECT  36.533 15.408 37.508 19.368 ;
     RECT  37.508 1.68 37.669 19.452 ;
     RECT  37.669 1.68 37.756 19.56 ;
     RECT  37.756 1.68 37.804 19.368 ;
     RECT  36.893 0.288 37.964 0.312 ;
     RECT  37.964 0.288 38.197 0.552 ;
     RECT  37.804 1.68 38.197 7.416 ;
     RECT  38.197 0.288 38.501 7.416 ;
     RECT  37.804 15.456 39.061 19.368 ;
     RECT  38.501 0.192 39.773 7.416 ;
     RECT  39.061 15.456 39.829 19.992 ;
     RECT  39.773 0.528 40.208 7.416 ;
     RECT  39.829 15.456 40.208 20.568 ;
     RECT  40.208 0.528 40.504 20.568 ;
     RECT  40.504 0.528 40.805 2.568 ;
     RECT  40.504 15.504 40.883 20.568 ;
     RECT  40.805 0.192 40.889 2.568 ;
     RECT  40.883 15.504 41.884 19.992 ;
     RECT  40.889 0.528 42.001 2.568 ;
     RECT  40.504 3.648 42.001 7.416 ;
     RECT  42.001 0.528 42.173 7.416 ;
     RECT  42.173 0.192 42.581 7.416 ;
     RECT  42.565 20.544 42.685 20.568 ;
     RECT  42.685 20.544 42.851 20.664 ;
     RECT  42.581 0.528 42.908 7.416 ;
     RECT  41.884 15.504 42.908 19.368 ;
     RECT  42.908 0.528 43.045 19.452 ;
     RECT  42.851 20.544 43.045 20.568 ;
     RECT  43.045 0.528 43.204 20.568 ;
     RECT  43.204 15.504 44.021 20.568 ;
     RECT  43.204 0.528 44.189 2.568 ;
     RECT  44.189 0.192 44.273 2.568 ;
     RECT  44.273 0.528 44.387 2.568 ;
     RECT  44.387 1.728 44.845 2.568 ;
     RECT  43.204 3.648 44.845 7.416 ;
     RECT  44.845 1.728 45.025 7.416 ;
     RECT  44.387 0.528 45.065 0.6 ;
     RECT  45.065 0.528 45.485 0.552 ;
     RECT  44.021 17.136 45.568 20.568 ;
     RECT  45.025 1.728 45.608 7.656 ;
     RECT  44.021 15.504 45.608 16.008 ;
     RECT  45.568 17.136 45.608 20.616 ;
     RECT  45.608 1.728 45.901 20.616 ;
     RECT  45.901 2.418 45.904 20.616 ;
     RECT  45.904 17.136 45.965 20.616 ;
     RECT  45.485 0.192 46.46 0.552 ;
     RECT  46.46 0.192 46.547 1.128 ;
     RECT  46.547 0.192 46.883 0.552 ;
     RECT  45.904 2.688 46.997 7.416 ;
     RECT  46.997 1.68 47.411 7.416 ;
     RECT  47.411 1.728 47.657 7.416 ;
     RECT  47.657 1.776 47.765 7.416 ;
     RECT  46.883 0.192 48.053 0.216 ;
     RECT  47.765 2.148 48.308 7.416 ;
     RECT  45.904 15.504 48.308 16.008 ;
     RECT  45.965 17.136 48.308 20.568 ;
     RECT  48.193 0.528 48.517 0.552 ;
     RECT  48.308 2.148 48.604 20.568 ;
     RECT  48.517 0.528 48.661 0.6 ;
     RECT  48.604 17.136 48.737 20.568 ;
     RECT  48.661 0.528 48.773 0.648 ;
     RECT  48.604 3.6 48.953 7.416 ;
     RECT  48.773 0.528 49.301 0.552 ;
     RECT  48.737 17.376 49.705 20.568 ;
     RECT  49.705 17.376 49.907 20.616 ;
     RECT  49.301 0.192 49.925 0.552 ;
     RECT  48.977 1.728 50.051 1.752 ;
     RECT  48.953 3.6 50.065 7.368 ;
     RECT  49.925 0.48 50.197 0.552 ;
     RECT  50.065 3.408 50.641 7.368 ;
     RECT  48.604 15.504 50.713 16.008 ;
     RECT  49.907 17.376 50.713 20.568 ;
     RECT  50.197 0.48 50.929 0.6 ;
     RECT  50.641 3.408 51.008 7.416 ;
     RECT  50.713 15.504 51.008 20.568 ;
     RECT  50.929 0.48 51.107 1.128 ;
     RECT  51.008 2.148 51.304 20.568 ;
     RECT  51.505 1.728 51.635 1.752 ;
     RECT  51.107 0.48 51.685 0.552 ;
     RECT  51.304 17.376 51.723 20.568 ;
     RECT  51.723 17.376 51.923 20.616 ;
     RECT  51.304 15.504 51.941 16.008 ;
     RECT  51.304 2.832 51.971 6.12 ;
     RECT  51.685 0.192 52.069 0.552 ;
     RECT  52.069 0.192 52.117 0.6 ;
     RECT  51.923 17.376 52.163 20.568 ;
     RECT  52.117 0.192 52.307 1.128 ;
     RECT  51.971 3.696 52.733 6.12 ;
     RECT  52.163 17.376 53.125 19.176 ;
     RECT  52.163 20.544 53.125 20.568 ;
     RECT  52.307 0.192 53.137 0.6 ;
     RECT  53.161 1.68 53.708 1.704 ;
     RECT  52.733 4.128 53.708 6.12 ;
     RECT  51.304 7.104 53.708 7.368 ;
     RECT  51.941 15.984 53.708 16.008 ;
     RECT  53.125 17.376 53.708 20.568 ;
     RECT  53.708 1.68 54.004 20.568 ;
     RECT  54.004 17.376 54.065 20.568 ;
     RECT  54.004 1.68 54.275 2.28 ;
     RECT  54.275 1.68 54.467 1.752 ;
     RECT  53.137 0.192 54.493 0.264 ;
     RECT  54.493 0.192 54.709 0.552 ;
     RECT  54.004 4.368 54.929 7.368 ;
     RECT  54.709 0.192 54.947 1.128 ;
     RECT  54.065 17.376 55.069 19.032 ;
     RECT  54.065 20.544 55.069 20.568 ;
     RECT  55.069 17.376 55.253 20.568 ;
     RECT  55.253 17.424 55.721 20.568 ;
     RECT  55.853 21.36 55.937 21.48 ;
     RECT  55.937 21.36 55.955 21.384 ;
     RECT  55.573 2.256 55.969 2.28 ;
     RECT  55.969 2.256 56.041 2.856 ;
     RECT  54.947 0.192 56.113 0.552 ;
     RECT  56.041 1.728 56.113 2.856 ;
     RECT  56.113 0.192 56.291 2.856 ;
     RECT  54.929 4.368 56.293 6.072 ;
     RECT  56.291 2.148 56.408 2.856 ;
     RECT  56.293 4.224 56.408 6.072 ;
     RECT  54.929 7.104 56.408 7.368 ;
     RECT  54.004 15.984 56.408 16.008 ;
     RECT  55.721 17.424 56.408 19.608 ;
     RECT  56.408 2.148 56.512 19.608 ;
     RECT  56.512 2.256 56.704 19.608 ;
     RECT  56.704 18.192 56.819 19.608 ;
     RECT  56.819 18.192 56.845 18.792 ;
     RECT  56.291 0.192 57.125 1.128 ;
     RECT  56.704 4.224 57.299 7.368 ;
     RECT  56.704 15.984 57.341 16.008 ;
     RECT  56.845 18.192 57.413 18.552 ;
     RECT  57.125 0.528 57.589 1.128 ;
     RECT  56.704 2.256 57.589 2.376 ;
     RECT  57.589 0.528 57.971 2.376 ;
     RECT  56.828 19.968 58.211 20.568 ;
     RECT  57.299 4.224 58.309 6.072 ;
     RECT  57.971 2.256 58.345 2.376 ;
     RECT  57.971 0.528 58.381 1.08 ;
     RECT  58.309 3.84 58.525 6.072 ;
     RECT  57.299 7.104 58.525 7.368 ;
     RECT  57.413 18.192 58.625 18.504 ;
     RECT  58.381 0.192 59.029 1.08 ;
     RECT  58.345 2.256 59.108 2.856 ;
     RECT  58.525 3.84 59.108 7.368 ;
     RECT  58.625 18.192 59.108 18.84 ;
     RECT  58.211 19.968 59.108 19.992 ;
     RECT  59.029 0.192 59.381 1.128 ;
     RECT  59.108 2.148 59.381 19.992 ;
     RECT  59.381 0.192 59.404 19.992 ;
     RECT  59.404 0.192 59.465 2.856 ;
     RECT  59.404 3.84 59.645 3.864 ;
     RECT  59.404 18.192 59.699 18.792 ;
     RECT  59.465 0.192 59.939 1.128 ;
     RECT  59.404 19.968 60.073 19.992 ;
     RECT  59.465 2.16 60.131 2.856 ;
     RECT  60.073 19.968 60.179 20.568 ;
     RECT  59.404 4.992 60.401 7.368 ;
     RECT  59.939 0.192 60.473 0.6 ;
     RECT  60.131 2.16 60.577 2.376 ;
     RECT  60.473 0.48 60.625 0.6 ;
     RECT  59.699 18.192 60.661 18.504 ;
     RECT  60.179 19.968 60.661 19.992 ;
     RECT  60.577 1.68 60.755 2.376 ;
     RECT  60.625 0.48 61.541 0.552 ;
     RECT  60.755 1.728 61.765 2.376 ;
     RECT  61.765 1.68 61.808 2.376 ;
     RECT  60.401 4.992 61.808 6.072 ;
     RECT  60.401 7.104 61.808 7.368 ;
     RECT  60.661 18.192 61.808 19.992 ;
     RECT  61.808 1.68 62.104 19.992 ;
     RECT  62.104 1.68 62.291 2.28 ;
     RECT  62.291 2.256 62.627 2.28 ;
     RECT  61.541 0.192 62.665 0.552 ;
     RECT  62.104 19.968 62.665 19.992 ;
     RECT  62.665 19.968 62.677 20.568 ;
     RECT  62.104 4.896 62.741 6.072 ;
     RECT  62.677 19.968 62.819 21.384 ;
     RECT  62.819 19.968 62.963 20.568 ;
     RECT  62.665 0.192 63.107 1.272 ;
     RECT  62.741 4.992 63.137 6.072 ;
     RECT  63.133 3.072 63.281 3.096 ;
     RECT  62.963 19.968 63.644 19.992 ;
     RECT  62.104 18.192 63.884 18.216 ;
     RECT  63.644 19.392 64.249 19.992 ;
     RECT  63.107 0.192 64.477 0.6 ;
     RECT  63.997 2.256 64.508 2.28 ;
     RECT  63.137 4.992 64.508 5.016 ;
     RECT  63.137 6.048 64.508 6.072 ;
     RECT  62.104 7.104 64.508 7.368 ;
     RECT  63.884 18.192 64.508 18.264 ;
     RECT  64.249 19.392 64.508 20.568 ;
     RECT  64.508 2.148 64.804 20.568 ;
     RECT  64.477 0.192 64.937 0.552 ;
     RECT  64.969 1.728 65.459 1.752 ;
     RECT  64.804 6.048 65.549 6.072 ;
     RECT  64.804 2.832 65.603 2.856 ;
     RECT  64.804 19.968 65.788 20.568 ;
     RECT  64.937 0.528 65.977 0.552 ;
     RECT  65.977 0.24 66.005 0.552 ;
     RECT  65.941 18.24 66.028 18.264 ;
     RECT  66.005 0.192 66.089 0.552 ;
     RECT  66.089 0.24 66.275 0.552 ;
     RECT  66.275 0.48 66.697 0.552 ;
     RECT  66.697 0.48 67.129 0.6 ;
     RECT  65.653 1.68 67.129 1.704 ;
     RECT  65.788 19.968 67.148 19.992 ;
     RECT  67.129 0.48 67.208 1.704 ;
     RECT  66.661 2.832 67.208 2.856 ;
     RECT  64.804 4.992 67.208 5.016 ;
     RECT  64.804 7.104 67.208 7.368 ;
     RECT  66.913 18.768 67.208 18.792 ;
     RECT  67.148 19.968 67.208 20.568 ;
     RECT  67.208 0.48 67.427 20.568 ;
     RECT  67.427 1.632 67.504 20.568 ;
     RECT  67.504 19.968 67.715 20.568 ;
     RECT  67.427 0.48 67.877 0.552 ;
     RECT  67.877 0.192 67.961 0.552 ;
     RECT  67.504 18.768 68.041 18.792 ;
     RECT  67.504 1.632 68.099 2.28 ;
     RECT  68.099 1.68 68.435 2.28 ;
     RECT  67.961 0.528 68.705 0.552 ;
     RECT  68.636 19.392 68.723 19.416 ;
     RECT  68.705 0.528 68.789 0.6 ;
     RECT  68.435 1.68 69.107 1.752 ;
     RECT  67.715 20.544 69.109 20.568 ;
     RECT  69.109 19.968 69.113 20.568 ;
     RECT  68.789 0.528 69.173 0.552 ;
     RECT  69.113 19.968 69.781 19.992 ;
     RECT  69.107 1.728 69.908 1.752 ;
     RECT  67.504 4.992 69.908 5.016 ;
     RECT  67.504 7.104 69.908 7.368 ;
     RECT  69.781 18.24 69.908 18.264 ;
     RECT  69.781 19.584 69.908 19.992 ;
     RECT  69.908 1.728 70.019 19.992 ;
     RECT  70.019 1.728 70.204 19.416 ;
     RECT  70.204 6.864 70.301 7.128 ;
     RECT  70.204 1.728 70.364 2.28 ;
     RECT  70.301 6.864 70.445 6.888 ;
     RECT  70.204 18.768 70.499 19.416 ;
     RECT  70.364 1.68 70.595 2.28 ;
     RECT  69.173 0.192 70.729 0.552 ;
     RECT  70.499 18.768 70.993 18.792 ;
     RECT  70.729 0.192 71.269 0.6 ;
     RECT  70.595 1.68 71.269 1.704 ;
     RECT  70.213 20.544 71.42 20.568 ;
     RECT  70.204 4.992 71.453 5.016 ;
     RECT  71.269 0.192 71.603 1.704 ;
     RECT  71.603 1.68 72.025 1.704 ;
     RECT  72.025 1.68 72.421 1.752 ;
     RECT  71.603 0.192 72.425 0.552 ;
     RECT  72.421 1.68 72.608 2.04 ;
     RECT  71.9 18.24 72.608 18.264 ;
     RECT  71.42 19.968 72.608 20.568 ;
     RECT  72.608 1.68 72.611 20.568 ;
     RECT  72.611 1.728 72.893 20.568 ;
     RECT  72.893 1.728 72.904 19.182 ;
     RECT  72.881 0.576 72.964 0.6 ;
     RECT  72.964 0.576 72.965 0.648 ;
     RECT  72.893 20.544 72.995 20.568 ;
     RECT  72.965 0.624 73.091 0.648 ;
     RECT  72.904 1.728 73.289 1.752 ;
     RECT  72.904 18.768 73.289 18.792 ;
     RECT  75.308 2.148 75.412 19.452 ;
     RECT  75.412 2.418 75.604 19.182 ;
    LAYER M5 ;
     RECT  4.536 0.144 4.656 0.192 ;
     RECT  4.68 0.144 4.848 0.192 ;
     RECT  4.872 0.144 4.992 0.192 ;
     RECT  5.016 0.144 5.184 0.192 ;
     RECT  5.208 0.144 5.328 0.192 ;
     RECT  5.352 0.144 5.52 0.192 ;
     RECT  5.544 0.144 5.664 0.192 ;
     RECT  5.688 0.144 5.856 0.192 ;
     RECT  5.88 0.144 6 0.192 ;
     RECT  6.024 0.144 6.192 0.192 ;
     RECT  6.216 0.144 6.336 0.192 ;
     RECT  6.36 0.144 6.528 0.192 ;
     RECT  6.552 0.144 6.672 0.192 ;
     RECT  6.696 0.144 6.816 0.192 ;
     RECT  6.84 0.144 7.008 0.192 ;
     RECT  7.032 0.144 7.152 0.192 ;
     RECT  7.176 0.144 7.344 0.192 ;
     RECT  7.368 0.144 7.488 0.192 ;
     RECT  7.512 0.144 7.68 0.192 ;
     RECT  7.704 0.144 7.824 0.192 ;
     RECT  7.848 0.144 8.016 0.192 ;
     RECT  8.04 0.144 8.16 0.192 ;
     RECT  8.184 0.144 8.352 0.192 ;
     RECT  8.376 0.144 8.496 0.192 ;
     RECT  8.52 0.144 8.688 0.192 ;
     RECT  8.712 0.144 8.832 0.192 ;
     RECT  8.856 0.144 9.024 0.192 ;
     RECT  9.048 0.144 9.168 0.192 ;
     RECT  9.192 0.144 9.312 0.192 ;
     RECT  9.336 0.144 9.504 0.192 ;
     RECT  9.528 0.144 9.648 0.192 ;
     RECT  9.672 0.144 9.84 0.192 ;
     RECT  9.864 0.144 9.984 0.192 ;
     RECT  10.008 0.144 10.176 0.192 ;
     RECT  10.2 0.144 10.32 0.192 ;
     RECT  10.344 0.144 10.512 0.192 ;
     RECT  10.536 0.144 10.656 0.192 ;
     RECT  10.68 0.144 10.848 0.192 ;
     RECT  10.872 0.144 10.992 0.192 ;
     RECT  11.016 0.144 11.184 0.192 ;
     RECT  11.208 0.144 11.328 0.192 ;
     RECT  11.352 0.144 11.52 0.192 ;
     RECT  11.544 0.144 11.664 0.192 ;
     RECT  11.688 0.144 11.856 0.192 ;
     RECT  11.88 0.144 12 0.192 ;
     RECT  12.024 0.144 12.144 0.192 ;
     RECT  12.168 0.144 12.336 0.192 ;
     RECT  12.36 0.144 12.48 0.192 ;
     RECT  12.504 0.144 12.672 0.192 ;
     RECT  12.696 0.144 12.816 0.192 ;
     RECT  12.84 0.144 13.008 0.192 ;
     RECT  13.032 0.144 13.152 0.192 ;
     RECT  13.176 0.144 13.344 0.192 ;
     RECT  13.368 0.144 13.488 0.192 ;
     RECT  13.512 0.144 13.68 0.192 ;
     RECT  13.704 0.144 13.824 0.192 ;
     RECT  13.848 0.144 14.016 0.192 ;
     RECT  14.04 0.144 14.16 0.192 ;
     RECT  14.184 0.144 14.352 0.192 ;
     RECT  14.376 0.144 14.496 0.192 ;
     RECT  14.52 0.144 14.64 0.192 ;
     RECT  14.664 0.144 14.832 0.192 ;
     RECT  14.856 0.144 14.976 0.192 ;
     RECT  15 0.144 15.168 0.192 ;
     RECT  15.192 0.144 15.312 0.192 ;
     RECT  15.336 0.144 15.504 0.192 ;
     RECT  15.528 0.144 15.648 0.192 ;
     RECT  15.672 0.144 15.84 0.192 ;
     RECT  15.864 0.144 15.984 0.192 ;
     RECT  16.008 0.144 16.176 0.192 ;
     RECT  16.2 0.144 16.32 0.192 ;
     RECT  16.344 0.144 16.512 0.192 ;
     RECT  16.536 0.144 16.656 0.192 ;
     RECT  16.68 0.144 16.848 0.192 ;
     RECT  16.872 0.144 16.992 0.192 ;
     RECT  17.016 0.144 17.136 0.192 ;
     RECT  17.16 0.144 17.328 0.192 ;
     RECT  17.352 0.144 17.472 0.192 ;
     RECT  17.496 0.144 17.664 0.192 ;
     RECT  17.688 0.144 17.808 0.192 ;
     RECT  17.832 0.144 18 0.192 ;
     RECT  18.024 0.144 18.144 0.192 ;
     RECT  18.168 0.144 18.336 0.192 ;
     RECT  18.36 0.144 18.48 0.192 ;
     RECT  18.504 0.144 18.672 0.192 ;
     RECT  18.696 0.144 18.816 0.192 ;
     RECT  18.84 0.144 19.008 0.192 ;
     RECT  19.032 0.144 19.152 0.192 ;
     RECT  19.176 0.144 19.344 0.192 ;
     RECT  19.368 0.144 19.488 0.192 ;
     RECT  19.512 0.144 19.68 0.192 ;
     RECT  19.704 0.144 19.824 0.192 ;
     RECT  19.848 0.144 19.968 0.192 ;
     RECT  19.992 0.144 20.16 0.192 ;
     RECT  20.184 0.144 20.304 0.192 ;
     RECT  20.328 0.144 20.496 0.192 ;
     RECT  20.52 0.144 20.64 0.192 ;
     RECT  20.664 0.144 20.832 0.192 ;
     RECT  20.856 0.144 20.976 0.192 ;
     RECT  21 0.144 21.168 0.192 ;
     RECT  21.192 0.144 21.312 0.192 ;
     RECT  21.336 0.144 21.504 0.192 ;
     RECT  21.528 0.144 21.648 0.192 ;
     RECT  21.672 0.144 21.84 0.192 ;
     RECT  21.864 0.144 21.984 0.192 ;
     RECT  22.008 0.144 22.176 0.192 ;
     RECT  22.2 0.144 22.32 0.192 ;
     RECT  22.344 0.144 22.464 0.192 ;
     RECT  22.488 0.144 22.656 0.192 ;
     RECT  22.68 0.144 22.8 0.192 ;
     RECT  22.824 0.144 22.992 0.192 ;
     RECT  23.016 0.144 23.136 0.192 ;
     RECT  23.16 0.144 23.328 0.192 ;
     RECT  23.352 0.144 23.472 0.192 ;
     RECT  23.496 0.144 23.664 0.192 ;
     RECT  23.688 0.144 23.808 0.192 ;
     RECT  23.832 0.144 24 0.192 ;
     RECT  24.024 0.144 24.144 0.192 ;
     RECT  24.168 0.144 24.336 0.192 ;
     RECT  24.36 0.144 24.48 0.192 ;
     RECT  24.504 0.144 24.672 0.192 ;
     RECT  24.696 0.144 24.816 0.192 ;
     RECT  24.84 0.144 24.96 0.192 ;
     RECT  24.984 0.144 25.152 0.192 ;
     RECT  25.176 0.144 25.296 0.192 ;
     RECT  25.32 0.144 25.488 0.192 ;
     RECT  25.512 0.144 25.632 0.192 ;
     RECT  25.656 0.144 25.824 0.192 ;
     RECT  25.848 0.144 25.968 0.192 ;
     RECT  25.992 0.144 26.16 0.192 ;
     RECT  26.184 0.144 26.304 0.192 ;
     RECT  26.328 0.144 26.496 0.192 ;
     RECT  26.52 0.144 26.64 0.192 ;
     RECT  26.664 0.144 26.832 0.192 ;
     RECT  26.856 0.144 26.976 0.192 ;
     RECT  27 0.144 27.168 0.192 ;
     RECT  27.192 0.144 27.552 0.192 ;
     RECT  27.576 0.144 27.696 0.192 ;
     RECT  27.72 0.144 27.888 0.192 ;
     RECT  27.912 0.144 28.032 0.192 ;
     RECT  28.056 0.144 28.224 0.192 ;
     RECT  28.248 0.144 28.368 0.192 ;
     RECT  28.392 0.144 28.56 0.192 ;
     RECT  28.584 0.144 28.704 0.192 ;
     RECT  28.728 0.144 28.896 0.192 ;
     RECT  28.92 0.144 29.04 0.192 ;
     RECT  29.064 0.144 29.232 0.192 ;
     RECT  29.256 0.144 29.376 0.192 ;
     RECT  29.4 0.144 29.568 0.192 ;
     RECT  29.592 0.144 29.712 0.192 ;
     RECT  29.736 0.144 29.856 0.192 ;
     RECT  29.88 0.144 30.048 0.192 ;
     RECT  30.072 0.144 30.192 0.192 ;
     RECT  30.216 0.144 30.384 0.192 ;
     RECT  30.408 0.144 30.528 0.192 ;
     RECT  30.552 0.144 30.72 0.192 ;
     RECT  30.744 0.144 30.864 0.192 ;
     RECT  30.888 0.144 31.056 0.192 ;
     RECT  31.08 0.144 31.2 0.192 ;
     RECT  31.224 0.144 31.392 0.192 ;
     RECT  31.416 0.144 31.536 0.192 ;
     RECT  31.56 0.144 31.728 0.192 ;
     RECT  31.752 0.144 31.872 0.192 ;
     RECT  31.896 0.144 32.064 0.192 ;
     RECT  32.088 0.144 32.208 0.192 ;
     RECT  32.232 0.144 32.352 0.192 ;
     RECT  32.376 0.144 32.544 0.192 ;
     RECT  32.568 0.144 32.688 0.192 ;
     RECT  32.712 0.144 32.88 0.192 ;
     RECT  32.904 0.144 33.024 0.192 ;
     RECT  33.048 0.144 33.216 0.192 ;
     RECT  33.24 0.144 33.36 0.192 ;
     RECT  33.384 0.144 33.552 0.192 ;
     RECT  33.576 0.144 33.696 0.192 ;
     RECT  33.72 0.144 33.888 0.192 ;
     RECT  33.912 0.144 34.032 0.192 ;
     RECT  34.056 0.144 34.224 0.192 ;
     RECT  34.248 0.144 34.368 0.192 ;
     RECT  34.392 0.144 34.56 0.192 ;
     RECT  34.584 0.144 34.704 0.192 ;
     RECT  34.728 0.144 34.896 0.192 ;
     RECT  34.92 0.144 35.04 0.192 ;
     RECT  35.064 0.144 35.184 0.192 ;
     RECT  35.208 0.144 35.376 0.192 ;
     RECT  35.4 0.144 35.52 0.192 ;
     RECT  35.544 0.144 35.712 0.192 ;
     RECT  35.736 0.144 35.856 0.192 ;
     RECT  35.88 0.144 36.048 0.192 ;
     RECT  36.072 0.144 36.192 0.192 ;
     RECT  36.216 0.144 36.384 0.192 ;
     RECT  36.408 0.144 36.528 0.192 ;
     RECT  36.552 0.144 36.72 0.192 ;
     RECT  36.744 0.144 36.864 0.192 ;
     RECT  36.888 0.144 37.056 0.192 ;
     RECT  37.08 0.144 37.2 0.192 ;
     RECT  37.224 0.144 37.392 0.192 ;
     RECT  37.416 0.144 37.536 0.192 ;
     RECT  37.56 0.144 37.68 0.192 ;
     RECT  37.704 0.144 37.872 0.192 ;
     RECT  37.896 0.144 38.016 0.192 ;
     RECT  38.04 0.144 38.208 0.192 ;
     RECT  38.232 0.144 38.352 0.192 ;
     RECT  38.376 0.144 38.544 0.192 ;
     RECT  38.568 0.144 38.688 0.192 ;
     RECT  38.712 0.144 38.88 0.192 ;
     RECT  38.904 0.144 39.024 0.192 ;
     RECT  39.048 0.144 39.216 0.192 ;
     RECT  39.24 0.144 39.36 0.192 ;
     RECT  39.384 0.144 39.552 0.192 ;
     RECT  39.576 0.144 39.696 0.192 ;
     RECT  39.72 0.144 39.888 0.192 ;
     RECT  39.912 0.144 40.032 0.192 ;
     RECT  40.056 0.144 40.176 0.192 ;
     RECT  40.2 0.144 40.368 0.192 ;
     RECT  40.392 0.144 40.512 0.192 ;
     RECT  40.536 0.144 40.704 0.192 ;
     RECT  40.728 0.144 40.848 0.192 ;
     RECT  40.872 0.144 41.04 0.192 ;
     RECT  41.064 0.144 41.184 0.192 ;
     RECT  41.208 0.144 41.376 0.192 ;
     RECT  41.4 0.144 41.52 0.192 ;
     RECT  41.544 0.144 41.712 0.192 ;
     RECT  41.736 0.144 41.856 0.192 ;
     RECT  41.88 0.144 42.048 0.192 ;
     RECT  42.072 0.144 42.192 0.192 ;
     RECT  42.216 0.144 42.384 0.192 ;
     RECT  42.408 0.144 42.528 0.192 ;
     RECT  42.552 0.144 42.72 0.192 ;
     RECT  42.744 0.144 42.864 0.192 ;
     RECT  42.888 0.144 43.008 0.192 ;
     RECT  43.032 0.144 43.2 0.192 ;
     RECT  43.224 0.144 43.344 0.192 ;
     RECT  43.368 0.144 43.536 0.192 ;
     RECT  43.56 0.144 43.68 0.192 ;
     RECT  43.704 0.144 43.872 0.192 ;
     RECT  43.896 0.144 44.016 0.192 ;
     RECT  44.04 0.144 44.208 0.192 ;
     RECT  44.232 0.144 44.352 0.192 ;
     RECT  44.376 0.144 44.544 0.192 ;
     RECT  44.568 0.144 44.688 0.192 ;
     RECT  44.712 0.144 44.88 0.192 ;
     RECT  44.904 0.144 45.024 0.192 ;
     RECT  45.048 0.144 45.216 0.192 ;
     RECT  45.24 0.144 45.36 0.192 ;
     RECT  45.384 0.144 45.504 0.192 ;
     RECT  45.528 0.144 45.696 0.192 ;
     RECT  45.72 0.144 45.84 0.192 ;
     RECT  45.864 0.144 46.032 0.192 ;
     RECT  46.056 0.144 46.176 0.192 ;
     RECT  46.2 0.144 46.368 0.192 ;
     RECT  46.392 0.144 46.512 0.192 ;
     RECT  46.536 0.144 46.704 0.192 ;
     RECT  46.728 0.144 46.848 0.192 ;
     RECT  46.872 0.144 47.04 0.192 ;
     RECT  47.064 0.144 47.184 0.192 ;
     RECT  47.208 0.144 47.376 0.192 ;
     RECT  47.4 0.144 47.52 0.192 ;
     RECT  47.544 0.144 47.712 0.192 ;
     RECT  47.736 0.144 47.856 0.192 ;
     RECT  47.88 0.144 48 0.192 ;
     RECT  48.024 0.144 48.192 0.192 ;
     RECT  48.216 0.144 48.336 0.192 ;
     RECT  48.36 0.144 48.528 0.192 ;
     RECT  48.552 0.144 48.672 0.192 ;
     RECT  48.696 0.144 48.864 0.192 ;
     RECT  48.888 0.144 49.008 0.192 ;
     RECT  49.032 0.144 49.2 0.192 ;
     RECT  49.224 0.144 49.344 0.192 ;
     RECT  49.368 0.144 49.536 0.192 ;
     RECT  49.56 0.144 49.68 0.192 ;
     RECT  49.704 0.144 49.872 0.192 ;
     RECT  49.896 0.144 50.016 0.192 ;
     RECT  50.04 0.144 50.208 0.192 ;
     RECT  50.232 0.144 50.592 0.192 ;
     RECT  50.616 0.144 50.736 0.192 ;
     RECT  50.76 0.144 50.928 0.192 ;
     RECT  50.952 0.144 51.072 0.192 ;
     RECT  51.096 0.144 51.264 0.192 ;
     RECT  51.288 0.144 51.408 0.192 ;
     RECT  51.432 0.144 51.6 0.192 ;
     RECT  51.624 0.144 51.744 0.192 ;
     RECT  51.768 0.144 51.936 0.192 ;
     RECT  51.96 0.144 52.08 0.192 ;
     RECT  52.104 0.144 52.272 0.192 ;
     RECT  52.296 0.144 52.416 0.192 ;
     RECT  52.44 0.144 52.608 0.192 ;
     RECT  52.632 0.144 52.752 0.192 ;
     RECT  52.776 0.144 52.896 0.192 ;
     RECT  52.92 0.144 53.088 0.192 ;
     RECT  53.112 0.144 53.232 0.192 ;
     RECT  53.256 0.144 53.424 0.192 ;
     RECT  53.448 0.144 53.568 0.192 ;
     RECT  53.592 0.144 53.76 0.192 ;
     RECT  53.784 0.144 53.904 0.192 ;
     RECT  53.928 0.144 54.096 0.192 ;
     RECT  54.12 0.144 54.24 0.192 ;
     RECT  54.264 0.144 54.432 0.192 ;
     RECT  54.456 0.144 54.576 0.192 ;
     RECT  54.6 0.144 54.768 0.192 ;
     RECT  54.792 0.144 54.912 0.192 ;
     RECT  54.936 0.144 55.104 0.192 ;
     RECT  55.128 0.144 55.248 0.192 ;
     RECT  55.272 0.144 55.392 0.192 ;
     RECT  55.416 0.144 55.584 0.192 ;
     RECT  55.608 0.144 55.728 0.192 ;
     RECT  55.752 0.144 55.92 0.192 ;
     RECT  55.944 0.144 56.064 0.192 ;
     RECT  56.088 0.144 56.256 0.192 ;
     RECT  56.28 0.144 56.4 0.192 ;
     RECT  56.424 0.144 56.592 0.192 ;
     RECT  56.616 0.144 56.736 0.192 ;
     RECT  56.76 0.144 56.928 0.192 ;
     RECT  56.952 0.144 57.072 0.192 ;
     RECT  57.096 0.144 57.264 0.192 ;
     RECT  57.288 0.144 57.408 0.192 ;
     RECT  57.432 0.144 57.6 0.192 ;
     RECT  57.624 0.144 57.744 0.192 ;
     RECT  57.768 0.144 57.936 0.192 ;
     RECT  57.96 0.144 58.08 0.192 ;
     RECT  58.104 0.144 58.224 0.192 ;
     RECT  58.248 0.144 58.416 0.192 ;
     RECT  58.44 0.144 58.56 0.192 ;
     RECT  58.584 0.144 58.752 0.192 ;
     RECT  58.776 0.144 58.896 0.192 ;
     RECT  58.92 0.144 59.088 0.192 ;
     RECT  59.112 0.144 59.232 0.192 ;
     RECT  59.256 0.144 59.424 0.192 ;
     RECT  59.448 0.144 59.568 0.192 ;
     RECT  59.592 0.144 59.76 0.192 ;
     RECT  59.784 0.144 59.904 0.192 ;
     RECT  59.928 0.144 60.096 0.192 ;
     RECT  60.12 0.144 60.24 0.192 ;
     RECT  60.264 0.144 60.432 0.192 ;
     RECT  60.456 0.144 60.576 0.192 ;
     RECT  60.6 0.144 60.72 0.192 ;
     RECT  60.744 0.144 60.912 0.192 ;
     RECT  60.936 0.144 61.056 0.192 ;
     RECT  61.08 0.144 61.248 0.192 ;
     RECT  61.272 0.144 61.392 0.192 ;
     RECT  61.416 0.144 61.584 0.192 ;
     RECT  61.608 0.144 61.728 0.192 ;
     RECT  61.752 0.144 61.92 0.192 ;
     RECT  61.944 0.144 62.064 0.192 ;
     RECT  62.088 0.144 62.256 0.192 ;
     RECT  62.28 0.144 62.4 0.192 ;
     RECT  62.424 0.144 62.592 0.192 ;
     RECT  62.616 0.144 62.736 0.192 ;
     RECT  62.76 0.144 62.928 0.192 ;
     RECT  62.952 0.144 63.072 0.192 ;
     RECT  63.096 0.144 63.216 0.192 ;
     RECT  63.24 0.144 63.408 0.192 ;
     RECT  63.432 0.144 63.552 0.192 ;
     RECT  63.576 0.144 63.744 0.192 ;
     RECT  63.768 0.144 63.888 0.192 ;
     RECT  63.912 0.144 64.08 0.192 ;
     RECT  64.104 0.144 64.224 0.192 ;
     RECT  64.248 0.144 64.416 0.192 ;
     RECT  64.44 0.144 64.56 0.192 ;
     RECT  64.584 0.144 64.752 0.192 ;
     RECT  64.776 0.144 64.896 0.192 ;
     RECT  64.92 0.144 65.088 0.192 ;
     RECT  65.112 0.144 65.232 0.192 ;
     RECT  65.256 0.144 65.424 0.192 ;
     RECT  65.448 0.144 65.568 0.192 ;
     RECT  65.592 0.144 65.76 0.192 ;
     RECT  65.784 0.144 65.904 0.192 ;
     RECT  65.928 0.144 66.048 0.192 ;
     RECT  66.072 0.144 66.24 0.192 ;
     RECT  66.264 0.144 66.384 0.192 ;
     RECT  66.408 0.144 66.576 0.192 ;
     RECT  66.6 0.144 66.72 0.192 ;
     RECT  66.744 0.144 66.912 0.192 ;
     RECT  66.936 0.144 67.056 0.192 ;
     RECT  67.08 0.144 67.248 0.192 ;
     RECT  67.272 0.144 67.392 0.192 ;
     RECT  67.416 0.144 67.584 0.192 ;
     RECT  67.608 0.144 67.728 0.192 ;
     RECT  67.752 0.144 67.92 0.192 ;
     RECT  67.944 0.144 68.064 0.192 ;
     RECT  68.088 0.144 68.256 0.192 ;
     RECT  68.28 0.144 68.4 0.192 ;
     RECT  68.424 0.144 68.544 0.192 ;
     RECT  68.568 0.144 68.736 0.192 ;
     RECT  68.76 0.144 68.88 0.192 ;
     RECT  68.904 0.144 69.072 0.192 ;
     RECT  69.096 0.144 69.216 0.192 ;
     RECT  69.24 0.144 69.408 0.192 ;
     RECT  69.432 0.144 69.552 0.192 ;
     RECT  69.576 0.144 69.744 0.192 ;
     RECT  69.768 0.144 69.888 0.192 ;
     RECT  69.912 0.144 70.08 0.192 ;
     RECT  70.104 0.144 70.224 0.192 ;
     RECT  70.248 0.144 70.416 0.192 ;
     RECT  70.44 0.144 70.56 0.192 ;
     RECT  70.584 0.144 70.752 0.192 ;
     RECT  70.776 0.144 70.896 0.192 ;
     RECT  70.92 0.144 71.04 0.192 ;
     RECT  71.064 0.144 71.232 0.192 ;
     RECT  71.256 0.144 71.376 0.192 ;
     RECT  71.4 0.144 71.568 0.192 ;
     RECT  71.592 0.144 71.712 0.192 ;
     RECT  71.736 0.144 71.904 0.192 ;
     RECT  71.928 0.144 72.048 0.192 ;
     RECT  72.072 0.144 72.24 0.192 ;
     RECT  72.264 0.144 72.384 0.192 ;
     RECT  72.408 0.144 72.576 0.192 ;
     RECT  72.6 0.144 72.72 0.192 ;
     RECT  72.744 0.144 72.912 0.192 ;
     RECT  72.936 0.144 73.056 0.192 ;
     RECT  73.08 0.144 73.248 0.192 ;
     RECT  4.512 0.192 73.272 0.227 ;
     RECT  4.512 0.227 54.936 0.323 ;
     RECT  21.504 0.323 54.936 0.563 ;
     RECT  55.92 0.227 73.272 0.563 ;
     RECT  50.016 0.563 54.936 0.611 ;
     RECT  56.064 0.563 69.096 0.611 ;
     RECT  21.504 0.563 49.032 1.139 ;
     RECT  51.072 0.611 52.296 1.139 ;
     RECT  53.904 0.611 54.936 1.139 ;
     RECT  56.064 0.611 63.096 1.139 ;
     RECT  59.424 1.139 63.096 1.283 ;
     RECT  59.424 1.283 62.616 1.715 ;
     RECT  64.224 0.611 69.096 1.715 ;
     RECT  70.08 0.563 73.272 1.715 ;
     RECT  4.512 0.323 20.328 1.763 ;
     RECT  21.504 1.139 41.4 1.763 ;
     RECT  42.384 1.139 45.864 1.763 ;
     RECT  47.04 1.139 49.032 1.763 ;
     RECT  50.016 0.611 50.04 1.763 ;
     RECT  53.904 1.139 54.456 1.763 ;
     RECT  57.264 1.139 58.44 1.763 ;
     RECT  61.248 1.715 62.616 1.763 ;
     RECT  66.912 1.715 68.904 1.763 ;
     RECT  72.048 1.715 73.272 1.763 ;
     RECT  5.1 1.763 8.376 1.811 ;
     RECT  18.144 1.763 20.328 1.811 ;
     RECT  47.712 1.763 48.612 1.811 ;
     RECT  11.856 1.763 16.536 1.859 ;
     RECT  22.656 1.763 29.712 1.859 ;
     RECT  5.1 1.811 5.688 1.907 ;
     RECT  21.504 1.763 21.612 2.137 ;
     RECT  51.6 1.139 51.96 2.137 ;
     RECT  53.904 1.763 54.264 2.137 ;
     RECT  56.064 1.139 56.28 2.137 ;
     RECT  57.264 1.763 57.432 2.137 ;
     RECT  58.416 1.763 58.44 2.137 ;
     RECT  59.424 1.715 60.264 2.137 ;
     RECT  70.08 1.715 70.584 2.137 ;
     RECT  2.4 2.137 2.52 2.151 ;
     RECT  42.9 1.763 45.864 2.151 ;
     RECT  75.3 2.137 75.42 2.151 ;
     RECT  13.008 1.859 16.536 2.195 ;
     RECT  18.144 1.811 19.704 2.195 ;
     RECT  22.992 1.859 29.712 2.195 ;
     RECT  30.72 1.763 38.712 2.195 ;
     RECT  58.416 2.137 60.264 2.195 ;
     RECT  61.392 1.763 62.616 2.195 ;
     RECT  21.3 2.137 21.612 2.245 ;
     RECT  56.064 2.137 57.432 2.245 ;
     RECT  6.816 1.811 8.112 2.291 ;
     RECT  11.856 1.859 11.88 2.291 ;
     RECT  13.008 2.195 16.212 2.291 ;
     RECT  40.2 1.763 40.728 2.291 ;
     RECT  47.856 1.811 48.612 2.291 ;
     RECT  53.7 2.137 54.264 2.291 ;
     RECT  61.8 2.195 62.616 2.291 ;
     RECT  64.224 1.715 65.592 2.291 ;
     RECT  66.912 1.763 68.424 2.291 ;
     RECT  69.9 2.137 70.584 2.291 ;
     RECT  42.9 2.151 45.912 2.339 ;
     RECT  28.032 2.195 29.712 2.387 ;
     RECT  30.72 2.195 36.408 2.387 ;
     RECT  37.392 2.195 38.712 2.387 ;
     RECT  55.584 2.245 57.432 2.387 ;
     RECT  30.864 2.387 33.72 2.819 ;
     RECT  51 2.137 51.96 2.867 ;
     RECT  58.416 2.195 60.12 2.867 ;
     RECT  64.5 2.291 65.592 2.867 ;
     RECT  66.912 2.291 67.512 2.867 ;
     RECT  28.704 2.387 29.712 2.915 ;
     RECT  30.864 2.819 31.08 2.915 ;
     RECT  34.8 2.387 35.256 2.915 ;
     RECT  18.6 2.195 19.704 2.963 ;
     RECT  22.992 2.195 27.012 3.107 ;
     RECT  25.632 3.107 27.012 3.443 ;
     RECT  31.056 2.915 31.08 3.443 ;
     RECT  34.8 2.915 35.208 3.443 ;
     RECT  37.5 2.387 38.712 3.443 ;
     RECT  37.5 3.443 37.944 3.635 ;
     RECT  32.1 2.819 33.72 4.019 ;
     RECT  44.688 2.339 45.912 4.019 ;
     RECT  48.192 2.291 48.612 4.019 ;
     RECT  22.992 3.107 24.408 4.309 ;
     RECT  22.8 4.309 24.408 4.499 ;
     RECT  23.328 4.499 24.408 4.595 ;
     RECT  28.896 2.915 29.712 4.595 ;
     RECT  32.1 4.019 33.048 4.595 ;
     RECT  26.7 3.443 27.012 4.741 ;
     RECT  26.7 4.741 27.24 4.883 ;
     RECT  25.632 3.443 25.656 5.123 ;
     RECT  7.344 2.291 8.112 5.219 ;
     RECT  32.1 4.595 32.412 5.317 ;
     RECT  34.8 3.443 35.112 5.365 ;
     RECT  31.968 5.317 32.412 5.507 ;
     RECT  34.368 5.365 35.112 5.507 ;
     RECT  13.008 2.291 13.512 5.747 ;
     RECT  14.976 2.291 16.212 5.797 ;
     RECT  22.8 5.701 22.824 5.843 ;
     RECT  14.832 5.797 16.212 6.035 ;
     RECT  29.232 4.595 29.712 6.179 ;
     RECT  14.976 6.035 16.212 6.323 ;
     RECT  24 4.595 24.408 6.373 ;
     RECT  7.536 5.219 8.112 6.851 ;
     RECT  55.584 2.387 57.288 6.851 ;
     RECT  9.84 1.763 10.812 6.899 ;
     RECT  23.904 6.373 24.408 7.141 ;
     RECT  13.2 5.747 13.512 7.381 ;
     RECT  23.808 7.141 24.408 7.427 ;
     RECT  24 7.427 24.408 13.093 ;
     RECT  34.8 5.507 35.112 14.725 ;
     RECT  34.8 14.725 35.304 15.349 ;
     RECT  18.6 2.963 18.912 15.445 ;
     RECT  13.2 7.381 13.608 15.493 ;
     RECT  36.48 15.349 36.504 15.637 ;
     RECT  37.5 3.635 37.812 15.637 ;
     RECT  29.4 6.179 29.712 15.829 ;
     RECT  32.1 5.507 32.412 15.829 ;
     RECT  12.48 15.493 13.608 15.875 ;
     RECT  33.504 15.349 33.528 15.875 ;
     RECT  24 13.093 24.504 15.877 ;
     RECT  26.7 4.883 27.012 15.877 ;
     RECT  34.8 15.349 35.352 15.877 ;
     RECT  36.48 15.637 37.812 15.877 ;
     RECT  21.12 2.245 21.612 15.925 ;
     RECT  26.7 15.877 27.336 15.973 ;
     RECT  23.904 15.877 24.504 16.021 ;
     RECT  25.968 15.973 27.336 16.021 ;
     RECT  34.8 15.877 37.812 16.021 ;
     RECT  32.1 15.829 32.52 16.261 ;
     RECT  10.5 6.899 10.812 16.405 ;
     RECT  21.024 15.925 21.612 16.405 ;
     RECT  5.1 1.907 5.412 16.501 ;
     RECT  13.104 15.875 13.608 16.501 ;
     RECT  23.904 16.021 27.336 16.501 ;
     RECT  23.904 16.501 27.672 16.549 ;
     RECT  28.704 15.829 29.712 16.549 ;
     RECT  18.384 15.445 18.912 16.595 ;
     RECT  31.584 16.261 32.52 16.595 ;
     RECT  31.968 16.595 32.52 16.979 ;
     RECT  34.704 16.021 37.812 16.979 ;
     RECT  15.9 6.323 16.212 17.029 ;
     RECT  15.408 17.029 16.212 17.077 ;
     RECT  20.928 16.405 21.612 17.077 ;
     RECT  13.104 16.501 14.376 17.171 ;
     RECT  37.008 16.979 37.812 17.315 ;
     RECT  37.5 17.315 37.812 17.317 ;
     RECT  10.272 16.405 10.812 17.411 ;
     RECT  18.48 16.595 18.912 17.411 ;
     RECT  5.1 16.501 5.544 17.459 ;
     RECT  13.104 17.171 13.656 17.507 ;
     RECT  15.408 17.077 17.064 17.507 ;
     RECT  37.5 17.317 38.568 17.507 ;
     RECT  23.904 16.549 29.712 17.651 ;
     RECT  31.968 16.979 32.412 17.653 ;
     RECT  40.2 2.291 40.512 17.653 ;
     RECT  23.904 17.651 27.768 17.797 ;
     RECT  20.928 17.077 21.72 17.843 ;
     RECT  19.92 15.925 19.944 17.941 ;
     RECT  31.776 17.653 32.412 17.987 ;
     RECT  5.1 17.459 5.412 18.037 ;
     RECT  7.488 6.851 8.112 18.131 ;
     RECT  23.856 17.797 27.768 18.227 ;
     RECT  64.5 2.867 64.812 18.229 ;
     RECT  69.9 2.291 70.212 18.229 ;
     RECT  72.6 1.763 72.912 18.229 ;
     RECT  21.024 17.843 21.72 18.275 ;
     RECT  25.968 18.227 27.768 18.275 ;
     RECT  37.5 17.507 37.812 18.277 ;
     RECT  48.3 4.019 48.612 18.325 ;
     RECT  61.8 2.291 62.112 18.709 ;
     RECT  42.9 2.339 43.212 18.757 ;
     RECT  53.7 2.291 54.012 18.757 ;
     RECT  55.584 6.851 56.712 18.757 ;
     RECT  59.1 2.867 59.412 18.757 ;
     RECT  67.2 2.867 67.512 18.757 ;
     RECT  69.792 18.229 70.212 18.757 ;
     RECT  71.952 18.229 72.912 18.757 ;
     RECT  4.56 18.037 5.412 18.805 ;
     RECT  7.536 18.131 8.112 18.805 ;
     RECT  13.104 17.507 13.512 18.805 ;
     RECT  15.408 17.507 16.212 18.805 ;
     RECT  18.6 17.411 18.912 18.805 ;
     RECT  19.92 17.941 20.04 18.805 ;
     RECT  21.024 18.275 21.612 18.805 ;
     RECT  23.856 18.227 24.888 18.805 ;
     RECT  26.112 18.275 27.768 18.805 ;
     RECT  29.088 17.651 29.712 18.805 ;
     RECT  34.704 16.979 35.688 18.805 ;
     RECT  37.248 18.277 37.812 18.805 ;
     RECT  52.608 18.757 54.012 18.805 ;
     RECT  55.584 18.757 56.808 18.805 ;
     RECT  59.1 18.757 59.688 18.805 ;
     RECT  61.632 18.709 62.112 18.805 ;
     RECT  52.608 18.805 56.808 18.851 ;
     RECT  34.704 18.805 36.168 18.853 ;
     RECT  4.56 18.805 6.024 19.093 ;
     RECT  7.536 18.805 9.048 19.093 ;
     RECT  10.5 17.411 10.812 19.093 ;
     RECT  11.808 18.805 11.832 19.093 ;
     RECT  13.104 18.805 14.088 19.093 ;
     RECT  31.968 17.987 32.412 19.093 ;
     RECT  34.128 18.853 36.168 19.093 ;
     RECT  52.608 18.851 54.648 19.141 ;
     RECT  4.56 19.093 9.048 19.333 ;
     RECT  10.272 19.093 14.088 19.333 ;
     RECT  15.072 18.805 16.584 19.333 ;
     RECT  17.568 18.805 17.592 19.333 ;
     RECT  18.6 18.805 21.612 19.333 ;
     RECT  22.608 18.805 24.888 19.333 ;
     RECT  26.112 18.805 29.88 19.333 ;
     RECT  31.872 19.093 36.168 19.333 ;
     RECT  37.152 18.805 37.944 19.333 ;
     RECT  39.312 17.653 40.512 19.333 ;
     RECT  60.912 18.805 62.112 19.381 ;
     RECT  63.936 18.229 64.812 19.381 ;
     RECT  66.96 18.757 67.992 19.381 ;
     RECT  2.4 2.151 2.712 19.449 ;
     RECT  51 2.867 51.312 19.449 ;
     RECT  75.3 2.151 75.612 19.449 ;
     RECT  2.4 19.449 2.52 19.463 ;
     RECT  75.3 19.449 75.42 19.463 ;
     RECT  4.512 19.333 40.512 19.957 ;
     RECT  41.568 18.757 43.212 19.957 ;
     RECT  45.6 4.019 45.912 19.957 ;
     RECT  47.616 18.325 48.612 19.957 ;
     RECT  51 19.449 51.144 19.957 ;
     RECT  52.368 19.141 54.648 19.957 ;
     RECT  55.872 18.851 56.808 19.957 ;
     RECT  58.656 18.805 59.688 19.957 ;
     RECT  60.672 19.381 62.112 19.957 ;
     RECT  63.696 19.381 64.812 19.957 ;
     RECT  65.952 18.229 65.976 19.957 ;
     RECT  66.96 19.381 68.712 19.957 ;
     RECT  69.792 18.757 70.968 19.957 ;
     RECT  71.952 18.757 73.272 19.957 ;
     RECT  4.512 19.957 51.144 20.533 ;
     RECT  52.128 19.957 57.432 20.533 ;
     RECT  58.416 19.957 73.272 20.533 ;
     RECT  4.512 20.533 73.272 21.408 ;
     RECT  4.536 21.408 4.752 21.456 ;
     RECT  4.776 21.408 4.992 21.456 ;
     RECT  5.016 21.408 5.28 21.456 ;
     RECT  5.304 21.408 5.52 21.456 ;
     RECT  5.544 21.408 5.76 21.456 ;
     RECT  5.784 21.408 6 21.456 ;
     RECT  6.024 21.408 6.288 21.456 ;
     RECT  6.312 21.408 6.528 21.456 ;
     RECT  6.552 21.408 6.768 21.456 ;
     RECT  6.792 21.408 7.008 21.456 ;
     RECT  7.032 21.408 7.248 21.456 ;
     RECT  7.272 21.408 7.536 21.456 ;
     RECT  7.56 21.408 7.776 21.456 ;
     RECT  7.8 21.408 8.016 21.456 ;
     RECT  8.04 21.408 8.256 21.456 ;
     RECT  8.28 21.408 8.544 21.456 ;
     RECT  8.568 21.408 8.784 21.456 ;
     RECT  8.808 21.408 9.024 21.456 ;
     RECT  9.048 21.408 9.264 21.456 ;
     RECT  9.288 21.408 9.552 21.456 ;
     RECT  9.576 21.408 9.792 21.456 ;
     RECT  9.816 21.408 10.032 21.456 ;
     RECT  10.056 21.408 10.272 21.456 ;
     RECT  10.296 21.408 10.56 21.456 ;
     RECT  10.584 21.408 10.8 21.456 ;
     RECT  10.824 21.408 11.04 21.456 ;
     RECT  11.064 21.408 11.28 21.456 ;
     RECT  11.304 21.408 11.52 21.456 ;
     RECT  11.544 21.408 11.808 21.456 ;
     RECT  11.832 21.408 12.048 21.456 ;
     RECT  12.072 21.408 12.288 21.456 ;
     RECT  12.312 21.408 12.528 21.456 ;
     RECT  12.552 21.408 12.816 21.456 ;
     RECT  12.84 21.408 13.056 21.456 ;
     RECT  13.08 21.408 13.296 21.456 ;
     RECT  13.32 21.408 13.536 21.456 ;
     RECT  13.56 21.408 13.824 21.456 ;
     RECT  13.848 21.408 14.064 21.456 ;
     RECT  14.088 21.408 14.304 21.456 ;
     RECT  14.328 21.408 14.544 21.456 ;
     RECT  14.568 21.408 14.784 21.456 ;
     RECT  14.808 21.408 15.072 21.456 ;
     RECT  15.096 21.408 15.312 21.456 ;
     RECT  15.336 21.408 15.552 21.456 ;
     RECT  15.576 21.408 15.792 21.456 ;
     RECT  15.816 21.408 16.08 21.456 ;
     RECT  16.104 21.408 16.32 21.456 ;
     RECT  16.344 21.408 16.56 21.456 ;
     RECT  16.584 21.408 16.8 21.456 ;
     RECT  16.824 21.408 17.088 21.456 ;
     RECT  17.112 21.408 17.328 21.456 ;
     RECT  17.352 21.408 17.568 21.456 ;
     RECT  17.592 21.408 17.808 21.456 ;
     RECT  17.832 21.408 18.048 21.456 ;
     RECT  18.072 21.408 18.336 21.456 ;
     RECT  18.36 21.408 18.576 21.456 ;
     RECT  18.6 21.408 18.816 21.456 ;
     RECT  18.84 21.408 19.056 21.456 ;
     RECT  19.08 21.408 19.344 21.456 ;
     RECT  19.368 21.408 19.584 21.456 ;
     RECT  19.608 21.408 19.824 21.456 ;
     RECT  19.848 21.408 20.064 21.456 ;
     RECT  20.088 21.408 20.352 21.456 ;
     RECT  20.376 21.408 20.592 21.456 ;
     RECT  20.616 21.408 20.832 21.456 ;
     RECT  20.856 21.408 21.072 21.456 ;
     RECT  21.096 21.408 21.36 21.456 ;
     RECT  21.384 21.408 21.6 21.456 ;
     RECT  21.624 21.408 21.84 21.456 ;
     RECT  21.864 21.408 22.08 21.456 ;
     RECT  22.104 21.408 22.32 21.456 ;
     RECT  22.344 21.408 22.608 21.456 ;
     RECT  22.632 21.408 22.848 21.456 ;
     RECT  22.872 21.408 23.088 21.456 ;
     RECT  23.112 21.408 23.328 21.456 ;
     RECT  23.352 21.408 23.616 21.456 ;
     RECT  23.64 21.408 23.856 21.456 ;
     RECT  23.88 21.408 24.096 21.456 ;
     RECT  24.12 21.408 24.336 21.456 ;
     RECT  24.36 21.408 24.624 21.456 ;
     RECT  24.648 21.408 24.864 21.456 ;
     RECT  24.888 21.408 25.104 21.456 ;
     RECT  25.128 21.408 25.344 21.456 ;
     RECT  25.368 21.408 25.584 21.456 ;
     RECT  25.608 21.408 25.872 21.456 ;
     RECT  25.896 21.408 26.112 21.456 ;
     RECT  26.136 21.408 26.352 21.456 ;
     RECT  26.376 21.408 26.592 21.456 ;
     RECT  26.616 21.408 26.88 21.456 ;
     RECT  26.904 21.408 27.12 21.456 ;
     RECT  27.144 21.408 27.36 21.456 ;
     RECT  27.384 21.408 27.6 21.456 ;
     RECT  27.624 21.408 27.888 21.456 ;
     RECT  27.912 21.408 28.128 21.456 ;
     RECT  28.152 21.408 28.368 21.456 ;
     RECT  28.392 21.408 28.608 21.456 ;
     RECT  28.632 21.408 28.896 21.456 ;
     RECT  28.92 21.408 29.136 21.456 ;
     RECT  29.16 21.408 29.376 21.456 ;
     RECT  29.4 21.408 29.616 21.456 ;
     RECT  29.64 21.408 29.856 21.456 ;
     RECT  29.88 21.408 30.144 21.456 ;
     RECT  30.168 21.408 30.384 21.456 ;
     RECT  30.408 21.408 30.624 21.456 ;
     RECT  30.648 21.408 30.864 21.456 ;
     RECT  30.888 21.408 31.152 21.456 ;
     RECT  31.176 21.408 31.392 21.456 ;
     RECT  31.416 21.408 31.632 21.456 ;
     RECT  31.656 21.408 31.872 21.456 ;
     RECT  31.896 21.408 32.16 21.456 ;
     RECT  32.184 21.408 32.4 21.456 ;
     RECT  32.424 21.408 32.64 21.456 ;
     RECT  32.664 21.408 32.88 21.456 ;
     RECT  32.904 21.408 33.12 21.456 ;
     RECT  33.144 21.408 33.408 21.456 ;
     RECT  33.432 21.408 33.648 21.456 ;
     RECT  33.672 21.408 33.888 21.456 ;
     RECT  33.912 21.408 34.128 21.456 ;
     RECT  34.152 21.408 34.416 21.456 ;
     RECT  34.44 21.408 34.656 21.456 ;
     RECT  34.68 21.408 34.896 21.456 ;
     RECT  34.92 21.408 35.136 21.456 ;
     RECT  35.16 21.408 35.424 21.456 ;
     RECT  35.448 21.408 35.664 21.456 ;
     RECT  35.688 21.408 35.904 21.456 ;
     RECT  35.928 21.408 36.144 21.456 ;
     RECT  36.168 21.408 36.384 21.456 ;
     RECT  36.408 21.408 36.672 21.456 ;
     RECT  36.696 21.408 36.912 21.456 ;
     RECT  36.936 21.408 37.152 21.456 ;
     RECT  37.176 21.408 37.392 21.456 ;
     RECT  37.416 21.408 37.68 21.456 ;
     RECT  37.704 21.408 37.92 21.456 ;
     RECT  37.944 21.408 38.16 21.456 ;
     RECT  38.184 21.408 38.4 21.456 ;
     RECT  38.424 21.408 38.688 21.456 ;
     RECT  38.712 21.408 39.072 21.456 ;
     RECT  39.096 21.408 39.312 21.456 ;
     RECT  39.336 21.408 39.552 21.456 ;
     RECT  39.576 21.408 39.84 21.456 ;
     RECT  39.864 21.408 40.08 21.456 ;
     RECT  40.104 21.408 40.32 21.456 ;
     RECT  40.344 21.408 40.56 21.456 ;
     RECT  40.584 21.408 40.848 21.456 ;
     RECT  40.872 21.408 41.088 21.456 ;
     RECT  41.112 21.408 41.328 21.456 ;
     RECT  41.352 21.408 41.568 21.456 ;
     RECT  41.592 21.408 41.808 21.456 ;
     RECT  41.832 21.408 42.096 21.456 ;
     RECT  42.12 21.408 42.336 21.456 ;
     RECT  42.36 21.408 42.576 21.456 ;
     RECT  42.6 21.408 42.816 21.456 ;
     RECT  42.84 21.408 43.104 21.456 ;
     RECT  43.128 21.408 43.344 21.456 ;
     RECT  43.368 21.408 43.584 21.456 ;
     RECT  43.608 21.408 43.824 21.456 ;
     RECT  43.848 21.408 44.112 21.456 ;
     RECT  44.136 21.408 44.352 21.456 ;
     RECT  44.376 21.408 44.592 21.456 ;
     RECT  44.616 21.408 44.832 21.456 ;
     RECT  44.856 21.408 45.12 21.456 ;
     RECT  45.144 21.408 45.36 21.456 ;
     RECT  45.384 21.408 45.6 21.456 ;
     RECT  45.624 21.408 45.84 21.456 ;
     RECT  45.864 21.408 46.08 21.456 ;
     RECT  46.104 21.408 46.368 21.456 ;
     RECT  46.392 21.408 46.608 21.456 ;
     RECT  46.632 21.408 46.848 21.456 ;
     RECT  46.872 21.408 47.088 21.456 ;
     RECT  47.112 21.408 47.376 21.456 ;
     RECT  47.4 21.408 47.616 21.456 ;
     RECT  47.64 21.408 47.856 21.456 ;
     RECT  47.88 21.408 48.096 21.456 ;
     RECT  48.12 21.408 48.384 21.456 ;
     RECT  48.408 21.408 48.624 21.456 ;
     RECT  48.648 21.408 48.864 21.456 ;
     RECT  48.888 21.408 49.104 21.456 ;
     RECT  49.128 21.408 49.344 21.456 ;
     RECT  49.368 21.408 49.632 21.456 ;
     RECT  49.656 21.408 49.872 21.456 ;
     RECT  49.896 21.408 50.112 21.456 ;
     RECT  50.136 21.408 50.352 21.456 ;
     RECT  50.376 21.408 50.64 21.456 ;
     RECT  50.664 21.408 50.88 21.456 ;
     RECT  50.904 21.408 51.12 21.456 ;
     RECT  51.144 21.408 51.36 21.456 ;
     RECT  51.384 21.408 51.648 21.456 ;
     RECT  51.672 21.408 51.888 21.456 ;
     RECT  51.912 21.408 52.128 21.456 ;
     RECT  52.152 21.408 52.368 21.456 ;
     RECT  52.392 21.408 52.608 21.456 ;
     RECT  52.632 21.408 52.896 21.456 ;
     RECT  52.92 21.408 53.136 21.456 ;
     RECT  53.16 21.408 53.376 21.456 ;
     RECT  53.4 21.408 53.616 21.456 ;
     RECT  53.64 21.408 53.904 21.456 ;
     RECT  53.928 21.408 54.144 21.456 ;
     RECT  54.168 21.408 54.384 21.456 ;
     RECT  54.408 21.408 54.624 21.456 ;
     RECT  54.648 21.408 54.912 21.456 ;
     RECT  54.936 21.408 55.152 21.456 ;
     RECT  55.176 21.408 55.392 21.456 ;
     RECT  55.416 21.408 55.632 21.456 ;
     RECT  55.656 21.408 55.92 21.456 ;
     RECT  55.944 21.408 56.16 21.456 ;
     RECT  56.184 21.408 56.4 21.456 ;
     RECT  56.424 21.408 56.64 21.456 ;
     RECT  56.664 21.408 56.88 21.456 ;
     RECT  56.904 21.408 57.168 21.456 ;
     RECT  57.192 21.408 57.408 21.456 ;
     RECT  57.432 21.408 57.648 21.456 ;
     RECT  57.672 21.408 57.888 21.456 ;
     RECT  57.912 21.408 58.176 21.456 ;
     RECT  58.2 21.408 58.416 21.456 ;
     RECT  58.44 21.408 58.656 21.456 ;
     RECT  58.68 21.408 58.896 21.456 ;
     RECT  58.92 21.408 59.184 21.456 ;
     RECT  59.208 21.408 59.424 21.456 ;
     RECT  59.448 21.408 59.664 21.456 ;
     RECT  59.688 21.408 59.904 21.456 ;
     RECT  59.928 21.408 60.144 21.456 ;
     RECT  60.168 21.408 60.432 21.456 ;
     RECT  60.456 21.408 60.672 21.456 ;
     RECT  60.696 21.408 60.912 21.456 ;
     RECT  60.936 21.408 61.152 21.456 ;
     RECT  61.176 21.408 61.44 21.456 ;
     RECT  61.464 21.408 61.68 21.456 ;
     RECT  61.704 21.408 61.92 21.456 ;
     RECT  61.944 21.408 62.16 21.456 ;
     RECT  62.184 21.408 62.448 21.456 ;
     RECT  62.472 21.408 62.688 21.456 ;
     RECT  62.712 21.408 62.928 21.456 ;
     RECT  62.952 21.408 63.168 21.456 ;
     RECT  63.192 21.408 63.456 21.456 ;
     RECT  63.48 21.408 63.696 21.456 ;
     RECT  63.72 21.408 63.936 21.456 ;
     RECT  63.96 21.408 64.176 21.456 ;
     RECT  64.2 21.408 64.416 21.456 ;
     RECT  64.44 21.408 64.704 21.456 ;
     RECT  64.728 21.408 64.944 21.456 ;
     RECT  64.968 21.408 65.184 21.456 ;
     RECT  65.208 21.408 65.424 21.456 ;
     RECT  65.448 21.408 65.712 21.456 ;
     RECT  65.736 21.408 65.952 21.456 ;
     RECT  65.976 21.408 66.192 21.456 ;
     RECT  66.216 21.408 66.432 21.456 ;
     RECT  66.456 21.408 66.72 21.456 ;
     RECT  66.744 21.408 66.96 21.456 ;
     RECT  66.984 21.408 67.2 21.456 ;
     RECT  67.224 21.408 67.44 21.456 ;
     RECT  67.464 21.408 67.68 21.456 ;
     RECT  67.704 21.408 67.968 21.456 ;
     RECT  67.992 21.408 68.208 21.456 ;
     RECT  68.232 21.408 68.448 21.456 ;
     RECT  68.472 21.408 68.688 21.456 ;
     RECT  68.712 21.408 68.976 21.456 ;
     RECT  69 21.408 69.216 21.456 ;
     RECT  69.24 21.408 69.456 21.456 ;
     RECT  69.48 21.408 69.696 21.456 ;
     RECT  69.72 21.408 69.984 21.456 ;
     RECT  70.008 21.408 70.224 21.456 ;
     RECT  70.248 21.408 70.464 21.456 ;
     RECT  70.488 21.408 70.704 21.456 ;
     RECT  70.728 21.408 70.944 21.456 ;
     RECT  70.968 21.408 71.232 21.456 ;
     RECT  71.256 21.408 71.472 21.456 ;
     RECT  71.496 21.408 71.712 21.456 ;
     RECT  71.736 21.408 71.952 21.456 ;
     RECT  71.976 21.408 72.24 21.456 ;
     RECT  72.264 21.408 72.48 21.456 ;
     RECT  72.504 21.408 72.72 21.456 ;
     RECT  72.744 21.408 72.96 21.456 ;
     RECT  72.984 21.408 73.248 21.456 ;
     RECT  7.584 21.456 7.608 21.491 ;
     RECT  55.872 21.456 55.896 21.491 ;
     RECT  54.984 0.227 55.056 0.24 ;
     RECT  55.176 0.227 55.2 0.24 ;
     RECT  55.32 0.227 55.344 0.24 ;
     RECT  55.464 0.227 55.536 0.24 ;
     RECT  55.656 0.227 55.68 0.24 ;
     RECT  55.8 0.227 55.872 0.24 ;
     RECT  54.936 0.24 55.92 0.563 ;
     RECT  20.328 0.323 21.504 1.811 ;
     RECT  49.032 0.563 50.016 1.763 ;
     RECT  54.936 0.563 56.064 1.139 ;
     RECT  69.096 0.563 70.08 1.715 ;
     RECT  50.04 0.611 51.072 1.139 ;
     RECT  52.296 0.611 53.904 1.139 ;
     RECT  63.096 0.611 64.224 1.283 ;
     RECT  41.4 1.139 42.384 1.763 ;
     RECT  45.864 1.139 47.04 1.763 ;
     RECT  50.04 1.139 51.6 1.763 ;
     RECT  53.7 1.139 53.904 2.137 ;
     RECT  54.456 1.139 56.064 1.763 ;
     RECT  56.28 1.139 57.264 2.137 ;
     RECT  58.44 1.139 59.424 2.137 ;
     RECT  60.264 1.715 61.248 1.763 ;
     RECT  65.592 1.715 66.912 2.867 ;
     RECT  68.904 1.715 70.08 1.763 ;
     RECT  70.584 1.715 72.048 1.763 ;
     RECT  8.376 1.763 9.84 1.811 ;
     RECT  10.812 1.763 11.856 2.291 ;
     RECT  21.612 1.763 22.656 1.859 ;
     RECT  29.712 1.763 30.72 2.387 ;
     RECT  38.712 1.763 40.2 3.443 ;
     RECT  45.864 1.763 45.912 2.151 ;
     RECT  51 1.763 51.6 2.137 ;
     RECT  54.264 1.763 56.064 2.245 ;
     RECT  57.432 1.763 58.416 2.387 ;
     RECT  60.264 1.763 61.392 2.195 ;
     RECT  68.424 1.763 70.08 2.137 ;
     RECT  5.688 1.811 6.816 1.907 ;
     RECT  19.704 1.811 21.504 2.137 ;
     RECT  11.88 1.859 13.008 2.291 ;
     RECT  21.612 1.859 22.992 4.309 ;
     RECT  5.412 1.907 6.816 2.291 ;
     RECT  19.704 2.137 21.3 2.245 ;
     RECT  68.424 2.137 69.9 2.291 ;
     RECT  27.012 2.195 28.032 2.387 ;
     RECT  36.408 2.195 37.392 2.387 ;
     RECT  19.704 2.245 21.12 2.963 ;
     RECT  54.264 2.245 55.584 2.291 ;
     RECT  13.512 2.291 14.976 5.797 ;
     RECT  43.212 2.339 44.688 4.019 ;
     RECT  29.712 2.387 30.864 2.915 ;
     RECT  33.72 2.387 34.8 4.019 ;
     RECT  57.288 2.387 58.416 2.867 ;
     RECT  31.08 2.819 32.1 3.443 ;
     RECT  29.712 2.915 31.056 3.443 ;
     RECT  24.408 3.107 25.632 5.123 ;
     RECT  25.656 3.443 26.7 5.123 ;
     RECT  33.048 4.019 34.8 4.595 ;
     RECT  21.612 4.309 22.8 4.499 ;
     RECT  21.612 4.499 23.328 4.595 ;
     RECT  21.612 4.595 24 5.701 ;
     RECT  34.368 4.595 34.8 5.365 ;
     RECT  21.612 5.701 22.8 5.843 ;
     RECT  22.824 5.701 24 5.843 ;
     RECT  13.512 5.797 14.832 6.035 ;
     RECT  23.808 5.843 24 6.373 ;
     RECT  13.512 6.035 14.976 6.323 ;
     RECT  13.512 6.323 13.608 7.381 ;
     RECT  23.808 6.373 23.904 7.141 ;
     RECT  32.412 15.349 33.504 15.829 ;
     RECT  33.528 15.349 34.8 15.875 ;
     RECT  35.352 15.349 36.48 15.877 ;
     RECT  36.504 15.349 37.5 15.637 ;
     RECT  32.52 15.829 33.504 15.875 ;
     RECT  34.704 15.875 34.8 16.021 ;
     RECT  27.336 15.877 28.704 16.501 ;
     RECT  18.912 15.925 19.92 18.805 ;
     RECT  19.944 15.925 21.024 16.405 ;
     RECT  24.504 15.973 25.968 16.021 ;
     RECT  19.944 16.405 20.928 17.843 ;
     RECT  14.376 16.501 15.9 17.029 ;
     RECT  27.672 16.501 28.704 16.549 ;
     RECT  18.384 16.595 18.48 17.077 ;
     RECT  31.776 16.595 31.968 17.653 ;
     RECT  35.688 16.979 37.008 17.315 ;
     RECT  14.376 17.029 15.408 17.171 ;
     RECT  17.064 17.077 18.48 17.411 ;
     RECT  35.688 17.315 37.5 18.277 ;
     RECT  10.272 17.411 10.5 18.805 ;
     RECT  17.064 17.411 18.6 17.507 ;
     RECT  5.412 17.459 5.544 18.805 ;
     RECT  13.512 17.507 13.656 18.805 ;
     RECT  16.212 17.507 18.6 18.805 ;
     RECT  37.812 17.507 38.568 17.653 ;
     RECT  27.768 17.651 29.088 18.805 ;
     RECT  37.812 17.653 39.312 18.805 ;
     RECT  19.944 17.843 21.024 17.941 ;
     RECT  20.04 17.941 21.024 18.805 ;
     RECT  31.776 17.987 31.968 19.093 ;
     RECT  7.488 18.131 7.536 18.805 ;
     RECT  24.888 18.227 25.968 18.275 ;
     RECT  64.812 18.229 65.952 19.957 ;
     RECT  65.976 18.229 67.2 18.757 ;
     RECT  21.612 18.275 21.72 18.805 ;
     RECT  24.888 18.275 26.112 19.333 ;
     RECT  35.688 18.277 37.248 18.805 ;
     RECT  40.512 18.757 41.568 19.957 ;
     RECT  51.312 18.757 52.608 19.141 ;
     RECT  65.976 18.757 66.96 19.957 ;
     RECT  70.968 18.757 71.952 19.957 ;
     RECT  6.024 18.805 7.536 19.093 ;
     RECT  9.048 18.805 10.5 19.093 ;
     RECT  10.812 18.805 11.808 19.093 ;
     RECT  11.832 18.805 13.104 19.093 ;
     RECT  14.088 18.805 15.072 19.333 ;
     RECT  16.584 18.805 17.568 19.333 ;
     RECT  17.592 18.805 18.6 19.333 ;
     RECT  21.612 18.805 22.608 19.333 ;
     RECT  36.168 18.805 37.152 19.333 ;
     RECT  37.944 18.805 39.312 19.333 ;
     RECT  59.688 18.805 60.912 19.381 ;
     RECT  54.648 18.851 55.872 19.957 ;
     RECT  9.048 19.093 10.272 19.333 ;
     RECT  31.776 19.093 31.872 19.333 ;
     RECT  51.312 19.141 52.368 19.449 ;
     RECT  59.688 19.381 60.672 19.957 ;
     RECT  68.712 19.381 69.792 19.957 ;
     RECT  51.144 19.449 52.368 19.957 ;
     RECT  51.144 19.957 52.128 20.533 ;
     RECT  57.432 19.957 58.416 20.533 ;
  END
END hbfd_rly_136_NS_fc_f4
END LIBRARY
